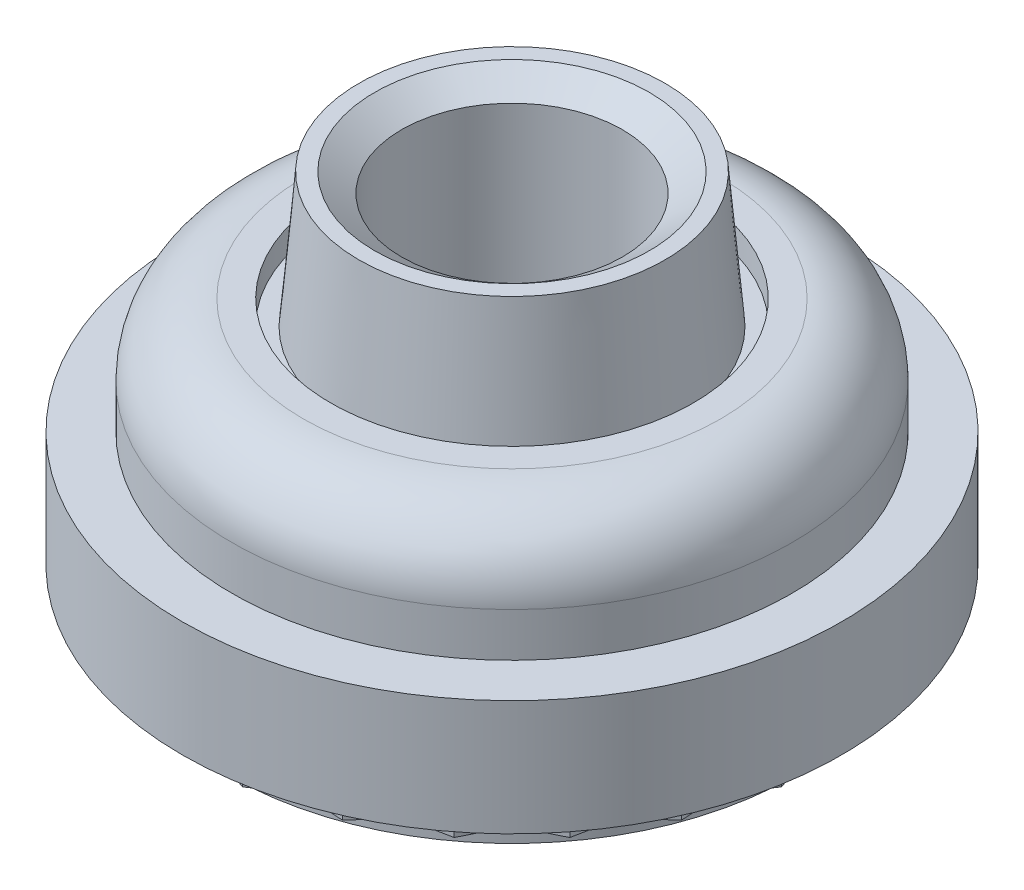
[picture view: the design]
ISO-10303-21;
HEADER;
FILE_DESCRIPTION(('STEP AP214'),'2;1');
FILE_NAME('part.step','',(''),(''),'','','');
FILE_SCHEMA(('AUTOMOTIVE_DESIGN { 1 0 10303 214 1 1 1 1 }'));
ENDSEC;
DATA;
#1=APPLICATION_CONTEXT('core data for automotive mechanical design processes');
#2=APPLICATION_PROTOCOL_DEFINITION('international standard','automotive_design',2000,#1);
#3=PRODUCT_CONTEXT('',#1,'mechanical');
#4=PRODUCT('Part','Part','',(#3));
#5=PRODUCT_RELATED_PRODUCT_CATEGORY('part','',(#4));
#6=PRODUCT_DEFINITION_FORMATION('','',#4);
#7=PRODUCT_DEFINITION_CONTEXT('part definition',#1,'design');
#8=PRODUCT_DEFINITION('design','',#6,#7);
#9=PRODUCT_DEFINITION_SHAPE('','',#8);
#10=(LENGTH_UNIT() NAMED_UNIT(*) SI_UNIT(.MILLI.,.METRE.));
#11=(NAMED_UNIT(*) PLANE_ANGLE_UNIT() SI_UNIT($,.RADIAN.));
#12=(NAMED_UNIT(*) SI_UNIT($,.STERADIAN.) SOLID_ANGLE_UNIT());
#13=UNCERTAINTY_MEASURE_WITH_UNIT(LENGTH_MEASURE(1.E-05),#10,'distance_accuracy_value','');
#14=(GEOMETRIC_REPRESENTATION_CONTEXT(3) GLOBAL_UNCERTAINTY_ASSIGNED_CONTEXT((#13)) GLOBAL_UNIT_ASSIGNED_CONTEXT((#10,
#11,#12)) REPRESENTATION_CONTEXT('',''));
#15=CARTESIAN_POINT('',(0.,0.,0.));
#16=DIRECTION('',(0.,0.,1.));
#17=DIRECTION('',(1.,0.,0.));
#18=AXIS2_PLACEMENT_3D('',#15,#16,#17);
#19=CARTESIAN_POINT('',(2.5527,-0.9652,0.));
#20=DIRECTION('',(0.,-1.,0.));
#21=DIRECTION('',(0.,0.,-1.));
#22=AXIS2_PLACEMENT_3D('',#19,#20,#21);
#23=PLANE('',#22);
#24=CARTESIAN_POINT('',(0.,-0.9652,0.));
#25=DIRECTION('',(0.,-1.,0.));
#26=DIRECTION('',(0.,0.,-1.));
#27=AXIS2_PLACEMENT_3D('',#24,#25,#26);
#28=CIRCLE('',#27,3.175);
#29=CARTESIAN_POINT('',(0.,-0.9652,-3.175));
#30=VERTEX_POINT('',#29);
#31=EDGE_CURVE('E39',#30,#30,#28,.T.);
#32=ORIENTED_EDGE('',*,*,#31,.F.);
#33=EDGE_LOOP('',(#32));
#34=FACE_BOUND('',#33,.T.);
#35=DIRECTION('',(-1.,0.,0.));
#36=VECTOR('',#35,1.);
#37=CARTESIAN_POINT('',(3.556,-0.9652,3.81));
#38=LINE('',#37,#36);
#39=CARTESIAN_POINT('',(3.556,-0.9652,3.81));
#40=VERTEX_POINT('',#39);
#41=CARTESIAN_POINT('',(-3.556,-0.9652,3.81));
#42=VERTEX_POINT('',#41);
#43=EDGE_CURVE('E752',#40,#42,#38,.T.);
#44=ORIENTED_EDGE('',*,*,#43,.T.);
#45=CARTESIAN_POINT('',(-3.556,-0.9652,3.556));
#46=DIRECTION('',(0.,-1.,0.));
#47=DIRECTION('',(0.,0.,1.));
#48=AXIS2_PLACEMENT_3D('',#45,#46,#47);
#49=CIRCLE('',#48,0.254);
#50=CARTESIAN_POINT('',(-3.81,-0.9652,3.556));
#51=VERTEX_POINT('',#50);
#52=EDGE_CURVE('E772',#42,#51,#49,.T.);
#53=ORIENTED_EDGE('',*,*,#52,.T.);
#54=DIRECTION('',(0.,0.,-1.));
#55=VECTOR('',#54,1.);
#56=CARTESIAN_POINT('',(-3.81,-0.9652,3.556));
#57=LINE('',#56,#55);
#58=CARTESIAN_POINT('',(-3.81,-0.9652,-3.556));
#59=VERTEX_POINT('',#58);
#60=EDGE_CURVE('E731',#51,#59,#57,.T.);
#61=ORIENTED_EDGE('',*,*,#60,.T.);
#62=CARTESIAN_POINT('',(-3.556,-0.9652,-3.556));
#63=DIRECTION('',(0.,-1.,0.));
#64=DIRECTION('',(0.,0.,-1.));
#65=AXIS2_PLACEMENT_3D('',#62,#63,#64);
#66=CIRCLE('',#65,0.254);
#67=CARTESIAN_POINT('',(-3.556,-0.9652,-3.81));
#68=VERTEX_POINT('',#67);
#69=EDGE_CURVE('E59',#59,#68,#66,.T.);
#70=ORIENTED_EDGE('',*,*,#69,.T.);
#71=DIRECTION('',(1.,0.,0.));
#72=VECTOR('',#71,1.);
#73=CARTESIAN_POINT('',(-3.556,-0.9652,-3.81));
#74=LINE('',#73,#72);
#75=CARTESIAN_POINT('',(3.556,-0.9652,-3.81));
#76=VERTEX_POINT('',#75);
#77=EDGE_CURVE('E776',#68,#76,#74,.T.);
#78=ORIENTED_EDGE('',*,*,#77,.T.);
#79=CARTESIAN_POINT('',(3.556,-0.9652,-3.556));
#80=DIRECTION('',(0.,-1.,0.));
#81=DIRECTION('',(0.,0.,-1.));
#82=AXIS2_PLACEMENT_3D('',#79,#80,#81);
#83=CIRCLE('',#82,0.254);
#84=CARTESIAN_POINT('',(3.81,-0.9652,-3.556));
#85=VERTEX_POINT('',#84);
#86=EDGE_CURVE('E779',#76,#85,#83,.T.);
#87=ORIENTED_EDGE('',*,*,#86,.T.);
#88=DIRECTION('',(0.,0.,1.));
#89=VECTOR('',#88,1.);
#90=CARTESIAN_POINT('',(3.81,-0.9652,-3.556));
#91=LINE('',#90,#89);
#92=CARTESIAN_POINT('',(3.81,-0.9652,3.556));
#93=VERTEX_POINT('',#92);
#94=EDGE_CURVE('E782',#85,#93,#91,.T.);
#95=ORIENTED_EDGE('',*,*,#94,.T.);
#96=CARTESIAN_POINT('',(3.556,-0.9652,3.556));
#97=DIRECTION('',(0.,-1.,0.));
#98=DIRECTION('',(0.,0.,-1.));
#99=AXIS2_PLACEMENT_3D('',#96,#97,#98);
#100=CIRCLE('',#99,0.254);
#101=EDGE_CURVE('E755',#93,#40,#100,.T.);
#102=ORIENTED_EDGE('',*,*,#101,.T.);
#103=EDGE_LOOP('',(#44,#53,#61,#70,#78,#87,#95,#102));
#104=FACE_BOUND('',#103,.T.);
#105=ADVANCED_FACE('F35',(#34,#104),#23,.T.);
#106=CARTESIAN_POINT('',(6.30489660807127,0.,0.));
#107=DIRECTION('',(0.,-1.,0.));
#108=DIRECTION('',(0.,0.,-1.));
#109=AXIS2_PLACEMENT_3D('',#106,#107,#108);
#110=PLANE('',#109);
#111=CARTESIAN_POINT('',(0.,0.,0.));
#112=DIRECTION('',(0.,-1.,0.));
#113=DIRECTION('',(0.,0.,-1.));
#114=AXIS2_PLACEMENT_3D('',#111,#112,#113);
#115=CIRCLE('',#114,7.62);
#116=CARTESIAN_POINT('',(0.,0.,-7.62));
#117=VERTEX_POINT('',#116);
#118=EDGE_CURVE('E1570',#117,#117,#115,.T.);
#119=ORIENTED_EDGE('',*,*,#118,.T.);
#120=EDGE_LOOP('',(#119));
#121=FACE_BOUND('',#120,.T.);
#122=DIRECTION('',(-0.947439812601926,0.,-0.31993405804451));
#123=VECTOR('',#122,1.);
#124=CARTESIAN_POINT('',(0.944879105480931,0.,7.17706935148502));
#125=LINE('',#124,#123);
#126=CARTESIAN_POINT('',(0.94487910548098,0.,7.17706935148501));
#127=VERTEX_POINT('',#126);
#128=CARTESIAN_POINT('',(0.,0.,6.858));
#129=VERTEX_POINT('',#128);
#130=EDGE_CURVE('E1522',#127,#129,#125,.T.);
#131=ORIENTED_EDGE('',*,*,#130,.F.);
#132=DIRECTION('',(-0.83235155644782,0.,0.5542480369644));
#133=VECTOR('',#132,1.);
#134=CARTESIAN_POINT('',(1.77498101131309,0.,6.62431931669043));
#135=LINE('',#134,#133);
#136=CARTESIAN_POINT('',(1.77498101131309,0.,6.62431931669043));
#137=VERTEX_POINT('',#136);
#138=EDGE_CURVE('E1507',#137,#127,#135,.T.);
#139=ORIENTED_EDGE('',*,*,#138,.F.);
#140=DIRECTION('',(-0.99796161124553,0.,-0.063817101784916));
#141=VECTOR('',#140,1.);
#142=CARTESIAN_POINT('',(2.77024536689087,0.,6.68796393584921));
#143=LINE('',#142,#141);
#144=CARTESIAN_POINT('',(2.77024536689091,0.,6.68796393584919));
#145=VERTEX_POINT('',#144);
#146=EDGE_CURVE('E1495',#145,#137,#143,.T.);
#147=ORIENTED_EDGE('',*,*,#146,.F.);
#148=DIRECTION('',(-0.660539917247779,0.,0.750790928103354));
#149=VECTOR('',#148,1.);
#150=CARTESIAN_POINT('',(3.42900000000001,0.,5.93920221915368));
#151=LINE('',#150,#149);
#152=CARTESIAN_POINT('',(3.42900000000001,0.,5.93920221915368));
#153=VERTEX_POINT('',#152);
#154=EDGE_CURVE('E1479',#153,#145,#151,.T.);
#155=ORIENTED_EDGE('',*,*,#154,.F.);
#156=DIRECTION('',(-0.98047397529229,0.,0.196648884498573));
#157=VECTOR('',#156,1.);
#158=CARTESIAN_POINT('',(4.40682398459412,0.,5.74308483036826));
#159=LINE('',#158,#157);
#160=CARTESIAN_POINT('',(4.40682398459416,0.,5.74308483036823));
#161=VERTEX_POINT('',#160);
#162=EDGE_CURVE('E1466',#161,#153,#159,.T.);
#163=ORIENTED_EDGE('',*,*,#162,.F.);
#164=DIRECTION('',(-0.443713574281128,0.,0.896168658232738));
#165=VECTOR('',#164,1.);
#166=CARTESIAN_POINT('',(4.84933830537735,0.,4.84933830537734));
#167=LINE('',#166,#165);
#168=CARTESIAN_POINT('',(4.84933830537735,0.,4.84933830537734));
#169=VERTEX_POINT('',#168);
#170=EDGE_CURVE('E1450',#169,#161,#167,.T.);
#171=ORIENTED_EDGE('',*,*,#170,.F.);
#172=DIRECTION('',(-0.896168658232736,0.,0.443713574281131));
#173=VECTOR('',#172,1.);
#174=CARTESIAN_POINT('',(5.74308483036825,0.,4.40682398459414));
#175=LINE('',#174,#173);
#176=CARTESIAN_POINT('',(5.74308483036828,0.,4.4068239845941));
#177=VERTEX_POINT('',#176);
#178=EDGE_CURVE('E1437',#177,#169,#175,.T.);
#179=ORIENTED_EDGE('',*,*,#178,.F.);
#180=DIRECTION('',(-0.19664888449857,0.,0.980473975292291));
#181=VECTOR('',#180,1.);
#182=CARTESIAN_POINT('',(5.93920221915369,0.,3.42899999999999));
#183=LINE('',#182,#181);
#184=CARTESIAN_POINT('',(5.93920221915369,0.,3.42899999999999));
#185=VERTEX_POINT('',#184);
#186=EDGE_CURVE('E1421',#185,#177,#183,.T.);
#187=ORIENTED_EDGE('',*,*,#186,.F.);
#188=DIRECTION('',(-0.750790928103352,0.,0.660539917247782));
#189=VECTOR('',#188,1.);
#190=CARTESIAN_POINT('',(6.6879639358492,0.,2.77024536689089));
#191=LINE('',#190,#189);
#192=CARTESIAN_POINT('',(6.68796393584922,0.,2.77024536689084));
#193=VERTEX_POINT('',#192);
#194=EDGE_CURVE('E1408',#193,#185,#191,.T.);
#195=ORIENTED_EDGE('',*,*,#194,.F.);
#196=DIRECTION('',(0.0638171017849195,0.,0.99796161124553));
#197=VECTOR('',#196,1.);
#198=CARTESIAN_POINT('',(6.62431931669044,0.,1.77498101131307));
#199=LINE('',#198,#197);
#200=CARTESIAN_POINT('',(6.62431931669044,0.,1.77498101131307));
#201=VERTEX_POINT('',#200);
#202=EDGE_CURVE('E1392',#201,#193,#199,.T.);
#203=ORIENTED_EDGE('',*,*,#202,.F.);
#204=DIRECTION('',(-0.554248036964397,0.,0.832351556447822));
#205=VECTOR('',#204,1.);
#206=CARTESIAN_POINT('',(7.17706935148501,0.,0.944879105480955));
#207=LINE('',#206,#205);
#208=CARTESIAN_POINT('',(7.17706935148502,0.,0.944879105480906));
#209=VERTEX_POINT('',#208);
#210=EDGE_CURVE('E1379',#209,#201,#207,.T.);
#211=ORIENTED_EDGE('',*,*,#210,.F.);
#212=DIRECTION('',(0.319934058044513,0.,0.947439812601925));
#213=VECTOR('',#212,1.);
#214=CARTESIAN_POINT('',(6.858,0.,0.));
#215=LINE('',#214,#213);
#216=CARTESIAN_POINT('',(6.858,0.,0.));
#217=VERTEX_POINT('',#216);
#218=EDGE_CURVE('E1363',#217,#209,#215,.T.);
#219=ORIENTED_EDGE('',*,*,#218,.F.);
#220=DIRECTION('',(-0.319934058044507,0.,0.947439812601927));
#221=VECTOR('',#220,1.);
#222=CARTESIAN_POINT('',(7.17706935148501,0.,-0.944879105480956));
#223=LINE('',#222,#221);
#224=CARTESIAN_POINT('',(7.17706935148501,0.,-0.944879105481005));
#225=VERTEX_POINT('',#224);
#226=EDGE_CURVE('E1350',#225,#217,#223,.T.);
#227=ORIENTED_EDGE('',*,*,#226,.F.);
#228=DIRECTION('',(0.554248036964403,0.,0.832351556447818));
#229=VECTOR('',#228,1.);
#230=CARTESIAN_POINT('',(6.62431931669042,0.,-1.77498101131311));
#231=LINE('',#230,#229);
#232=CARTESIAN_POINT('',(6.62431931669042,0.,-1.77498101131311));
#233=VERTEX_POINT('',#232);
#234=EDGE_CURVE('E1334',#233,#225,#231,.T.);
#235=ORIENTED_EDGE('',*,*,#234,.F.);
#236=DIRECTION('',(-0.0638171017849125,0.,0.99796161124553));
#237=VECTOR('',#236,1.);
#238=CARTESIAN_POINT('',(6.6879639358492,0.,-2.77024536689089));
#239=LINE('',#238,#237);
#240=CARTESIAN_POINT('',(6.68796393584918,0.,-2.77024536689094));
#241=VERTEX_POINT('',#240);
#242=EDGE_CURVE('E1321',#241,#233,#239,.T.);
#243=ORIENTED_EDGE('',*,*,#242,.F.);
#244=DIRECTION('',(0.750790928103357,0.,0.660539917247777));
#245=VECTOR('',#244,1.);
#246=CARTESIAN_POINT('',(5.93920221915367,0.,-3.42900000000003));
#247=LINE('',#246,#245);
#248=CARTESIAN_POINT('',(5.93920221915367,0.,-3.42900000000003));
#249=VERTEX_POINT('',#248);
#250=EDGE_CURVE('E1305',#249,#241,#247,.T.);
#251=ORIENTED_EDGE('',*,*,#250,.F.);
#252=DIRECTION('',(0.196648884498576,0.,0.98047397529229));
#253=VECTOR('',#252,1.);
#254=CARTESIAN_POINT('',(5.74308483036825,0.,-4.40682398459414));
#255=LINE('',#254,#253);
#256=CARTESIAN_POINT('',(5.74308483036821,0.,-4.40682398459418));
#257=VERTEX_POINT('',#256);
#258=EDGE_CURVE('E1292',#257,#249,#255,.T.);
#259=ORIENTED_EDGE('',*,*,#258,.F.);
#260=DIRECTION('',(0.896168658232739,0.,0.443713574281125));
#261=VECTOR('',#260,1.);
#262=CARTESIAN_POINT('',(4.84933830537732,0.,-4.84933830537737));
#263=LINE('',#262,#261);
#264=CARTESIAN_POINT('',(4.84933830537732,0.,-4.84933830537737));
#265=VERTEX_POINT('',#264);
#266=EDGE_CURVE('E1276',#265,#257,#263,.T.);
#267=ORIENTED_EDGE('',*,*,#266,.F.);
#268=DIRECTION('',(0.443713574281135,0.,0.896168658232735));
#269=VECTOR('',#268,1.);
#270=CARTESIAN_POINT('',(4.40682398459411,0.,-5.74308483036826));
#271=LINE('',#270,#269);
#272=CARTESIAN_POINT('',(4.40682398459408,0.,-5.74308483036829));
#273=VERTEX_POINT('',#272);
#274=EDGE_CURVE('E1263',#273,#265,#271,.T.);
#275=ORIENTED_EDGE('',*,*,#274,.F.);
#276=DIRECTION('',(0.980473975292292,0.,0.196648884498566));
#277=VECTOR('',#276,1.);
#278=CARTESIAN_POINT('',(3.42899999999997,0.,-5.9392022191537));
#279=LINE('',#278,#277);
#280=CARTESIAN_POINT('',(3.42899999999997,0.,-5.9392022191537));
#281=VERTEX_POINT('',#280);
#282=EDGE_CURVE('E1247',#281,#273,#279,.T.);
#283=ORIENTED_EDGE('',*,*,#282,.F.);
#284=DIRECTION('',(0.660539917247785,0.,0.75079092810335));
#285=VECTOR('',#284,1.);
#286=CARTESIAN_POINT('',(2.77024536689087,0.,-6.68796393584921));
#287=LINE('',#286,#285);
#288=CARTESIAN_POINT('',(2.77024536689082,0.,-6.68796393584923));
#289=VERTEX_POINT('',#288);
#290=EDGE_CURVE('E1234',#289,#281,#287,.T.);
#291=ORIENTED_EDGE('',*,*,#290,.F.);
#292=DIRECTION('',(0.997961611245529,0.,-0.063817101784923));
#293=VECTOR('',#292,1.);
#294=CARTESIAN_POINT('',(1.77498101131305,0.,-6.62431931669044));
#295=LINE('',#294,#293);
#296=CARTESIAN_POINT('',(1.77498101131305,0.,-6.62431931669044));
#297=VERTEX_POINT('',#296);
#298=EDGE_CURVE('E1218',#297,#289,#295,.T.);
#299=ORIENTED_EDGE('',*,*,#298,.F.);
#300=DIRECTION('',(0.832351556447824,0.,0.554248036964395));
#301=VECTOR('',#300,1.);
#302=CARTESIAN_POINT('',(0.94487910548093,0.,-7.17706935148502));
#303=LINE('',#302,#301);
#304=CARTESIAN_POINT('',(0.944879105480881,0.,-7.17706935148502));
#305=VERTEX_POINT('',#304);
#306=EDGE_CURVE('E1205',#305,#297,#303,.T.);
#307=ORIENTED_EDGE('',*,*,#306,.F.);
#308=DIRECTION('',(0.947439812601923,0.,-0.319934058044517));
#309=VECTOR('',#308,1.);
#310=CARTESIAN_POINT('',(0.,0.,-6.858));
#311=LINE('',#310,#309);
#312=CARTESIAN_POINT('',(0.,0.,-6.858));
#313=VERTEX_POINT('',#312);
#314=EDGE_CURVE('E1189',#313,#305,#311,.T.);
#315=ORIENTED_EDGE('',*,*,#314,.F.);
#316=DIRECTION('',(0.947439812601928,0.,0.319934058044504));
#317=VECTOR('',#316,1.);
#318=CARTESIAN_POINT('',(-0.944879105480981,0.,-7.17706935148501));
#319=LINE('',#318,#317);
#320=CARTESIAN_POINT('',(-0.944879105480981,0.,-7.17706935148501));
#321=VERTEX_POINT('',#320);
#322=EDGE_CURVE('E1176',#321,#313,#319,.T.);
#323=ORIENTED_EDGE('',*,*,#322,.F.);
#324=DIRECTION('',(0.832351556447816,0.,-0.554248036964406));
#325=VECTOR('',#324,1.);
#326=CARTESIAN_POINT('',(-1.77498101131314,0.,-6.62431931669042));
#327=LINE('',#326,#325);
#328=CARTESIAN_POINT('',(-1.77498101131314,0.,-6.62431931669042));
#329=VERTEX_POINT('',#328);
#330=EDGE_CURVE('E1160',#329,#321,#327,.T.);
#331=ORIENTED_EDGE('',*,*,#330,.F.);
#332=DIRECTION('',(0.99796161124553,0.,0.063817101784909));
#333=VECTOR('',#332,1.);
#334=CARTESIAN_POINT('',(-2.77024536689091,0.,-6.68796393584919));
#335=LINE('',#334,#333);
#336=CARTESIAN_POINT('',(-2.77024536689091,0.,-6.68796393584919));
#337=VERTEX_POINT('',#336);
#338=EDGE_CURVE('E1147',#337,#329,#335,.T.);
#339=ORIENTED_EDGE('',*,*,#338,.F.);
#340=DIRECTION('',(0.660539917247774,0.,-0.750790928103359));
#341=VECTOR('',#340,1.);
#342=CARTESIAN_POINT('',(-3.42900000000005,0.,-5.93920221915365));
#343=LINE('',#342,#341);
#344=CARTESIAN_POINT('',(-3.42900000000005,0.,-5.93920221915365));
#345=VERTEX_POINT('',#344);
#346=EDGE_CURVE('E1131',#345,#337,#343,.T.);
#347=ORIENTED_EDGE('',*,*,#346,.F.);
#348=DIRECTION('',(0.980473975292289,0.,-0.19664888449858));
#349=VECTOR('',#348,1.);
#350=CARTESIAN_POINT('',(-4.40682398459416,0.,-5.74308483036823));
#351=LINE('',#350,#349);
#352=CARTESIAN_POINT('',(-4.40682398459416,0.,-5.74308483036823));
#353=VERTEX_POINT('',#352);
#354=EDGE_CURVE('E1118',#353,#345,#351,.T.);
#355=ORIENTED_EDGE('',*,*,#354,.F.);
#356=DIRECTION('',(0.443713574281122,0.,-0.896168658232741));
#357=VECTOR('',#356,1.);
#358=CARTESIAN_POINT('',(-4.84933830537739,0.,-4.8493383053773));
#359=LINE('',#358,#357);
#360=CARTESIAN_POINT('',(-4.84933830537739,0.,-4.8493383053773));
#361=VERTEX_POINT('',#360);
#362=EDGE_CURVE('E1102',#361,#353,#359,.T.);
#363=ORIENTED_EDGE('',*,*,#362,.F.);
#364=DIRECTION('',(0.896168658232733,0.,-0.443713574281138));
#365=VECTOR('',#364,1.);
#366=CARTESIAN_POINT('',(-5.74308483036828,0.,-4.4068239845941));
#367=LINE('',#366,#365);
#368=CARTESIAN_POINT('',(-5.74308483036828,0.,-4.4068239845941));
#369=VERTEX_POINT('',#368);
#370=EDGE_CURVE('E1089',#369,#361,#367,.T.);
#371=ORIENTED_EDGE('',*,*,#370,.F.);
#372=DIRECTION('',(0.196648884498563,0.,-0.980473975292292));
#373=VECTOR('',#372,1.);
#374=CARTESIAN_POINT('',(-5.93920221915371,0.,-3.42899999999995));
#375=LINE('',#374,#373);
#376=CARTESIAN_POINT('',(-5.93920221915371,0.,-3.42899999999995));
#377=VERTEX_POINT('',#376);
#378=EDGE_CURVE('E1073',#377,#369,#375,.T.);
#379=ORIENTED_EDGE('',*,*,#378,.F.);
#380=DIRECTION('',(0.750790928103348,0.,-0.660539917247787));
#381=VECTOR('',#380,1.);
#382=CARTESIAN_POINT('',(-6.68796393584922,0.,-2.77024536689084));
#383=LINE('',#382,#381);
#384=CARTESIAN_POINT('',(-6.68796393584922,0.,-2.77024536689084));
#385=VERTEX_POINT('',#384);
#386=EDGE_CURVE('E1060',#385,#377,#383,.T.);
#387=ORIENTED_EDGE('',*,*,#386,.F.);
#388=DIRECTION('',(-0.0638171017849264,0.,-0.997961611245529));
#389=VECTOR('',#388,1.);
#390=CARTESIAN_POINT('',(-6.62431931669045,0.,-1.77498101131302));
#391=LINE('',#390,#389);
#392=CARTESIAN_POINT('',(-6.62431931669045,0.,-1.77498101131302));
#393=VERTEX_POINT('',#392);
#394=EDGE_CURVE('E1044',#393,#385,#391,.T.);
#395=ORIENTED_EDGE('',*,*,#394,.F.);
#396=DIRECTION('',(0.554248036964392,0.,-0.832351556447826));
#397=VECTOR('',#396,1.);
#398=CARTESIAN_POINT('',(-7.17706935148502,0.,-0.944879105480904));
#399=LINE('',#398,#397);
#400=CARTESIAN_POINT('',(-7.17706935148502,0.,-0.944879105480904));
#401=VERTEX_POINT('',#400);
#402=EDGE_CURVE('E1031',#401,#393,#399,.T.);
#403=ORIENTED_EDGE('',*,*,#402,.F.);
#404=DIRECTION('',(-0.31993405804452,0.,-0.947439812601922));
#405=VECTOR('',#404,1.);
#406=CARTESIAN_POINT('',(-6.858,0.,0.));
#407=LINE('',#406,#405);
#408=CARTESIAN_POINT('',(-6.858,0.,0.));
#409=VERTEX_POINT('',#408);
#410=EDGE_CURVE('E1015',#409,#401,#407,.T.);
#411=ORIENTED_EDGE('',*,*,#410,.F.);
#412=DIRECTION('',(0.3199340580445,0.,-0.947439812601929));
#413=VECTOR('',#412,1.);
#414=CARTESIAN_POINT('',(-7.17706935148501,0.,0.944879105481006));
#415=LINE('',#414,#413);
#416=CARTESIAN_POINT('',(-7.17706935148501,0.,0.944879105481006));
#417=VERTEX_POINT('',#416);
#418=EDGE_CURVE('E1002',#417,#409,#415,.T.);
#419=ORIENTED_EDGE('',*,*,#418,.F.);
#420=DIRECTION('',(-0.554248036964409,0.,-0.832351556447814));
#421=VECTOR('',#420,1.);
#422=CARTESIAN_POINT('',(-6.62431931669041,0.,1.77498101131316));
#423=LINE('',#422,#421);
#424=CARTESIAN_POINT('',(-6.62431931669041,0.,1.77498101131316));
#425=VERTEX_POINT('',#424);
#426=EDGE_CURVE('E986',#425,#417,#423,.T.);
#427=ORIENTED_EDGE('',*,*,#426,.F.);
#428=DIRECTION('',(0.0638171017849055,0.,-0.99796161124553));
#429=VECTOR('',#428,1.);
#430=CARTESIAN_POINT('',(-6.68796393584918,0.,2.77024536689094));
#431=LINE('',#430,#429);
#432=CARTESIAN_POINT('',(-6.68796393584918,0.,2.77024536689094));
#433=VERTEX_POINT('',#432);
#434=EDGE_CURVE('E973',#433,#425,#431,.T.);
#435=ORIENTED_EDGE('',*,*,#434,.F.);
#436=DIRECTION('',(-0.750790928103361,0.,-0.660539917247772));
#437=VECTOR('',#436,1.);
#438=CARTESIAN_POINT('',(-5.93920221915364,0.,3.42900000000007));
#439=LINE('',#438,#437);
#440=CARTESIAN_POINT('',(-5.93920221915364,0.,3.42900000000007));
#441=VERTEX_POINT('',#440);
#442=EDGE_CURVE('E957',#441,#433,#439,.T.);
#443=ORIENTED_EDGE('',*,*,#442,.F.);
#444=DIRECTION('',(-0.196648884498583,0.,-0.980473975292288));
#445=VECTOR('',#444,1.);
#446=CARTESIAN_POINT('',(-5.74308483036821,0.,4.40682398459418));
#447=LINE('',#446,#445);
#448=CARTESIAN_POINT('',(-5.74308483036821,0.,4.40682398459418));
#449=VERTEX_POINT('',#448);
#450=EDGE_CURVE('E944',#449,#441,#447,.T.);
#451=ORIENTED_EDGE('',*,*,#450,.F.);
#452=DIRECTION('',(-0.896168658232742,0.,-0.443713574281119));
#453=VECTOR('',#452,1.);
#454=CARTESIAN_POINT('',(-4.84933830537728,0.,4.8493383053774));
#455=LINE('',#454,#453);
#456=CARTESIAN_POINT('',(-4.84933830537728,0.,4.8493383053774));
#457=VERTEX_POINT('',#456);
#458=EDGE_CURVE('E928',#457,#449,#455,.T.);
#459=ORIENTED_EDGE('',*,*,#458,.F.);
#460=DIRECTION('',(-0.443713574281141,0.,-0.896168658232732));
#461=VECTOR('',#460,1.);
#462=CARTESIAN_POINT('',(-4.40682398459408,0.,5.74308483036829));
#463=LINE('',#462,#461);
#464=CARTESIAN_POINT('',(-4.40682398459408,0.,5.74308483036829));
#465=VERTEX_POINT('',#464);
#466=EDGE_CURVE('E915',#465,#457,#463,.T.);
#467=ORIENTED_EDGE('',*,*,#466,.F.);
#468=DIRECTION('',(-0.980473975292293,0.,-0.196648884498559));
#469=VECTOR('',#468,1.);
#470=CARTESIAN_POINT('',(-3.42899999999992,0.,5.93920221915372));
#471=LINE('',#470,#469);
#472=CARTESIAN_POINT('',(-3.42899999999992,0.,5.93920221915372));
#473=VERTEX_POINT('',#472);
#474=EDGE_CURVE('E899',#473,#465,#471,.T.);
#475=ORIENTED_EDGE('',*,*,#474,.F.);
#476=DIRECTION('',(-0.66053991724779,0.,-0.750790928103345));
#477=VECTOR('',#476,1.);
#478=CARTESIAN_POINT('',(-2.77024536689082,0.,6.68796393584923));
#479=LINE('',#478,#477);
#480=CARTESIAN_POINT('',(-2.77024536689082,0.,6.68796393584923));
#481=VERTEX_POINT('',#480);
#482=EDGE_CURVE('E886',#481,#473,#479,.T.);
#483=ORIENTED_EDGE('',*,*,#482,.F.);
#484=DIRECTION('',(-0.997961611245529,0.,0.0638171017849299));
#485=VECTOR('',#484,1.);
#486=CARTESIAN_POINT('',(-1.774981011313,0.,6.62431931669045));
#487=LINE('',#486,#485);
#488=CARTESIAN_POINT('',(-1.774981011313,0.,6.62431931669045));
#489=VERTEX_POINT('',#488);
#490=EDGE_CURVE('E875',#489,#481,#487,.T.);
#491=ORIENTED_EDGE('',*,*,#490,.F.);
#492=DIRECTION('',(-0.832351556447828,0.,-0.554248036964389));
#493=VECTOR('',#492,1.);
#494=CARTESIAN_POINT('',(-0.94487910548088,0.,7.17706935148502));
#495=LINE('',#494,#493);
#496=CARTESIAN_POINT('',(-0.94487910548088,0.,7.17706935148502));
#497=VERTEX_POINT('',#496);
#498=EDGE_CURVE('E848',#497,#489,#495,.T.);
#499=ORIENTED_EDGE('',*,*,#498,.F.);
#500=DIRECTION('',(-0.947439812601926,0.,0.31993405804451));
#501=VECTOR('',#500,1.);
#502=CARTESIAN_POINT('',(0.,0.,6.858));
#503=LINE('',#502,#501);
#504=EDGE_CURVE('E1536',#129,#497,#503,.T.);
#505=ORIENTED_EDGE('',*,*,#504,.F.);
#506=EDGE_LOOP('',(#131,#139,#147,#155,#163,#171,#179,#187,#195,#203,#211,#219,#227,#235,#243,
#251,#259,#267,#275,#283,#291,#299,#307,#315,#323,#331,#339,#347,#355,#363,#371,#379,#387,#395,
#403,#411,#419,#427,#435,#443,#451,#459,#467,#475,#483,#491,#499,#505));
#507=FACE_BOUND('',#506,.T.);
#508=ADVANCED_FACE('F1622',(#121,#507),#110,.T.);
#509=CARTESIAN_POINT('',(0.,0.,0.));
#510=DIRECTION('',(0.,-1.,0.));
#511=DIRECTION('',(0.,0.,-1.));
#512=AXIS2_PLACEMENT_3D('',#509,#510,#511);
#513=CIRCLE('',#512,6.30489660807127);
#514=CARTESIAN_POINT('',(0.,0.,-6.30489660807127));
#515=VERTEX_POINT('',#514);
#516=EDGE_CURVE('E1573',#515,#515,#513,.T.);
#517=ORIENTED_EDGE('',*,*,#516,.F.);
#518=EDGE_LOOP('',(#517));
#519=FACE_BOUND('',#518,.T.);
#520=DIRECTION('',(0.99796161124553,0.,0.0638171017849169));
#521=VECTOR('',#520,1.);
#522=CARTESIAN_POINT('',(1.7217315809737,0.,6.42558973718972));
#523=LINE('',#522,#521);
#524=CARTESIAN_POINT('',(1.7217315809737,0.,6.42558973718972));
#525=VERTEX_POINT('',#524);
#526=CARTESIAN_POINT('',(2.68713800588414,0.,6.48732501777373));
#527=VERTEX_POINT('',#526);
#528=EDGE_CURVE('E1499',#525,#527,#523,.T.);
#529=ORIENTED_EDGE('',*,*,#528,.F.);
#530=DIRECTION('',(0.83235155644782,0.,-0.554248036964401));
#531=VECTOR('',#530,1.);
#532=CARTESIAN_POINT('',(0.916532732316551,0.,6.96175727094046));
#533=LINE('',#532,#531);
#534=CARTESIAN_POINT('',(0.916532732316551,0.,6.96175727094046));
#535=VERTEX_POINT('',#534);
#536=EDGE_CURVE('E1509',#535,#525,#533,.T.);
#537=ORIENTED_EDGE('',*,*,#536,.F.);
#538=DIRECTION('',(0.947439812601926,0.,0.319934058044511));
#539=VECTOR('',#538,1.);
#540=CARTESIAN_POINT('',(0.,0.,6.65226));
#541=LINE('',#540,#539);
#542=CARTESIAN_POINT('',(0.,0.,6.65226));
#543=VERTEX_POINT('',#542);
#544=EDGE_CURVE('E1526',#543,#535,#541,.T.);
#545=ORIENTED_EDGE('',*,*,#544,.F.);
#546=DIRECTION('',(0.947439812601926,0.,-0.319934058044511));
#547=VECTOR('',#546,1.);
#548=CARTESIAN_POINT('',(-0.916532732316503,0.,6.96175727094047));
#549=LINE('',#548,#547);
#550=CARTESIAN_POINT('',(-0.916532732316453,0.,6.96175727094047));
#551=VERTEX_POINT('',#550);
#552=EDGE_CURVE('E1539',#551,#543,#549,.T.);
#553=ORIENTED_EDGE('',*,*,#552,.F.);
#554=DIRECTION('',(0.832351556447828,0.,0.55424803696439));
#555=VECTOR('',#554,1.);
#556=CARTESIAN_POINT('',(-1.72173158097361,0.,6.42558973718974));
#557=LINE('',#556,#555);
#558=CARTESIAN_POINT('',(-1.72173158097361,0.,6.42558973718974));
#559=VERTEX_POINT('',#558);
#560=EDGE_CURVE('E865',#559,#551,#557,.T.);
#561=ORIENTED_EDGE('',*,*,#560,.F.);
#562=DIRECTION('',(0.997961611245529,0.,-0.0638171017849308));
#563=VECTOR('',#562,1.);
#564=CARTESIAN_POINT('',(-2.68713800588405,0.,6.48732501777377));
#565=LINE('',#564,#563);
#566=CARTESIAN_POINT('',(-2.68713800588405,0.,6.48732501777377));
#567=VERTEX_POINT('',#566);
#568=EDGE_CURVE('E878',#567,#559,#565,.T.);
#569=ORIENTED_EDGE('',*,*,#568,.F.);
#570=DIRECTION('',(0.660539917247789,0.,0.750790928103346));
#571=VECTOR('',#570,1.);
#572=CARTESIAN_POINT('',(-3.32612999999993,0.,5.76102615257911));
#573=LINE('',#572,#571);
#574=CARTESIAN_POINT('',(-3.32612999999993,0.,5.76102615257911));
#575=VERTEX_POINT('',#574);
#576=EDGE_CURVE('E890',#575,#567,#573,.T.);
#577=ORIENTED_EDGE('',*,*,#576,.F.);
#578=DIRECTION('',(0.980473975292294,0.,0.196648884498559));
#579=VECTOR('',#578,1.);
#580=CARTESIAN_POINT('',(-4.27461926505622,0.,5.57079228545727));
#581=LINE('',#580,#579);
#582=CARTESIAN_POINT('',(-4.27461926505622,0.,5.57079228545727));
#583=VERTEX_POINT('',#582);
#584=EDGE_CURVE('E902',#583,#575,#581,.T.);
#585=ORIENTED_EDGE('',*,*,#584,.F.);
#586=DIRECTION('',(0.44371357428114,0.,0.896168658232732));
#587=VECTOR('',#586,1.);
#588=CARTESIAN_POINT('',(-4.70385815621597,0.,4.70385815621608));
#589=LINE('',#588,#587);
#590=CARTESIAN_POINT('',(-4.70385815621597,0.,4.70385815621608));
#591=VERTEX_POINT('',#590);
#592=EDGE_CURVE('E919',#591,#583,#589,.T.);
#593=ORIENTED_EDGE('',*,*,#592,.F.);
#594=DIRECTION('',(0.896168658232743,0.,0.443713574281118));
#595=VECTOR('',#594,1.);
#596=CARTESIAN_POINT('',(-5.57079228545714,0.,4.27461926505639));
#597=LINE('',#596,#595);
#598=CARTESIAN_POINT('',(-5.57079228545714,0.,4.27461926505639));
#599=VERTEX_POINT('',#598);
#600=EDGE_CURVE('E931',#599,#591,#597,.T.);
#601=ORIENTED_EDGE('',*,*,#600,.F.);
#602=DIRECTION('',(0.196648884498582,0.,0.980473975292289));
#603=VECTOR('',#602,1.);
#604=CARTESIAN_POINT('',(-5.76102615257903,0.,3.32613000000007));
#605=LINE('',#604,#603);
#606=CARTESIAN_POINT('',(-5.76102615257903,0.,3.32613000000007));
#607=VERTEX_POINT('',#606);
#608=EDGE_CURVE('E948',#607,#599,#605,.T.);
#609=ORIENTED_EDGE('',*,*,#608,.F.);
#610=DIRECTION('',(0.750790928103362,0.,0.660539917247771));
#611=VECTOR('',#610,1.);
#612=CARTESIAN_POINT('',(-6.48732501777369,0.,2.68713800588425));
#613=LINE('',#612,#611);
#614=CARTESIAN_POINT('',(-6.48732501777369,0.,2.68713800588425));
#615=VERTEX_POINT('',#614);
#616=EDGE_CURVE('E960',#615,#607,#613,.T.);
#617=ORIENTED_EDGE('',*,*,#616,.F.);
#618=DIRECTION('',(-0.0638171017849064,0.,0.99796161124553));
#619=VECTOR('',#618,1.);
#620=CARTESIAN_POINT('',(-6.4255897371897,0.,1.72173158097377));
#621=LINE('',#620,#619);
#622=CARTESIAN_POINT('',(-6.4255897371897,0.,1.72173158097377));
#623=VERTEX_POINT('',#622);
#624=EDGE_CURVE('E977',#623,#615,#621,.T.);
#625=ORIENTED_EDGE('',*,*,#624,.F.);
#626=DIRECTION('',(0.55424803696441,0.,0.832351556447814));
#627=VECTOR('',#626,1.);
#628=CARTESIAN_POINT('',(-6.96175727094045,0.,0.916532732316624));
#629=LINE('',#628,#627);
#630=CARTESIAN_POINT('',(-6.96175727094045,0.,0.916532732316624));
#631=VERTEX_POINT('',#630);
#632=EDGE_CURVE('E989',#631,#623,#629,.T.);
#633=ORIENTED_EDGE('',*,*,#632,.F.);
#634=DIRECTION('',(-0.319934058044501,0.,0.947439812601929));
#635=VECTOR('',#634,1.);
#636=CARTESIAN_POINT('',(-6.65226,0.,0.));
#637=LINE('',#636,#635);
#638=CARTESIAN_POINT('',(-6.65226,0.,0.));
#639=VERTEX_POINT('',#638);
#640=EDGE_CURVE('E1006',#639,#631,#637,.T.);
#641=ORIENTED_EDGE('',*,*,#640,.F.);
#642=DIRECTION('',(0.319934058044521,0.,0.947439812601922));
#643=VECTOR('',#642,1.);
#644=CARTESIAN_POINT('',(-6.96175727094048,0.,-0.91653273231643));
#645=LINE('',#644,#643);
#646=CARTESIAN_POINT('',(-6.96175727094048,0.,-0.91653273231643));
#647=VERTEX_POINT('',#646);
#648=EDGE_CURVE('E1018',#647,#639,#645,.T.);
#649=ORIENTED_EDGE('',*,*,#648,.F.);
#650=DIRECTION('',(-0.554248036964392,0.,0.832351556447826));
#651=VECTOR('',#650,1.);
#652=CARTESIAN_POINT('',(-6.42558973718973,0.,-1.72173158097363));
#653=LINE('',#652,#651);
#654=CARTESIAN_POINT('',(-6.42558973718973,0.,-1.72173158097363));
#655=VERTEX_POINT('',#654);
#656=EDGE_CURVE('E1035',#655,#647,#653,.T.);
#657=ORIENTED_EDGE('',*,*,#656,.F.);
#658=DIRECTION('',(0.0638171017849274,0.,0.997961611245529));
#659=VECTOR('',#658,1.);
#660=CARTESIAN_POINT('',(-6.48732501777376,0.,-2.68713800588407));
#661=LINE('',#660,#659);
#662=CARTESIAN_POINT('',(-6.48732501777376,0.,-2.68713800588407));
#663=VERTEX_POINT('',#662);
#664=EDGE_CURVE('E1047',#663,#655,#661,.T.);
#665=ORIENTED_EDGE('',*,*,#664,.F.);
#666=DIRECTION('',(-0.750790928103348,0.,0.660539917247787));
#667=VECTOR('',#666,1.);
#668=CARTESIAN_POINT('',(-5.7610261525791,0.,-3.32612999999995));
#669=LINE('',#668,#667);
#670=CARTESIAN_POINT('',(-5.7610261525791,0.,-3.32612999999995));
#671=VERTEX_POINT('',#670);
#672=EDGE_CURVE('E1064',#671,#663,#669,.T.);
#673=ORIENTED_EDGE('',*,*,#672,.F.);
#674=DIRECTION('',(-0.196648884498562,0.,0.980473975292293));
#675=VECTOR('',#674,1.);
#676=CARTESIAN_POINT('',(-5.57079228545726,0.,-4.27461926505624));
#677=LINE('',#676,#675);
#678=CARTESIAN_POINT('',(-5.57079228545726,0.,-4.27461926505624));
#679=VERTEX_POINT('',#678);
#680=EDGE_CURVE('E1076',#679,#671,#677,.T.);
#681=ORIENTED_EDGE('',*,*,#680,.F.);
#682=DIRECTION('',(-0.896168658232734,0.,0.443713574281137));
#683=VECTOR('',#682,1.);
#684=CARTESIAN_POINT('',(-4.70385815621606,0.,-4.70385815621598));
#685=LINE('',#684,#683);
#686=CARTESIAN_POINT('',(-4.70385815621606,0.,-4.70385815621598));
#687=VERTEX_POINT('',#686);
#688=EDGE_CURVE('E1093',#687,#679,#685,.T.);
#689=ORIENTED_EDGE('',*,*,#688,.F.);
#690=DIRECTION('',(-0.443713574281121,0.,0.896168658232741));
#691=VECTOR('',#690,1.);
#692=CARTESIAN_POINT('',(-4.27461926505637,0.,-5.57079228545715));
#693=LINE('',#692,#691);
#694=CARTESIAN_POINT('',(-4.27461926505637,0.,-5.57079228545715));
#695=VERTEX_POINT('',#694);
#696=EDGE_CURVE('E1105',#695,#687,#693,.T.);
#697=ORIENTED_EDGE('',*,*,#696,.F.);
#698=DIRECTION('',(-0.980473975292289,0.,0.196648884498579));
#699=VECTOR('',#698,1.);
#700=CARTESIAN_POINT('',(-3.32613000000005,0.,-5.76102615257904));
#701=LINE('',#700,#699);
#702=CARTESIAN_POINT('',(-3.32613000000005,0.,-5.76102615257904));
#703=VERTEX_POINT('',#702);
#704=EDGE_CURVE('E1122',#703,#695,#701,.T.);
#705=ORIENTED_EDGE('',*,*,#704,.F.);
#706=DIRECTION('',(-0.660539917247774,0.,0.75079092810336));
#707=VECTOR('',#706,1.);
#708=CARTESIAN_POINT('',(-2.68713800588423,0.,-6.4873250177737));
#709=LINE('',#708,#707);
#710=CARTESIAN_POINT('',(-2.68713800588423,0.,-6.4873250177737));
#711=VERTEX_POINT('',#710);
#712=EDGE_CURVE('E1134',#711,#703,#709,.T.);
#713=ORIENTED_EDGE('',*,*,#712,.F.);
#714=DIRECTION('',(-0.99796161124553,0.,-0.0638171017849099));
#715=VECTOR('',#714,1.);
#716=CARTESIAN_POINT('',(-1.72173158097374,0.,-6.4255897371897));
#717=LINE('',#716,#715);
#718=CARTESIAN_POINT('',(-1.72173158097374,0.,-6.4255897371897));
#719=VERTEX_POINT('',#718);
#720=EDGE_CURVE('E1151',#719,#711,#717,.T.);
#721=ORIENTED_EDGE('',*,*,#720,.F.);
#722=DIRECTION('',(-0.832351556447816,0.,0.554248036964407));
#723=VECTOR('',#722,1.);
#724=CARTESIAN_POINT('',(-0.916532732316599,0.,-6.96175727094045));
#725=LINE('',#724,#723);
#726=CARTESIAN_POINT('',(-0.916532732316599,0.,-6.96175727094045));
#727=VERTEX_POINT('',#726);
#728=EDGE_CURVE('E1163',#727,#719,#725,.T.);
#729=ORIENTED_EDGE('',*,*,#728,.F.);
#730=DIRECTION('',(-0.947439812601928,0.,-0.319934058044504));
#731=VECTOR('',#730,1.);
#732=CARTESIAN_POINT('',(0.,0.,-6.65226));
#733=LINE('',#732,#731);
#734=CARTESIAN_POINT('',(0.,0.,-6.65226));
#735=VERTEX_POINT('',#734);
#736=EDGE_CURVE('E1180',#735,#727,#733,.T.);
#737=ORIENTED_EDGE('',*,*,#736,.F.);
#738=DIRECTION('',(-0.947439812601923,0.,0.319934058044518));
#739=VECTOR('',#738,1.);
#740=CARTESIAN_POINT('',(0.916532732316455,0.,-6.96175727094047));
#741=LINE('',#740,#739);
#742=CARTESIAN_POINT('',(0.916532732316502,0.,-6.96175727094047));
#743=VERTEX_POINT('',#742);
#744=EDGE_CURVE('E1192',#743,#735,#741,.T.);
#745=ORIENTED_EDGE('',*,*,#744,.F.);
#746=DIRECTION('',(-0.832351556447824,0.,-0.554248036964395));
#747=VECTOR('',#746,1.);
#748=CARTESIAN_POINT('',(1.72173158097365,0.,-6.42558973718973));
#749=LINE('',#748,#747);
#750=CARTESIAN_POINT('',(1.72173158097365,0.,-6.42558973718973));
#751=VERTEX_POINT('',#750);
#752=EDGE_CURVE('E1209',#751,#743,#749,.T.);
#753=ORIENTED_EDGE('',*,*,#752,.F.);
#754=DIRECTION('',(-0.997961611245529,0.,0.0638171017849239));
#755=VECTOR('',#754,1.);
#756=CARTESIAN_POINT('',(2.6871380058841,0.,-6.48732501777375));
#757=LINE('',#756,#755);
#758=CARTESIAN_POINT('',(2.68713800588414,0.,-6.48732501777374));
#759=VERTEX_POINT('',#758);
#760=EDGE_CURVE('E1221',#759,#751,#757,.T.);
#761=ORIENTED_EDGE('',*,*,#760,.F.);
#762=DIRECTION('',(-0.660539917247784,0.,-0.750790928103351));
#763=VECTOR('',#762,1.);
#764=CARTESIAN_POINT('',(3.32612999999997,0.,-5.76102615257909));
#765=LINE('',#764,#763);
#766=CARTESIAN_POINT('',(3.32612999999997,0.,-5.76102615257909));
#767=VERTEX_POINT('',#766);
#768=EDGE_CURVE('E1238',#767,#759,#765,.T.);
#769=ORIENTED_EDGE('',*,*,#768,.F.);
#770=DIRECTION('',(-0.980473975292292,0.,-0.196648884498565));
#771=VECTOR('',#770,1.);
#772=CARTESIAN_POINT('',(4.27461926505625,0.,-5.57079228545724));
#773=LINE('',#772,#771);
#774=CARTESIAN_POINT('',(4.27461926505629,0.,-5.57079228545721));
#775=VERTEX_POINT('',#774);
#776=EDGE_CURVE('E1250',#775,#767,#773,.T.);
#777=ORIENTED_EDGE('',*,*,#776,.F.);
#778=DIRECTION('',(-0.443713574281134,0.,-0.896168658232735));
#779=VECTOR('',#778,1.);
#780=CARTESIAN_POINT('',(4.703858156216,0.,-4.70385815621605));
#781=LINE('',#780,#779);
#782=CARTESIAN_POINT('',(4.703858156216,0.,-4.70385815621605));
#783=VERTEX_POINT('',#782);
#784=EDGE_CURVE('E1267',#783,#775,#781,.T.);
#785=ORIENTED_EDGE('',*,*,#784,.F.);
#786=DIRECTION('',(-0.89616865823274,0.,-0.443713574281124));
#787=VECTOR('',#786,1.);
#788=CARTESIAN_POINT('',(5.57079228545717,0.,-4.27461926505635));
#789=LINE('',#788,#787);
#790=CARTESIAN_POINT('',(5.5707922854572,0.,-4.27461926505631));
#791=VERTEX_POINT('',#790);
#792=EDGE_CURVE('E1279',#791,#783,#789,.T.);
#793=ORIENTED_EDGE('',*,*,#792,.F.);
#794=DIRECTION('',(-0.196648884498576,0.,-0.98047397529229));
#795=VECTOR('',#794,1.);
#796=CARTESIAN_POINT('',(5.76102615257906,0.,-3.32613000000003));
#797=LINE('',#796,#795);
#798=CARTESIAN_POINT('',(5.76102615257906,0.,-3.32613000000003));
#799=VERTEX_POINT('',#798);
#800=EDGE_CURVE('E1296',#799,#791,#797,.T.);
#801=ORIENTED_EDGE('',*,*,#800,.F.);
#802=DIRECTION('',(-0.750790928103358,0.,-0.660539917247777));
#803=VECTOR('',#802,1.);
#804=CARTESIAN_POINT('',(6.48732501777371,0.,-2.68713800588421));
#805=LINE('',#804,#803);
#806=CARTESIAN_POINT('',(6.48732501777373,0.,-2.68713800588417));
#807=VERTEX_POINT('',#806);
#808=EDGE_CURVE('E1308',#807,#799,#805,.T.);
#809=ORIENTED_EDGE('',*,*,#808,.F.);
#810=DIRECTION('',(0.0638171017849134,0.,-0.99796161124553));
#811=VECTOR('',#810,1.);
#812=CARTESIAN_POINT('',(6.42558973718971,0.,-1.72173158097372));
#813=LINE('',#812,#811);
#814=CARTESIAN_POINT('',(6.42558973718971,0.,-1.72173158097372));
#815=VERTEX_POINT('',#814);
#816=EDGE_CURVE('E1325',#815,#807,#813,.T.);
#817=ORIENTED_EDGE('',*,*,#816,.F.);
#818=DIRECTION('',(-0.554248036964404,0.,-0.832351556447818));
#819=VECTOR('',#818,1.);
#820=CARTESIAN_POINT('',(6.96175727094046,0.,-0.916532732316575));
#821=LINE('',#820,#819);
#822=CARTESIAN_POINT('',(6.96175727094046,0.,-0.916532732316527));
#823=VERTEX_POINT('',#822);
#824=EDGE_CURVE('E1337',#823,#815,#821,.T.);
#825=ORIENTED_EDGE('',*,*,#824,.F.);
#826=DIRECTION('',(0.319934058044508,0.,-0.947439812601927));
#827=VECTOR('',#826,1.);
#828=CARTESIAN_POINT('',(6.65226,0.,0.));
#829=LINE('',#828,#827);
#830=CARTESIAN_POINT('',(6.65226,0.,0.));
#831=VERTEX_POINT('',#830);
#832=EDGE_CURVE('E1354',#831,#823,#829,.T.);
#833=ORIENTED_EDGE('',*,*,#832,.F.);
#834=DIRECTION('',(-0.319934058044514,0.,-0.947439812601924));
#835=VECTOR('',#834,1.);
#836=CARTESIAN_POINT('',(6.96175727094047,0.,0.916532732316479));
#837=LINE('',#836,#835);
#838=CARTESIAN_POINT('',(6.96175727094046,0.,0.916532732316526));
#839=VERTEX_POINT('',#838);
#840=EDGE_CURVE('E1366',#839,#831,#837,.T.);
#841=ORIENTED_EDGE('',*,*,#840,.F.);
#842=DIRECTION('',(0.554248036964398,0.,-0.832351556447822));
#843=VECTOR('',#842,1.);
#844=CARTESIAN_POINT('',(6.42558973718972,0.,1.72173158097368));
#845=LINE('',#844,#843);
#846=CARTESIAN_POINT('',(6.42558973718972,0.,1.72173158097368));
#847=VERTEX_POINT('',#846);
#848=EDGE_CURVE('E1383',#847,#839,#845,.T.);
#849=ORIENTED_EDGE('',*,*,#848,.F.);
#850=DIRECTION('',(-0.0638171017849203,0.,-0.99796161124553));
#851=VECTOR('',#850,1.);
#852=CARTESIAN_POINT('',(6.48732501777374,0.,2.68713800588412));
#853=LINE('',#852,#851);
#854=CARTESIAN_POINT('',(6.48732501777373,0.,2.68713800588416));
#855=VERTEX_POINT('',#854);
#856=EDGE_CURVE('E1395',#855,#847,#853,.T.);
#857=ORIENTED_EDGE('',*,*,#856,.F.);
#858=DIRECTION('',(0.750790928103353,0.,-0.660539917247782));
#859=VECTOR('',#858,1.);
#860=CARTESIAN_POINT('',(5.76102615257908,0.,3.32612999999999));
#861=LINE('',#860,#859);
#862=CARTESIAN_POINT('',(5.76102615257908,0.,3.32612999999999));
#863=VERTEX_POINT('',#862);
#864=EDGE_CURVE('E1412',#863,#855,#861,.T.);
#865=ORIENTED_EDGE('',*,*,#864,.F.);
#866=DIRECTION('',(0.196648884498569,0.,-0.980473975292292));
#867=VECTOR('',#866,1.);
#868=CARTESIAN_POINT('',(5.57079228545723,0.,4.27461926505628));
#869=LINE('',#868,#867);
#870=CARTESIAN_POINT('',(5.5707922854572,0.,4.27461926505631));
#871=VERTEX_POINT('',#870);
#872=EDGE_CURVE('E1424',#871,#863,#869,.T.);
#873=ORIENTED_EDGE('',*,*,#872,.F.);
#874=DIRECTION('',(0.896168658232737,0.,-0.443713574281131));
#875=VECTOR('',#874,1.);
#876=CARTESIAN_POINT('',(4.70385815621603,0.,4.70385815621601));
#877=LINE('',#876,#875);
#878=CARTESIAN_POINT('',(4.70385815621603,0.,4.70385815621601));
#879=VERTEX_POINT('',#878);
#880=EDGE_CURVE('E1441',#879,#871,#877,.T.);
#881=ORIENTED_EDGE('',*,*,#880,.F.);
#882=DIRECTION('',(0.443713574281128,0.,-0.896168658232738));
#883=VECTOR('',#882,1.);
#884=CARTESIAN_POINT('',(4.27461926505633,0.,5.57079228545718));
#885=LINE('',#884,#883);
#886=CARTESIAN_POINT('',(4.27461926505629,0.,5.57079228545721));
#887=VERTEX_POINT('',#886);
#888=EDGE_CURVE('E1453',#887,#879,#885,.T.);
#889=ORIENTED_EDGE('',*,*,#888,.F.);
#890=DIRECTION('',(0.980473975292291,0.,-0.196648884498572));
#891=VECTOR('',#890,1.);
#892=CARTESIAN_POINT('',(3.32613000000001,0.,5.76102615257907));
#893=LINE('',#892,#891);
#894=CARTESIAN_POINT('',(3.32613000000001,0.,5.76102615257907));
#895=VERTEX_POINT('',#894);
#896=EDGE_CURVE('E1470',#895,#887,#893,.T.);
#897=ORIENTED_EDGE('',*,*,#896,.F.);
#898=DIRECTION('',(0.660539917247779,0.,-0.750790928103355));
#899=VECTOR('',#898,1.);
#900=CARTESIAN_POINT('',(2.68713800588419,0.,6.48732501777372));
#901=LINE('',#900,#899);
#902=EDGE_CURVE('E1482',#527,#895,#901,.T.);
#903=ORIENTED_EDGE('',*,*,#902,.F.);
#904=EDGE_LOOP('',(#529,#537,#545,#553,#561,#569,#577,#585,#593,#601,#609,#617,#625,#633,#641,
#649,#657,#665,#673,#681,#689,#697,#705,#713,#721,#729,#737,#745,#753,#761,#769,#777,#785,#793,
#801,#809,#817,#825,#833,#841,#849,#857,#865,#873,#881,#889,#897,#903));
#905=FACE_BOUND('',#904,.T.);
#906=ADVANCED_FACE('F1629',(#519,#905),#110,.T.);
#907=CARTESIAN_POINT('',(0.,0.,0.));
#908=DIRECTION('',(0.,-1.,0.));
#909=DIRECTION('',(0.,0.,-1.));
#910=AXIS2_PLACEMENT_3D('',#907,#908,#909);
#911=CYLINDRICAL_SURFACE('',#910,7.62);
#912=CARTESIAN_POINT('',(0.,2.667,0.));
#913=DIRECTION('',(0.,-1.,0.));
#914=DIRECTION('',(0.,0.,-1.));
#915=AXIS2_PLACEMENT_3D('',#912,#913,#914);
#916=CIRCLE('',#915,7.62);
#917=CARTESIAN_POINT('',(0.,2.667,-7.62));
#918=VERTEX_POINT('',#917);
#919=EDGE_CURVE('E11',#918,#918,#916,.T.);
#920=ORIENTED_EDGE('',*,*,#919,.T.);
#921=EDGE_LOOP('',(#920));
#922=FACE_BOUND('',#921,.T.);
#923=ORIENTED_EDGE('',*,*,#118,.F.);
#924=EDGE_LOOP('',(#923));
#925=FACE_BOUND('',#924,.T.);
#926=ADVANCED_FACE('F37',(#922,#925),#911,.T.);
#927=CARTESIAN_POINT('',(7.62,2.667,0.));
#928=DIRECTION('',(0.,1.,0.));
#929=DIRECTION('',(0.,0.,1.));
#930=AXIS2_PLACEMENT_3D('',#927,#928,#929);
#931=PLANE('',#930);
#932=CARTESIAN_POINT('',(0.,2.667,0.));
#933=DIRECTION('',(0.,-1.,0.));
#934=DIRECTION('',(0.,0.,-1.));
#935=AXIS2_PLACEMENT_3D('',#932,#933,#934);
#936=CIRCLE('',#935,6.477);
#937=CARTESIAN_POINT('',(0.,2.667,-6.477));
#938=VERTEX_POINT('',#937);
#939=EDGE_CURVE('E44',#938,#938,#936,.T.);
#940=ORIENTED_EDGE('',*,*,#939,.T.);
#941=EDGE_LOOP('',(#940));
#942=FACE_BOUND('',#941,.T.);
#943=ORIENTED_EDGE('',*,*,#919,.F.);
#944=EDGE_LOOP('',(#943));
#945=FACE_BOUND('',#944,.T.);
#946=ADVANCED_FACE('F1606',(#942,#945),#931,.T.);
#947=CARTESIAN_POINT('',(0.,0.,0.));
#948=DIRECTION('',(0.,-1.,0.));
#949=DIRECTION('',(0.,0.,-1.));
#950=AXIS2_PLACEMENT_3D('',#947,#948,#949);
#951=CYLINDRICAL_SURFACE('',#950,6.477);
#952=CARTESIAN_POINT('',(0.,3.683,0.));
#953=DIRECTION('',(0.,-1.,0.));
#954=DIRECTION('',(0.,0.,-1.));
#955=AXIS2_PLACEMENT_3D('',#952,#953,#954);
#956=CIRCLE('',#955,6.477);
#957=CARTESIAN_POINT('',(0.,3.683,-6.477));
#958=VERTEX_POINT('',#957);
#959=EDGE_CURVE('E1600',#958,#958,#956,.T.);
#960=ORIENTED_EDGE('',*,*,#959,.T.);
#961=EDGE_LOOP('',(#960));
#962=FACE_BOUND('',#961,.T.);
#963=ORIENTED_EDGE('',*,*,#939,.F.);
#964=EDGE_LOOP('',(#963));
#965=FACE_BOUND('',#964,.T.);
#966=ADVANCED_FACE('F1609',(#962,#965),#951,.T.);
#967=CARTESIAN_POINT('',(0.,3.683,0.));
#968=DIRECTION('',(0.,-1.,0.));
#969=DIRECTION('',(0.,0.,-1.));
#970=AXIS2_PLACEMENT_3D('',#967,#968,#969);
#971=TOROIDAL_SURFACE('',#970,4.826,1.651);
#972=CARTESIAN_POINT('',(0.,5.334,0.));
#973=DIRECTION('',(0.,-1.,0.));
#974=DIRECTION('',(0.,0.,-1.));
#975=AXIS2_PLACEMENT_3D('',#972,#973,#974);
#976=CIRCLE('',#975,4.826);
#977=CARTESIAN_POINT('',(0.,5.334,-4.826));
#978=VERTEX_POINT('',#977);
#979=EDGE_CURVE('E1597',#978,#978,#976,.T.);
#980=ORIENTED_EDGE('',*,*,#979,.T.);
#981=EDGE_LOOP('',(#980));
#982=FACE_BOUND('',#981,.T.);
#983=ORIENTED_EDGE('',*,*,#959,.F.);
#984=EDGE_LOOP('',(#983));
#985=FACE_BOUND('',#984,.T.);
#986=ADVANCED_FACE('F1611',(#982,#985),#971,.T.);
#987=CARTESIAN_POINT('',(4.191,5.334,0.));
#988=DIRECTION('',(0.,1.,0.));
#989=DIRECTION('',(0.,0.,1.));
#990=AXIS2_PLACEMENT_3D('',#987,#988,#989);
#991=PLANE('',#990);
#992=CARTESIAN_POINT('',(0.,5.334,0.));
#993=DIRECTION('',(0.,-1.,0.));
#994=DIRECTION('',(0.,0.,-1.));
#995=AXIS2_PLACEMENT_3D('',#992,#993,#994);
#996=CIRCLE('',#995,4.191);
#997=CARTESIAN_POINT('',(0.,5.334,-4.191));
#998=VERTEX_POINT('',#997);
#999=EDGE_CURVE('E1594',#998,#998,#996,.T.);
#1000=ORIENTED_EDGE('',*,*,#999,.T.);
#1001=EDGE_LOOP('',(#1000));
#1002=FACE_BOUND('',#1001,.T.);
#1003=ORIENTED_EDGE('',*,*,#979,.F.);
#1004=EDGE_LOOP('',(#1003));
#1005=FACE_BOUND('',#1004,.T.);
#1006=ADVANCED_FACE('F1618',(#1002,#1005),#991,.T.);
#1007=CARTESIAN_POINT('',(0.,0.,0.));
#1008=DIRECTION('',(0.,-1.,0.));
#1009=DIRECTION('',(0.,0.,-1.));
#1010=AXIS2_PLACEMENT_3D('',#1007,#1008,#1009);
#1011=CYLINDRICAL_SURFACE('',#1010,4.191);
#1012=CARTESIAN_POINT('',(0.,4.7752,0.));
#1013=DIRECTION('',(0.,-1.,0.));
#1014=DIRECTION('',(0.,0.,-1.));
#1015=AXIS2_PLACEMENT_3D('',#1012,#1013,#1014);
#1016=CIRCLE('',#1015,4.191);
#1017=CARTESIAN_POINT('',(0.,4.7752,-4.191));
#1018=VERTEX_POINT('',#1017);
#1019=EDGE_CURVE('E1591',#1018,#1018,#1016,.T.);
#1020=ORIENTED_EDGE('',*,*,#1019,.T.);
#1021=EDGE_LOOP('',(#1020));
#1022=FACE_BOUND('',#1021,.T.);
#1023=ORIENTED_EDGE('',*,*,#999,.F.);
#1024=EDGE_LOOP('',(#1023));
#1025=FACE_BOUND('',#1024,.T.);
#1026=ADVANCED_FACE('F2960',(#1022,#1025),#1011,.F.);
#1027=CARTESIAN_POINT('',(3.81,4.7752,0.));
#1028=DIRECTION('',(0.,1.,0.));
#1029=DIRECTION('',(0.,0.,1.));
#1030=AXIS2_PLACEMENT_3D('',#1027,#1028,#1029);
#1031=PLANE('',#1030);
#1032=CARTESIAN_POINT('',(0.,4.7752,0.));
#1033=DIRECTION('',(0.,-1.,0.));
#1034=DIRECTION('',(0.,0.,-1.));
#1035=AXIS2_PLACEMENT_3D('',#1032,#1033,#1034);
#1036=CIRCLE('',#1035,3.81);
#1037=CARTESIAN_POINT('',(0.,4.7752,-3.81));
#1038=VERTEX_POINT('',#1037);
#1039=EDGE_CURVE('E1588',#1038,#1038,#1036,.T.);
#1040=ORIENTED_EDGE('',*,*,#1039,.T.);
#1041=EDGE_LOOP('',(#1040));
#1042=FACE_BOUND('',#1041,.T.);
#1043=ORIENTED_EDGE('',*,*,#1019,.F.);
#1044=EDGE_LOOP('',(#1043));
#1045=FACE_BOUND('',#1044,.T.);
#1046=ADVANCED_FACE('F2970',(#1042,#1045),#1031,.T.);
#1047=CARTESIAN_POINT('',(0.,4.7752,0.));
#1048=DIRECTION('',(0.,-1.,0.));
#1049=DIRECTION('',(0.,0.,-1.));
#1050=AXIS2_PLACEMENT_3D('',#1047,#1048,#1049);
#1051=CONICAL_SURFACE('',#1050,3.81,0.0872664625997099);
#1052=CARTESIAN_POINT('',(0.,7.874,0.));
#1053=DIRECTION('',(0.,-1.,0.));
#1054=DIRECTION('',(0.,0.,-1.));
#1055=AXIS2_PLACEMENT_3D('',#1052,#1053,#1054);
#1056=CIRCLE('',#1055,3.53889012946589);
#1057=CARTESIAN_POINT('',(0.,7.874,-3.53889012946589));
#1058=VERTEX_POINT('',#1057);
#1059=EDGE_CURVE('E1585',#1058,#1058,#1056,.T.);
#1060=ORIENTED_EDGE('',*,*,#1059,.T.);
#1061=EDGE_LOOP('',(#1060));
#1062=FACE_BOUND('',#1061,.T.);
#1063=ORIENTED_EDGE('',*,*,#1039,.F.);
#1064=EDGE_LOOP('',(#1063));
#1065=FACE_BOUND('',#1064,.T.);
#1066=ADVANCED_FACE('F2981',(#1062,#1065),#1051,.T.);
#1067=CARTESIAN_POINT('',(3.53889012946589,7.874,0.));
#1068=DIRECTION('',(0.,1.,0.));
#1069=DIRECTION('',(0.,0.,1.));
#1070=AXIS2_PLACEMENT_3D('',#1067,#1068,#1069);
#1071=PLANE('',#1070);
#1072=CARTESIAN_POINT('',(0.,7.874,0.));
#1073=DIRECTION('',(0.,-1.,0.));
#1074=DIRECTION('',(0.,0.,-1.));
#1075=AXIS2_PLACEMENT_3D('',#1072,#1073,#1074);
#1076=CIRCLE('',#1075,3.175);
#1077=CARTESIAN_POINT('',(0.,7.874,-3.175));
#1078=VERTEX_POINT('',#1077);
#1079=EDGE_CURVE('E1561',#1078,#1078,#1076,.T.);
#1080=ORIENTED_EDGE('',*,*,#1079,.T.);
#1081=EDGE_LOOP('',(#1080));
#1082=FACE_BOUND('',#1081,.T.);
#1083=ORIENTED_EDGE('',*,*,#1059,.F.);
#1084=EDGE_LOOP('',(#1083));
#1085=FACE_BOUND('',#1084,.T.);
#1086=ADVANCED_FACE('F1646',(#1082,#1085),#1071,.T.);
#1087=CARTESIAN_POINT('',(0.,0.,0.));
#1088=DIRECTION('',(0.,-1.,0.));
#1089=DIRECTION('',(0.,0.,-1.));
#1090=AXIS2_PLACEMENT_3D('',#1087,#1088,#1089);
#1091=CYLINDRICAL_SURFACE('',#1090,2.5527);
#1092=CARTESIAN_POINT('',(0.,7.43842269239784,0.));
#1093=DIRECTION('',(0.,-1.,0.));
#1094=DIRECTION('',(0.,0.,-1.));
#1095=AXIS2_PLACEMENT_3D('',#1092,#1093,#1094);
#1096=CIRCLE('',#1095,2.5527);
#1097=CARTESIAN_POINT('',(0.,7.43842269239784,-2.5527));
#1098=VERTEX_POINT('',#1097);
#1099=EDGE_CURVE('E1558',#1098,#1098,#1096,.T.);
#1100=ORIENTED_EDGE('',*,*,#1099,.F.);
#1101=EDGE_LOOP('',(#1100));
#1102=FACE_BOUND('',#1101,.T.);
#1103=CARTESIAN_POINT('',(0.,-0.52708269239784,0.));
#1104=DIRECTION('',(0.,-1.,0.));
#1105=DIRECTION('',(0.,0.,-1.));
#1106=AXIS2_PLACEMENT_3D('',#1103,#1104,#1105);
#1107=CIRCLE('',#1106,2.5527);
#1108=CARTESIAN_POINT('',(0.,-0.52708269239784,-2.5527));
#1109=VERTEX_POINT('',#1108);
#1110=EDGE_CURVE('E1567',#1109,#1109,#1107,.T.);
#1111=ORIENTED_EDGE('',*,*,#1110,.T.);
#1112=EDGE_LOOP('',(#1111));
#1113=FACE_BOUND('',#1112,.T.);
#1114=ADVANCED_FACE('F1638',(#1102,#1113),#1091,.F.);
#1115=CARTESIAN_POINT('',(-3.556,-0.9652,-3.556));
#1116=DIRECTION('',(0.,-1.,0.));
#1117=DIRECTION('',(0.,0.,-1.));
#1118=AXIS2_PLACEMENT_3D('',#1115,#1116,#1117);
#1119=CIRCLE('',#1118,0.635);
#1120=CARTESIAN_POINT('',(-4.191,-0.9652,-3.556));
#1121=VERTEX_POINT('',#1120);
#1122=CARTESIAN_POINT('',(-3.556,-0.9652,-4.191));
#1123=VERTEX_POINT('',#1122);
#1124=EDGE_CURVE('E51',#1121,#1123,#1119,.T.);
#1125=ORIENTED_EDGE('',*,*,#1124,.F.);
#1126=DIRECTION('',(0.,0.,-1.));
#1127=VECTOR('',#1126,1.);
#1128=CARTESIAN_POINT('',(-4.191,-0.9652,3.556));
#1129=LINE('',#1128,#1127);
#1130=CARTESIAN_POINT('',(-4.191,-0.9652,3.556));
#1131=VERTEX_POINT('',#1130);
#1132=EDGE_CURVE('E803',#1131,#1121,#1129,.T.);
#1133=ORIENTED_EDGE('',*,*,#1132,.F.);
#1134=CARTESIAN_POINT('',(-3.556,-0.9652,3.556));
#1135=DIRECTION('',(0.,-1.,0.));
#1136=DIRECTION('',(0.,0.,1.));
#1137=AXIS2_PLACEMENT_3D('',#1134,#1135,#1136);
#1138=CIRCLE('',#1137,0.635);
#1139=CARTESIAN_POINT('',(-3.556,-0.9652,4.191));
#1140=VERTEX_POINT('',#1139);
#1141=EDGE_CURVE('E841',#1140,#1131,#1138,.T.);
#1142=ORIENTED_EDGE('',*,*,#1141,.F.);
#1143=DIRECTION('',(-1.,0.,0.));
#1144=VECTOR('',#1143,1.);
#1145=CARTESIAN_POINT('',(3.556,-0.9652,4.191));
#1146=LINE('',#1145,#1144);
#1147=CARTESIAN_POINT('',(3.556,-0.9652,4.191));
#1148=VERTEX_POINT('',#1147);
#1149=EDGE_CURVE('E838',#1148,#1140,#1146,.T.);
#1150=ORIENTED_EDGE('',*,*,#1149,.F.);
#1151=CARTESIAN_POINT('',(3.556,-0.9652,3.556));
#1152=DIRECTION('',(0.,-1.,0.));
#1153=DIRECTION('',(0.,0.,-1.));
#1154=AXIS2_PLACEMENT_3D('',#1151,#1152,#1153);
#1155=CIRCLE('',#1154,0.635000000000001);
#1156=CARTESIAN_POINT('',(4.191,-0.9652,3.556));
#1157=VERTEX_POINT('',#1156);
#1158=EDGE_CURVE('E835',#1157,#1148,#1155,.T.);
#1159=ORIENTED_EDGE('',*,*,#1158,.F.);
#1160=DIRECTION('',(0.,0.,1.));
#1161=VECTOR('',#1160,1.);
#1162=CARTESIAN_POINT('',(4.191,-0.9652,-3.556));
#1163=LINE('',#1162,#1161);
#1164=CARTESIAN_POINT('',(4.191,-0.9652,-3.556));
#1165=VERTEX_POINT('',#1164);
#1166=EDGE_CURVE('E832',#1165,#1157,#1163,.T.);
#1167=ORIENTED_EDGE('',*,*,#1166,.F.);
#1168=CARTESIAN_POINT('',(3.556,-0.9652,-3.556));
#1169=DIRECTION('',(0.,-1.,0.));
#1170=DIRECTION('',(0.,0.,-1.));
#1171=AXIS2_PLACEMENT_3D('',#1168,#1169,#1170);
#1172=CIRCLE('',#1171,0.635);
#1173=CARTESIAN_POINT('',(3.556,-0.9652,-4.191));
#1174=VERTEX_POINT('',#1173);
#1175=EDGE_CURVE('E829',#1174,#1165,#1172,.T.);
#1176=ORIENTED_EDGE('',*,*,#1175,.F.);
#1177=DIRECTION('',(1.,0.,0.));
#1178=VECTOR('',#1177,1.);
#1179=CARTESIAN_POINT('',(-3.556,-0.9652,-4.191));
#1180=LINE('',#1179,#1178);
#1181=EDGE_CURVE('E826',#1123,#1174,#1180,.T.);
#1182=ORIENTED_EDGE('',*,*,#1181,.F.);
#1183=EDGE_LOOP('',(#1125,#1133,#1142,#1150,#1159,#1167,#1176,#1182));
#1184=FACE_BOUND('',#1183,.T.);
#1185=CARTESIAN_POINT('',(0.,-0.9652,0.));
#1186=DIRECTION('',(0.,-1.,0.));
#1187=DIRECTION('',(0.,0.,-1.));
#1188=AXIS2_PLACEMENT_3D('',#1185,#1186,#1187);
#1189=CIRCLE('',#1188,6.5278);
#1190=CARTESIAN_POINT('',(0.,-0.9652,-6.5278));
#1191=VERTEX_POINT('',#1190);
#1192=EDGE_CURVE('E1582',#1191,#1191,#1189,.T.);
#1193=ORIENTED_EDGE('',*,*,#1192,.T.);
#1194=EDGE_LOOP('',(#1193));
#1195=FACE_BOUND('',#1194,.T.);
#1196=ADVANCED_FACE('F1625',(#1184,#1195),#23,.T.);
#1197=CARTESIAN_POINT('',(0.,0.,0.));
#1198=DIRECTION('',(0.,-1.,0.));
#1199=DIRECTION('',(0.,0.,-1.));
#1200=AXIS2_PLACEMENT_3D('',#1197,#1198,#1199);
#1201=CYLINDRICAL_SURFACE('',#1200,6.5278);
#1202=CARTESIAN_POINT('',(0.,-0.77216,0.));
#1203=DIRECTION('',(0.,-1.,0.));
#1204=DIRECTION('',(0.,0.,-1.));
#1205=AXIS2_PLACEMENT_3D('',#1202,#1203,#1204);
#1206=CIRCLE('',#1205,6.5278);
#1207=CARTESIAN_POINT('',(0.,-0.77216,-6.5278));
#1208=VERTEX_POINT('',#1207);
#1209=EDGE_CURVE('E1579',#1208,#1208,#1206,.T.);
#1210=ORIENTED_EDGE('',*,*,#1209,.T.);
#1211=EDGE_LOOP('',(#1210));
#1212=FACE_BOUND('',#1211,.T.);
#1213=ORIENTED_EDGE('',*,*,#1192,.F.);
#1214=EDGE_LOOP('',(#1213));
#1215=FACE_BOUND('',#1214,.T.);
#1216=ADVANCED_FACE('F1637',(#1212,#1215),#1201,.T.);
#1217=CARTESIAN_POINT('',(0.,-0.77216,0.));
#1218=DIRECTION('',(0.,-1.,0.));
#1219=DIRECTION('',(0.,0.,-1.));
#1220=AXIS2_PLACEMENT_3D('',#1217,#1218,#1219);
#1221=CONICAL_SURFACE('',#1220,6.5278,0.523598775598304);
#1222=CARTESIAN_POINT('',(0.,-0.38608,0.));
#1223=DIRECTION('',(0.,-1.,0.));
#1224=DIRECTION('',(0.,0.,-1.));
#1225=AXIS2_PLACEMENT_3D('',#1222,#1223,#1224);
#1226=CIRCLE('',#1225,6.30489660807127);
#1227=CARTESIAN_POINT('',(0.,-0.38608,-6.30489660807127));
#1228=VERTEX_POINT('',#1227);
#1229=EDGE_CURVE('E1576',#1228,#1228,#1226,.T.);
#1230=ORIENTED_EDGE('',*,*,#1229,.T.);
#1231=EDGE_LOOP('',(#1230));
#1232=FACE_BOUND('',#1231,.T.);
#1233=ORIENTED_EDGE('',*,*,#1209,.F.);
#1234=EDGE_LOOP('',(#1233));
#1235=FACE_BOUND('',#1234,.T.);
#1236=ADVANCED_FACE('F1644',(#1232,#1235),#1221,.T.);
#1237=CARTESIAN_POINT('',(0.,0.,0.));
#1238=DIRECTION('',(0.,-1.,0.));
#1239=DIRECTION('',(0.,0.,-1.));
#1240=AXIS2_PLACEMENT_3D('',#1237,#1238,#1239);
#1241=CYLINDRICAL_SURFACE('',#1240,6.30489660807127);
#1242=ORIENTED_EDGE('',*,*,#516,.T.);
#1243=EDGE_LOOP('',(#1242));
#1244=FACE_BOUND('',#1243,.T.);
#1245=ORIENTED_EDGE('',*,*,#1229,.F.);
#1246=EDGE_LOOP('',(#1245));
#1247=FACE_BOUND('',#1246,.T.);
#1248=ADVANCED_FACE('F2091',(#1244,#1247),#1241,.T.);
#1249=CARTESIAN_POINT('',(0.,-0.96266,0.));
#1250=DIRECTION('',(0.,-1.,0.));
#1251=DIRECTION('',(0.,0.,-1.));
#1252=AXIS2_PLACEMENT_3D('',#1249,#1250,#1251);
#1253=CONICAL_SURFACE('',#1252,3.175,0.960105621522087);
#1254=ORIENTED_EDGE('',*,*,#1110,.F.);
#1255=EDGE_LOOP('',(#1254));
#1256=FACE_BOUND('',#1255,.T.);
#1257=CARTESIAN_POINT('',(0.,-0.96266,0.));
#1258=DIRECTION('',(0.,-1.,0.));
#1259=DIRECTION('',(0.,0.,-1.));
#1260=AXIS2_PLACEMENT_3D('',#1257,#1258,#1259);
#1261=CIRCLE('',#1260,3.175);
#1262=CARTESIAN_POINT('',(0.,-0.96266,-3.175));
#1263=VERTEX_POINT('',#1262);
#1264=EDGE_CURVE('E1564',#1263,#1263,#1261,.T.);
#1265=ORIENTED_EDGE('',*,*,#1264,.T.);
#1266=EDGE_LOOP('',(#1265));
#1267=FACE_BOUND('',#1266,.T.);
#1268=ADVANCED_FACE('F2088',(#1256,#1267),#1253,.F.);
#1269=CARTESIAN_POINT('',(0.,-2.54,0.));
#1270=DIRECTION('',(0.,-1.,0.));
#1271=DIRECTION('',(0.,0.,-1.));
#1272=AXIS2_PLACEMENT_3D('',#1269,#1270,#1271);
#1273=CYLINDRICAL_SURFACE('',#1272,3.175);
#1274=ORIENTED_EDGE('',*,*,#31,.T.);
#1275=EDGE_LOOP('',(#1274));
#1276=FACE_BOUND('',#1275,.T.);
#1277=ORIENTED_EDGE('',*,*,#1264,.F.);
#1278=EDGE_LOOP('',(#1277));
#1279=FACE_BOUND('',#1278,.T.);
#1280=ADVANCED_FACE('F2084',(#1276,#1279),#1273,.F.);
#1281=CARTESIAN_POINT('',(0.,7.43842269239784,0.));
#1282=DIRECTION('',(0.,1.,0.));
#1283=DIRECTION('',(0.,0.,1.));
#1284=AXIS2_PLACEMENT_3D('',#1281,#1282,#1283);
#1285=CONICAL_SURFACE('',#1284,2.5527,0.960105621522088);
#1286=ORIENTED_EDGE('',*,*,#1079,.F.);
#1287=EDGE_LOOP('',(#1286));
#1288=FACE_BOUND('',#1287,.T.);
#1289=ORIENTED_EDGE('',*,*,#1099,.T.);
#1290=EDGE_LOOP('',(#1289));
#1291=FACE_BOUND('',#1290,.T.);
#1292=ADVANCED_FACE('F2080',(#1288,#1291),#1285,.F.);
#1293=CARTESIAN_POINT('',(0.944879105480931,-0.38608,7.17706935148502));
#1294=DIRECTION('',(0.31993405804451,0.,-0.947439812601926));
#1295=DIRECTION('',(-0.947439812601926,0.,-0.31993405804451));
#1296=AXIS2_PLACEMENT_3D('',#1293,#1294,#1295);
#1297=PLANE('',#1296);
#1298=ORIENTED_EDGE('',*,*,#130,.T.);
#1299=DIRECTION('',(0.,1.,0.));
#1300=VECTOR('',#1299,1.);
#1301=CARTESIAN_POINT('',(0.,-0.38608,6.858));
#1302=LINE('',#1301,#1300);
#1303=CARTESIAN_POINT('',(0.,-0.38608,6.858));
#1304=VERTEX_POINT('',#1303);
#1305=EDGE_CURVE('E1552',#1304,#129,#1302,.T.);
#1306=ORIENTED_EDGE('',*,*,#1305,.F.);
#1307=DIRECTION('',(-0.947439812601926,0.,-0.31993405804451));
#1308=VECTOR('',#1307,1.);
#1309=CARTESIAN_POINT('',(0.944879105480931,-0.38608,7.17706935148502));
#1310=LINE('',#1309,#1308);
#1311=CARTESIAN_POINT('',(0.94487910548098,-0.38608,7.17706935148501));
#1312=VERTEX_POINT('',#1311);
#1313=EDGE_CURVE('E1523',#1312,#1304,#1310,.T.);
#1314=ORIENTED_EDGE('',*,*,#1313,.F.);
#1315=DIRECTION('',(0.,1.,0.));
#1316=VECTOR('',#1315,1.);
#1317=CARTESIAN_POINT('',(0.944879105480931,-0.38608,7.17706935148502));
#1318=LINE('',#1317,#1316);
#1319=EDGE_CURVE('E1555',#1312,#127,#1318,.T.);
#1320=ORIENTED_EDGE('',*,*,#1319,.T.);
#1321=EDGE_LOOP('',(#1298,#1306,#1314,#1320));
#1322=FACE_BOUND('',#1321,.T.);
#1323=ADVANCED_FACE('F2076',(#1322),#1297,.F.);
#1324=CARTESIAN_POINT('',(0.,-0.38608,6.858));
#1325=DIRECTION('',(-0.31993405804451,0.,-0.947439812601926));
#1326=DIRECTION('',(-0.947439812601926,0.,0.31993405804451));
#1327=AXIS2_PLACEMENT_3D('',#1324,#1325,#1326);
#1328=PLANE('',#1327);
#1329=ORIENTED_EDGE('',*,*,#504,.T.);
#1330=DIRECTION('',(0.,1.,0.));
#1331=VECTOR('',#1330,1.);
#1332=CARTESIAN_POINT('',(-0.944879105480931,-0.38608,7.17706935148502));
#1333=LINE('',#1332,#1331);
#1334=CARTESIAN_POINT('',(-0.94487910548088,-0.38608,7.17706935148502));
#1335=VERTEX_POINT('',#1334);
#1336=EDGE_CURVE('E1550',#1335,#497,#1333,.T.);
#1337=ORIENTED_EDGE('',*,*,#1336,.F.);
#1338=DIRECTION('',(-0.947439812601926,0.,0.31993405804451));
#1339=VECTOR('',#1338,1.);
#1340=CARTESIAN_POINT('',(0.,-0.38608,6.858));
#1341=LINE('',#1340,#1339);
#1342=EDGE_CURVE('E1525',#1304,#1335,#1341,.T.);
#1343=ORIENTED_EDGE('',*,*,#1342,.F.);
#1344=ORIENTED_EDGE('',*,*,#1305,.T.);
#1345=EDGE_LOOP('',(#1329,#1337,#1343,#1344));
#1346=FACE_BOUND('',#1345,.T.);
#1347=ADVANCED_FACE('F2072',(#1346),#1328,.F.);
#1348=CARTESIAN_POINT('',(-0.916532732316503,-0.38608,6.96175727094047));
#1349=DIRECTION('',(0.319934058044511,0.,0.947439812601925));
#1350=DIRECTION('',(0.947439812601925,0.,-0.319934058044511));
#1351=AXIS2_PLACEMENT_3D('',#1348,#1349,#1350);
#1352=PLANE('',#1351);
#1353=ORIENTED_EDGE('',*,*,#552,.T.);
#1354=DIRECTION('',(0.,1.,0.));
#1355=VECTOR('',#1354,1.);
#1356=CARTESIAN_POINT('',(0.,-0.38608,6.65226));
#1357=LINE('',#1356,#1355);
#1358=CARTESIAN_POINT('',(0.,-0.38608,6.65226));
#1359=VERTEX_POINT('',#1358);
#1360=EDGE_CURVE('E1545',#1359,#543,#1357,.T.);
#1361=ORIENTED_EDGE('',*,*,#1360,.F.);
#1362=DIRECTION('',(0.947439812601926,0.,-0.319934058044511));
#1363=VECTOR('',#1362,1.);
#1364=CARTESIAN_POINT('',(-0.916532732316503,-0.38608,6.96175727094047));
#1365=LINE('',#1364,#1363);
#1366=CARTESIAN_POINT('',(-0.916532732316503,-0.38608,6.96175727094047));
#1367=VERTEX_POINT('',#1366);
#1368=EDGE_CURVE('E1529',#1367,#1359,#1365,.T.);
#1369=ORIENTED_EDGE('',*,*,#1368,.F.);
#1370=DIRECTION('',(0.,1.,0.));
#1371=VECTOR('',#1370,1.);
#1372=CARTESIAN_POINT('',(-0.916532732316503,-0.38608,6.96175727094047));
#1373=LINE('',#1372,#1371);
#1374=EDGE_CURVE('E1547',#1367,#551,#1373,.T.);
#1375=ORIENTED_EDGE('',*,*,#1374,.T.);
#1376=EDGE_LOOP('',(#1353,#1361,#1369,#1375));
#1377=FACE_BOUND('',#1376,.T.);
#1378=ADVANCED_FACE('F2068',(#1377),#1352,.F.);
#1379=CARTESIAN_POINT('',(0.,-0.38608,6.65226));
#1380=DIRECTION('',(-0.319934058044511,0.,0.947439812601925));
#1381=DIRECTION('',(0.947439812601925,0.,0.319934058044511));
#1382=AXIS2_PLACEMENT_3D('',#1379,#1380,#1381);
#1383=PLANE('',#1382);
#1384=ORIENTED_EDGE('',*,*,#544,.T.);
#1385=DIRECTION('',(0.,1.,0.));
#1386=VECTOR('',#1385,1.);
#1387=CARTESIAN_POINT('',(0.916532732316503,-0.38608,6.96175727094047));
#1388=LINE('',#1387,#1386);
#1389=CARTESIAN_POINT('',(0.916532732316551,-0.38608,6.96175727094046));
#1390=VERTEX_POINT('',#1389);
#1391=EDGE_CURVE('E1534',#1390,#535,#1388,.T.);
#1392=ORIENTED_EDGE('',*,*,#1391,.F.);
#1393=DIRECTION('',(0.947439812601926,0.,0.319934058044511));
#1394=VECTOR('',#1393,1.);
#1395=CARTESIAN_POINT('',(0.,-0.38608,6.65226));
#1396=LINE('',#1395,#1394);
#1397=EDGE_CURVE('E1531',#1359,#1390,#1396,.T.);
#1398=ORIENTED_EDGE('',*,*,#1397,.F.);
#1399=ORIENTED_EDGE('',*,*,#1360,.T.);
#1400=EDGE_LOOP('',(#1384,#1392,#1398,#1399));
#1401=FACE_BOUND('',#1400,.T.);
#1402=ADVANCED_FACE('F2064',(#1401),#1383,.F.);
#1403=CARTESIAN_POINT('',(0.864442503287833,-0.38608,6.56609269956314));
#1404=DIRECTION('',(0.,-1.,0.));
#1405=DIRECTION('',(0.,0.,-1.));
#1406=AXIS2_PLACEMENT_3D('',#1403,#1404,#1405);
#1407=PLANE('',#1406);
#1408=DIRECTION('',(-0.83235155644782,0.,0.5542480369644));
#1409=VECTOR('',#1408,1.);
#1410=CARTESIAN_POINT('',(1.77498101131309,-0.38608,6.62431931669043));
#1411=LINE('',#1410,#1409);
#1412=CARTESIAN_POINT('',(1.77498101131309,-0.38608,6.62431931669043));
#1413=VERTEX_POINT('',#1412);
#1414=EDGE_CURVE('E1498',#1413,#1312,#1411,.T.);
#1415=ORIENTED_EDGE('',*,*,#1414,.T.);
#1416=ORIENTED_EDGE('',*,*,#1313,.T.);
#1417=ORIENTED_EDGE('',*,*,#1342,.T.);
#1418=DIRECTION('',(-0.832351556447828,0.,-0.554248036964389));
#1419=VECTOR('',#1418,1.);
#1420=CARTESIAN_POINT('',(-0.94487910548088,-0.38608,7.17706935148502));
#1421=LINE('',#1420,#1419);
#1422=CARTESIAN_POINT('',(-1.774981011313,-0.38608,6.62431931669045));
#1423=VERTEX_POINT('',#1422);
#1424=EDGE_CURVE('E862',#1335,#1423,#1421,.T.);
#1425=ORIENTED_EDGE('',*,*,#1424,.T.);
#1426=DIRECTION('',(-0.997961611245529,0.,0.0638171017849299));
#1427=VECTOR('',#1426,1.);
#1428=CARTESIAN_POINT('',(-1.774981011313,-0.38608,6.62431931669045));
#1429=LINE('',#1428,#1427);
#1430=CARTESIAN_POINT('',(-2.77024536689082,-0.38608,6.68796393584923));
#1431=VERTEX_POINT('',#1430);
#1432=EDGE_CURVE('E864',#1423,#1431,#1429,.T.);
#1433=ORIENTED_EDGE('',*,*,#1432,.T.);
#1434=DIRECTION('',(-0.66053991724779,0.,-0.750790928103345));
#1435=VECTOR('',#1434,1.);
#1436=CARTESIAN_POINT('',(-2.77024536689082,-0.38608,6.68796393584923));
#1437=LINE('',#1436,#1435);
#1438=CARTESIAN_POINT('',(-3.42899999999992,-0.38608,5.93920221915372));
#1439=VERTEX_POINT('',#1438);
#1440=EDGE_CURVE('E887',#1431,#1439,#1437,.T.);
#1441=ORIENTED_EDGE('',*,*,#1440,.T.);
#1442=DIRECTION('',(-0.980473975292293,0.,-0.196648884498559));
#1443=VECTOR('',#1442,1.);
#1444=CARTESIAN_POINT('',(-3.42899999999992,-0.38608,5.93920221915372));
#1445=LINE('',#1444,#1443);
#1446=CARTESIAN_POINT('',(-4.40682398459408,-0.38608,5.74308483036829));
#1447=VERTEX_POINT('',#1446);
#1448=EDGE_CURVE('E889',#1439,#1447,#1445,.T.);
#1449=ORIENTED_EDGE('',*,*,#1448,.T.);
#1450=DIRECTION('',(-0.443713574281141,0.,-0.896168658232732));
#1451=VECTOR('',#1450,1.);
#1452=CARTESIAN_POINT('',(-4.40682398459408,-0.38608,5.74308483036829));
#1453=LINE('',#1452,#1451);
#1454=CARTESIAN_POINT('',(-4.84933830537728,-0.38608,4.8493383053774));
#1455=VERTEX_POINT('',#1454);
#1456=EDGE_CURVE('E916',#1447,#1455,#1453,.T.);
#1457=ORIENTED_EDGE('',*,*,#1456,.T.);
#1458=DIRECTION('',(-0.896168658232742,0.,-0.443713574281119));
#1459=VECTOR('',#1458,1.);
#1460=CARTESIAN_POINT('',(-4.84933830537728,-0.38608,4.8493383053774));
#1461=LINE('',#1460,#1459);
#1462=CARTESIAN_POINT('',(-5.74308483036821,-0.38608,4.40682398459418));
#1463=VERTEX_POINT('',#1462);
#1464=EDGE_CURVE('E918',#1455,#1463,#1461,.T.);
#1465=ORIENTED_EDGE('',*,*,#1464,.T.);
#1466=DIRECTION('',(-0.196648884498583,0.,-0.980473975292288));
#1467=VECTOR('',#1466,1.);
#1468=CARTESIAN_POINT('',(-5.74308483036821,-0.38608,4.40682398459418));
#1469=LINE('',#1468,#1467);
#1470=CARTESIAN_POINT('',(-5.93920221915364,-0.38608,3.42900000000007));
#1471=VERTEX_POINT('',#1470);
#1472=EDGE_CURVE('E945',#1463,#1471,#1469,.T.);
#1473=ORIENTED_EDGE('',*,*,#1472,.T.);
#1474=DIRECTION('',(-0.750790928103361,0.,-0.660539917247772));
#1475=VECTOR('',#1474,1.);
#1476=CARTESIAN_POINT('',(-5.93920221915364,-0.38608,3.42900000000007));
#1477=LINE('',#1476,#1475);
#1478=CARTESIAN_POINT('',(-6.68796393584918,-0.38608,2.77024536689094));
#1479=VERTEX_POINT('',#1478);
#1480=EDGE_CURVE('E947',#1471,#1479,#1477,.T.);
#1481=ORIENTED_EDGE('',*,*,#1480,.T.);
#1482=DIRECTION('',(0.0638171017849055,0.,-0.99796161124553));
#1483=VECTOR('',#1482,1.);
#1484=CARTESIAN_POINT('',(-6.68796393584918,-0.38608,2.77024536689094));
#1485=LINE('',#1484,#1483);
#1486=CARTESIAN_POINT('',(-6.62431931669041,-0.38608,1.77498101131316));
#1487=VERTEX_POINT('',#1486);
#1488=EDGE_CURVE('E974',#1479,#1487,#1485,.T.);
#1489=ORIENTED_EDGE('',*,*,#1488,.T.);
#1490=DIRECTION('',(-0.554248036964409,0.,-0.832351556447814));
#1491=VECTOR('',#1490,1.);
#1492=CARTESIAN_POINT('',(-6.62431931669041,-0.38608,1.77498101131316));
#1493=LINE('',#1492,#1491);
#1494=CARTESIAN_POINT('',(-7.17706935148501,-0.38608,0.944879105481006));
#1495=VERTEX_POINT('',#1494);
#1496=EDGE_CURVE('E976',#1487,#1495,#1493,.T.);
#1497=ORIENTED_EDGE('',*,*,#1496,.T.);
#1498=DIRECTION('',(0.3199340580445,0.,-0.947439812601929));
#1499=VECTOR('',#1498,1.);
#1500=CARTESIAN_POINT('',(-7.17706935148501,-0.38608,0.944879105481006));
#1501=LINE('',#1500,#1499);
#1502=CARTESIAN_POINT('',(-6.858,-0.38608,0.));
#1503=VERTEX_POINT('',#1502);
#1504=EDGE_CURVE('E1003',#1495,#1503,#1501,.T.);
#1505=ORIENTED_EDGE('',*,*,#1504,.T.);
#1506=DIRECTION('',(-0.31993405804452,0.,-0.947439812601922));
#1507=VECTOR('',#1506,1.);
#1508=CARTESIAN_POINT('',(-6.858,-0.38608,0.));
#1509=LINE('',#1508,#1507);
#1510=CARTESIAN_POINT('',(-7.17706935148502,-0.38608,-0.944879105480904));
#1511=VERTEX_POINT('',#1510);
#1512=EDGE_CURVE('E1005',#1503,#1511,#1509,.T.);
#1513=ORIENTED_EDGE('',*,*,#1512,.T.);
#1514=DIRECTION('',(0.554248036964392,0.,-0.832351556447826));
#1515=VECTOR('',#1514,1.);
#1516=CARTESIAN_POINT('',(-7.17706935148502,-0.38608,-0.944879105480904));
#1517=LINE('',#1516,#1515);
#1518=CARTESIAN_POINT('',(-6.62431931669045,-0.38608,-1.77498101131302));
#1519=VERTEX_POINT('',#1518);
#1520=EDGE_CURVE('E1032',#1511,#1519,#1517,.T.);
#1521=ORIENTED_EDGE('',*,*,#1520,.T.);
#1522=DIRECTION('',(-0.0638171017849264,0.,-0.997961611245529));
#1523=VECTOR('',#1522,1.);
#1524=CARTESIAN_POINT('',(-6.62431931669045,-0.38608,-1.77498101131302));
#1525=LINE('',#1524,#1523);
#1526=CARTESIAN_POINT('',(-6.68796393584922,-0.38608,-2.77024536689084));
#1527=VERTEX_POINT('',#1526);
#1528=EDGE_CURVE('E1034',#1519,#1527,#1525,.T.);
#1529=ORIENTED_EDGE('',*,*,#1528,.T.);
#1530=DIRECTION('',(0.750790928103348,0.,-0.660539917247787));
#1531=VECTOR('',#1530,1.);
#1532=CARTESIAN_POINT('',(-6.68796393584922,-0.38608,-2.77024536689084));
#1533=LINE('',#1532,#1531);
#1534=CARTESIAN_POINT('',(-5.93920221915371,-0.38608,-3.42899999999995));
#1535=VERTEX_POINT('',#1534);
#1536=EDGE_CURVE('E1061',#1527,#1535,#1533,.T.);
#1537=ORIENTED_EDGE('',*,*,#1536,.T.);
#1538=DIRECTION('',(0.196648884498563,0.,-0.980473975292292));
#1539=VECTOR('',#1538,1.);
#1540=CARTESIAN_POINT('',(-5.93920221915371,-0.38608,-3.42899999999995));
#1541=LINE('',#1540,#1539);
#1542=CARTESIAN_POINT('',(-5.74308483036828,-0.38608,-4.4068239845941));
#1543=VERTEX_POINT('',#1542);
#1544=EDGE_CURVE('E1063',#1535,#1543,#1541,.T.);
#1545=ORIENTED_EDGE('',*,*,#1544,.T.);
#1546=DIRECTION('',(0.896168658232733,0.,-0.443713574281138));
#1547=VECTOR('',#1546,1.);
#1548=CARTESIAN_POINT('',(-5.74308483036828,-0.38608,-4.4068239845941));
#1549=LINE('',#1548,#1547);
#1550=CARTESIAN_POINT('',(-4.84933830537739,-0.38608,-4.8493383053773));
#1551=VERTEX_POINT('',#1550);
#1552=EDGE_CURVE('E1090',#1543,#1551,#1549,.T.);
#1553=ORIENTED_EDGE('',*,*,#1552,.T.);
#1554=DIRECTION('',(0.443713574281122,0.,-0.896168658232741));
#1555=VECTOR('',#1554,1.);
#1556=CARTESIAN_POINT('',(-4.84933830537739,-0.38608,-4.8493383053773));
#1557=LINE('',#1556,#1555);
#1558=CARTESIAN_POINT('',(-4.40682398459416,-0.38608,-5.74308483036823));
#1559=VERTEX_POINT('',#1558);
#1560=EDGE_CURVE('E1092',#1551,#1559,#1557,.T.);
#1561=ORIENTED_EDGE('',*,*,#1560,.T.);
#1562=DIRECTION('',(0.980473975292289,0.,-0.19664888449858));
#1563=VECTOR('',#1562,1.);
#1564=CARTESIAN_POINT('',(-4.40682398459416,-0.38608,-5.74308483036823));
#1565=LINE('',#1564,#1563);
#1566=CARTESIAN_POINT('',(-3.42900000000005,-0.38608,-5.93920221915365));
#1567=VERTEX_POINT('',#1566);
#1568=EDGE_CURVE('E1119',#1559,#1567,#1565,.T.);
#1569=ORIENTED_EDGE('',*,*,#1568,.T.);
#1570=DIRECTION('',(0.660539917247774,0.,-0.750790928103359));
#1571=VECTOR('',#1570,1.);
#1572=CARTESIAN_POINT('',(-3.42900000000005,-0.38608,-5.93920221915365));
#1573=LINE('',#1572,#1571);
#1574=CARTESIAN_POINT('',(-2.77024536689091,-0.38608,-6.68796393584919));
#1575=VERTEX_POINT('',#1574);
#1576=EDGE_CURVE('E1121',#1567,#1575,#1573,.T.);
#1577=ORIENTED_EDGE('',*,*,#1576,.T.);
#1578=DIRECTION('',(0.99796161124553,0.,0.063817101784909));
#1579=VECTOR('',#1578,1.);
#1580=CARTESIAN_POINT('',(-2.77024536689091,-0.38608,-6.68796393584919));
#1581=LINE('',#1580,#1579);
#1582=CARTESIAN_POINT('',(-1.77498101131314,-0.38608,-6.62431931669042));
#1583=VERTEX_POINT('',#1582);
#1584=EDGE_CURVE('E1148',#1575,#1583,#1581,.T.);
#1585=ORIENTED_EDGE('',*,*,#1584,.T.);
#1586=DIRECTION('',(0.832351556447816,0.,-0.554248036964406));
#1587=VECTOR('',#1586,1.);
#1588=CARTESIAN_POINT('',(-1.77498101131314,-0.38608,-6.62431931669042));
#1589=LINE('',#1588,#1587);
#1590=CARTESIAN_POINT('',(-0.944879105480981,-0.38608,-7.17706935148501));
#1591=VERTEX_POINT('',#1590);
#1592=EDGE_CURVE('E1150',#1583,#1591,#1589,.T.);
#1593=ORIENTED_EDGE('',*,*,#1592,.T.);
#1594=DIRECTION('',(0.947439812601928,0.,0.319934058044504));
#1595=VECTOR('',#1594,1.);
#1596=CARTESIAN_POINT('',(-0.944879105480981,-0.38608,-7.17706935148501));
#1597=LINE('',#1596,#1595);
#1598=CARTESIAN_POINT('',(0.,-0.38608,-6.858));
#1599=VERTEX_POINT('',#1598);
#1600=EDGE_CURVE('E1177',#1591,#1599,#1597,.T.);
#1601=ORIENTED_EDGE('',*,*,#1600,.T.);
#1602=DIRECTION('',(0.947439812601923,0.,-0.319934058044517));
#1603=VECTOR('',#1602,1.);
#1604=CARTESIAN_POINT('',(0.,-0.38608,-6.858));
#1605=LINE('',#1604,#1603);
#1606=CARTESIAN_POINT('',(0.94487910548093,-0.38608,-7.17706935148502));
#1607=VERTEX_POINT('',#1606);
#1608=EDGE_CURVE('E1179',#1599,#1607,#1605,.T.);
#1609=ORIENTED_EDGE('',*,*,#1608,.T.);
#1610=DIRECTION('',(0.832351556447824,0.,0.554248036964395));
#1611=VECTOR('',#1610,1.);
#1612=CARTESIAN_POINT('',(0.94487910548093,-0.38608,-7.17706935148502));
#1613=LINE('',#1612,#1611);
#1614=CARTESIAN_POINT('',(1.77498101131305,-0.38608,-6.62431931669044));
#1615=VERTEX_POINT('',#1614);
#1616=EDGE_CURVE('E1206',#1607,#1615,#1613,.T.);
#1617=ORIENTED_EDGE('',*,*,#1616,.T.);
#1618=DIRECTION('',(0.997961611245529,0.,-0.063817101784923));
#1619=VECTOR('',#1618,1.);
#1620=CARTESIAN_POINT('',(1.77498101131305,-0.38608,-6.62431931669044));
#1621=LINE('',#1620,#1619);
#1622=CARTESIAN_POINT('',(2.77024536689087,-0.38608,-6.68796393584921));
#1623=VERTEX_POINT('',#1622);
#1624=EDGE_CURVE('E1208',#1615,#1623,#1621,.T.);
#1625=ORIENTED_EDGE('',*,*,#1624,.T.);
#1626=DIRECTION('',(0.660539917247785,0.,0.75079092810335));
#1627=VECTOR('',#1626,1.);
#1628=CARTESIAN_POINT('',(2.77024536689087,-0.38608,-6.68796393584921));
#1629=LINE('',#1628,#1627);
#1630=CARTESIAN_POINT('',(3.42899999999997,-0.38608,-5.9392022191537));
#1631=VERTEX_POINT('',#1630);
#1632=EDGE_CURVE('E1235',#1623,#1631,#1629,.T.);
#1633=ORIENTED_EDGE('',*,*,#1632,.T.);
#1634=DIRECTION('',(0.980473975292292,0.,0.196648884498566));
#1635=VECTOR('',#1634,1.);
#1636=CARTESIAN_POINT('',(3.42899999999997,-0.38608,-5.9392022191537));
#1637=LINE('',#1636,#1635);
#1638=CARTESIAN_POINT('',(4.40682398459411,-0.38608,-5.74308483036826));
#1639=VERTEX_POINT('',#1638);
#1640=EDGE_CURVE('E1237',#1631,#1639,#1637,.T.);
#1641=ORIENTED_EDGE('',*,*,#1640,.T.);
#1642=DIRECTION('',(0.443713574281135,0.,0.896168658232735));
#1643=VECTOR('',#1642,1.);
#1644=CARTESIAN_POINT('',(4.40682398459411,-0.38608,-5.74308483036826));
#1645=LINE('',#1644,#1643);
#1646=CARTESIAN_POINT('',(4.84933830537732,-0.38608,-4.84933830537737));
#1647=VERTEX_POINT('',#1646);
#1648=EDGE_CURVE('E1264',#1639,#1647,#1645,.T.);
#1649=ORIENTED_EDGE('',*,*,#1648,.T.);
#1650=DIRECTION('',(0.896168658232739,0.,0.443713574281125));
#1651=VECTOR('',#1650,1.);
#1652=CARTESIAN_POINT('',(4.84933830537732,-0.38608,-4.84933830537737));
#1653=LINE('',#1652,#1651);
#1654=CARTESIAN_POINT('',(5.74308483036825,-0.38608,-4.40682398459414));
#1655=VERTEX_POINT('',#1654);
#1656=EDGE_CURVE('E1266',#1647,#1655,#1653,.T.);
#1657=ORIENTED_EDGE('',*,*,#1656,.T.);
#1658=DIRECTION('',(0.196648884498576,0.,0.98047397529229));
#1659=VECTOR('',#1658,1.);
#1660=CARTESIAN_POINT('',(5.74308483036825,-0.38608,-4.40682398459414));
#1661=LINE('',#1660,#1659);
#1662=CARTESIAN_POINT('',(5.93920221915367,-0.38608,-3.42900000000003));
#1663=VERTEX_POINT('',#1662);
#1664=EDGE_CURVE('E1293',#1655,#1663,#1661,.T.);
#1665=ORIENTED_EDGE('',*,*,#1664,.T.);
#1666=DIRECTION('',(0.750790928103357,0.,0.660539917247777));
#1667=VECTOR('',#1666,1.);
#1668=CARTESIAN_POINT('',(5.93920221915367,-0.38608,-3.42900000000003));
#1669=LINE('',#1668,#1667);
#1670=CARTESIAN_POINT('',(6.6879639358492,-0.38608,-2.77024536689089));
#1671=VERTEX_POINT('',#1670);
#1672=EDGE_CURVE('E1295',#1663,#1671,#1669,.T.);
#1673=ORIENTED_EDGE('',*,*,#1672,.T.);
#1674=DIRECTION('',(-0.0638171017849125,0.,0.99796161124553));
#1675=VECTOR('',#1674,1.);
#1676=CARTESIAN_POINT('',(6.6879639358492,-0.38608,-2.77024536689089));
#1677=LINE('',#1676,#1675);
#1678=CARTESIAN_POINT('',(6.62431931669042,-0.38608,-1.77498101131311));
#1679=VERTEX_POINT('',#1678);
#1680=EDGE_CURVE('E1322',#1671,#1679,#1677,.T.);
#1681=ORIENTED_EDGE('',*,*,#1680,.T.);
#1682=DIRECTION('',(0.554248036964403,0.,0.832351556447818));
#1683=VECTOR('',#1682,1.);
#1684=CARTESIAN_POINT('',(6.62431931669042,-0.38608,-1.77498101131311));
#1685=LINE('',#1684,#1683);
#1686=CARTESIAN_POINT('',(7.17706935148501,-0.38608,-0.944879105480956));
#1687=VERTEX_POINT('',#1686);
#1688=EDGE_CURVE('E1324',#1679,#1687,#1685,.T.);
#1689=ORIENTED_EDGE('',*,*,#1688,.T.);
#1690=DIRECTION('',(-0.319934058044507,0.,0.947439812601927));
#1691=VECTOR('',#1690,1.);
#1692=CARTESIAN_POINT('',(7.17706935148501,-0.38608,-0.944879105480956));
#1693=LINE('',#1692,#1691);
#1694=CARTESIAN_POINT('',(6.858,-0.38608,0.));
#1695=VERTEX_POINT('',#1694);
#1696=EDGE_CURVE('E1351',#1687,#1695,#1693,.T.);
#1697=ORIENTED_EDGE('',*,*,#1696,.T.);
#1698=DIRECTION('',(0.319934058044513,0.,0.947439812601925));
#1699=VECTOR('',#1698,1.);
#1700=CARTESIAN_POINT('',(6.858,-0.38608,0.));
#1701=LINE('',#1700,#1699);
#1702=CARTESIAN_POINT('',(7.17706935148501,-0.38608,0.944879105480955));
#1703=VERTEX_POINT('',#1702);
#1704=EDGE_CURVE('E1353',#1695,#1703,#1701,.T.);
#1705=ORIENTED_EDGE('',*,*,#1704,.T.);
#1706=DIRECTION('',(-0.554248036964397,0.,0.832351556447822));
#1707=VECTOR('',#1706,1.);
#1708=CARTESIAN_POINT('',(7.17706935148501,-0.38608,0.944879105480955));
#1709=LINE('',#1708,#1707);
#1710=CARTESIAN_POINT('',(6.62431931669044,-0.38608,1.77498101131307));
#1711=VERTEX_POINT('',#1710);
#1712=EDGE_CURVE('E1380',#1703,#1711,#1709,.T.);
#1713=ORIENTED_EDGE('',*,*,#1712,.T.);
#1714=DIRECTION('',(0.0638171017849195,0.,0.99796161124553));
#1715=VECTOR('',#1714,1.);
#1716=CARTESIAN_POINT('',(6.62431931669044,-0.38608,1.77498101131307));
#1717=LINE('',#1716,#1715);
#1718=CARTESIAN_POINT('',(6.6879639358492,-0.38608,2.77024536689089));
#1719=VERTEX_POINT('',#1718);
#1720=EDGE_CURVE('E1382',#1711,#1719,#1717,.T.);
#1721=ORIENTED_EDGE('',*,*,#1720,.T.);
#1722=DIRECTION('',(-0.750790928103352,0.,0.660539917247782));
#1723=VECTOR('',#1722,1.);
#1724=CARTESIAN_POINT('',(6.6879639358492,-0.38608,2.77024536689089));
#1725=LINE('',#1724,#1723);
#1726=CARTESIAN_POINT('',(5.93920221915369,-0.38608,3.42899999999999));
#1727=VERTEX_POINT('',#1726);
#1728=EDGE_CURVE('E1409',#1719,#1727,#1725,.T.);
#1729=ORIENTED_EDGE('',*,*,#1728,.T.);
#1730=DIRECTION('',(-0.19664888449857,0.,0.980473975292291));
#1731=VECTOR('',#1730,1.);
#1732=CARTESIAN_POINT('',(5.93920221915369,-0.38608,3.42899999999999));
#1733=LINE('',#1732,#1731);
#1734=CARTESIAN_POINT('',(5.74308483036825,-0.38608,4.40682398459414));
#1735=VERTEX_POINT('',#1734);
#1736=EDGE_CURVE('E1411',#1727,#1735,#1733,.T.);
#1737=ORIENTED_EDGE('',*,*,#1736,.T.);
#1738=DIRECTION('',(-0.896168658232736,0.,0.443713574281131));
#1739=VECTOR('',#1738,1.);
#1740=CARTESIAN_POINT('',(5.74308483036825,-0.38608,4.40682398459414));
#1741=LINE('',#1740,#1739);
#1742=CARTESIAN_POINT('',(4.84933830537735,-0.38608,4.84933830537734));
#1743=VERTEX_POINT('',#1742);
#1744=EDGE_CURVE('E1438',#1735,#1743,#1741,.T.);
#1745=ORIENTED_EDGE('',*,*,#1744,.T.);
#1746=DIRECTION('',(-0.443713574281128,0.,0.896168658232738));
#1747=VECTOR('',#1746,1.);
#1748=CARTESIAN_POINT('',(4.84933830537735,-0.38608,4.84933830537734));
#1749=LINE('',#1748,#1747);
#1750=CARTESIAN_POINT('',(4.40682398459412,-0.38608,5.74308483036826));
#1751=VERTEX_POINT('',#1750);
#1752=EDGE_CURVE('E1440',#1743,#1751,#1749,.T.);
#1753=ORIENTED_EDGE('',*,*,#1752,.T.);
#1754=DIRECTION('',(-0.98047397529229,0.,0.196648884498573));
#1755=VECTOR('',#1754,1.);
#1756=CARTESIAN_POINT('',(4.40682398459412,-0.38608,5.74308483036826));
#1757=LINE('',#1756,#1755);
#1758=CARTESIAN_POINT('',(3.42900000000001,-0.38608,5.93920221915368));
#1759=VERTEX_POINT('',#1758);
#1760=EDGE_CURVE('E1467',#1751,#1759,#1757,.T.);
#1761=ORIENTED_EDGE('',*,*,#1760,.T.);
#1762=DIRECTION('',(-0.660539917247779,0.,0.750790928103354));
#1763=VECTOR('',#1762,1.);
#1764=CARTESIAN_POINT('',(3.42900000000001,-0.38608,5.93920221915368));
#1765=LINE('',#1764,#1763);
#1766=CARTESIAN_POINT('',(2.77024536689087,-0.38608,6.68796393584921));
#1767=VERTEX_POINT('',#1766);
#1768=EDGE_CURVE('E1469',#1759,#1767,#1765,.T.);
#1769=ORIENTED_EDGE('',*,*,#1768,.T.);
#1770=DIRECTION('',(-0.99796161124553,0.,-0.063817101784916));
#1771=VECTOR('',#1770,1.);
#1772=CARTESIAN_POINT('',(2.77024536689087,-0.38608,6.68796393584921));
#1773=LINE('',#1772,#1771);
#1774=EDGE_CURVE('E1496',#1767,#1413,#1773,.T.);
#1775=ORIENTED_EDGE('',*,*,#1774,.T.);
#1776=EDGE_LOOP('',(#1415,#1416,#1417,#1425,#1433,#1441,#1449,#1457,#1465,#1473,#1481,#1489,
#1497,#1505,#1513,#1521,#1529,#1537,#1545,#1553,#1561,#1569,#1577,#1585,#1593,#1601,#1609,#1617,
#1625,#1633,#1641,#1649,#1657,#1665,#1673,#1681,#1689,#1697,#1705,#1713,#1721,#1729,#1737,#1745,
#1753,#1761,#1769,#1775));
#1777=FACE_BOUND('',#1776,.T.);
#1778=ORIENTED_EDGE('',*,*,#1397,.T.);
#1779=DIRECTION('',(0.83235155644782,0.,-0.554248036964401));
#1780=VECTOR('',#1779,1.);
#1781=CARTESIAN_POINT('',(0.916532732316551,-0.38608,6.96175727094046));
#1782=LINE('',#1781,#1780);
#1783=CARTESIAN_POINT('',(1.7217315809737,-0.38608,6.42558973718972));
#1784=VERTEX_POINT('',#1783);
#1785=EDGE_CURVE('E1501',#1390,#1784,#1782,.T.);
#1786=ORIENTED_EDGE('',*,*,#1785,.T.);
#1787=DIRECTION('',(0.99796161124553,0.,0.0638171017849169));
#1788=VECTOR('',#1787,1.);
#1789=CARTESIAN_POINT('',(1.7217315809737,-0.38608,6.42558973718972));
#1790=LINE('',#1789,#1788);
#1791=CARTESIAN_POINT('',(2.68713800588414,-0.38608,6.48732501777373));
#1792=VERTEX_POINT('',#1791);
#1793=EDGE_CURVE('E1503',#1784,#1792,#1790,.T.);
#1794=ORIENTED_EDGE('',*,*,#1793,.T.);
#1795=DIRECTION('',(0.660539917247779,0.,-0.750790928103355));
#1796=VECTOR('',#1795,1.);
#1797=CARTESIAN_POINT('',(2.68713800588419,-0.38608,6.48732501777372));
#1798=LINE('',#1797,#1796);
#1799=CARTESIAN_POINT('',(3.32613000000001,-0.38608,5.76102615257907));
#1800=VERTEX_POINT('',#1799);
#1801=EDGE_CURVE('E1473',#1792,#1800,#1798,.T.);
#1802=ORIENTED_EDGE('',*,*,#1801,.T.);
#1803=DIRECTION('',(0.980473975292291,0.,-0.196648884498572));
#1804=VECTOR('',#1803,1.);
#1805=CARTESIAN_POINT('',(3.32613000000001,-0.38608,5.76102615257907));
#1806=LINE('',#1805,#1804);
#1807=CARTESIAN_POINT('',(4.27461926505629,-0.38608,5.57079228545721));
#1808=VERTEX_POINT('',#1807);
#1809=EDGE_CURVE('E1475',#1800,#1808,#1806,.T.);
#1810=ORIENTED_EDGE('',*,*,#1809,.T.);
#1811=DIRECTION('',(0.443713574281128,0.,-0.896168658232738));
#1812=VECTOR('',#1811,1.);
#1813=CARTESIAN_POINT('',(4.27461926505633,-0.38608,5.57079228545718));
#1814=LINE('',#1813,#1812);
#1815=CARTESIAN_POINT('',(4.70385815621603,-0.38608,4.70385815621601));
#1816=VERTEX_POINT('',#1815);
#1817=EDGE_CURVE('E1444',#1808,#1816,#1814,.T.);
#1818=ORIENTED_EDGE('',*,*,#1817,.T.);
#1819=DIRECTION('',(0.896168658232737,0.,-0.443713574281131));
#1820=VECTOR('',#1819,1.);
#1821=CARTESIAN_POINT('',(4.70385815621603,-0.38608,4.70385815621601));
#1822=LINE('',#1821,#1820);
#1823=CARTESIAN_POINT('',(5.5707922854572,-0.38608,4.27461926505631));
#1824=VERTEX_POINT('',#1823);
#1825=EDGE_CURVE('E1446',#1816,#1824,#1822,.T.);
#1826=ORIENTED_EDGE('',*,*,#1825,.T.);
#1827=DIRECTION('',(0.196648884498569,0.,-0.980473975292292));
#1828=VECTOR('',#1827,1.);
#1829=CARTESIAN_POINT('',(5.57079228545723,-0.38608,4.27461926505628));
#1830=LINE('',#1829,#1828);
#1831=CARTESIAN_POINT('',(5.76102615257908,-0.38608,3.32612999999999));
#1832=VERTEX_POINT('',#1831);
#1833=EDGE_CURVE('E1415',#1824,#1832,#1830,.T.);
#1834=ORIENTED_EDGE('',*,*,#1833,.T.);
#1835=DIRECTION('',(0.750790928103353,0.,-0.660539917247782));
#1836=VECTOR('',#1835,1.);
#1837=CARTESIAN_POINT('',(5.76102615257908,-0.38608,3.32612999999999));
#1838=LINE('',#1837,#1836);
#1839=CARTESIAN_POINT('',(6.48732501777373,-0.38608,2.68713800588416));
#1840=VERTEX_POINT('',#1839);
#1841=EDGE_CURVE('E1417',#1832,#1840,#1838,.T.);
#1842=ORIENTED_EDGE('',*,*,#1841,.T.);
#1843=DIRECTION('',(-0.0638171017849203,0.,-0.99796161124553));
#1844=VECTOR('',#1843,1.);
#1845=CARTESIAN_POINT('',(6.48732501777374,-0.38608,2.68713800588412));
#1846=LINE('',#1845,#1844);
#1847=CARTESIAN_POINT('',(6.42558973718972,-0.38608,1.72173158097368));
#1848=VERTEX_POINT('',#1847);
#1849=EDGE_CURVE('E1386',#1840,#1848,#1846,.T.);
#1850=ORIENTED_EDGE('',*,*,#1849,.T.);
#1851=DIRECTION('',(0.554248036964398,0.,-0.832351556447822));
#1852=VECTOR('',#1851,1.);
#1853=CARTESIAN_POINT('',(6.42558973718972,-0.38608,1.72173158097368));
#1854=LINE('',#1853,#1852);
#1855=CARTESIAN_POINT('',(6.96175727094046,-0.38608,0.916532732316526));
#1856=VERTEX_POINT('',#1855);
#1857=EDGE_CURVE('E1388',#1848,#1856,#1854,.T.);
#1858=ORIENTED_EDGE('',*,*,#1857,.T.);
#1859=DIRECTION('',(-0.319934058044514,0.,-0.947439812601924));
#1860=VECTOR('',#1859,1.);
#1861=CARTESIAN_POINT('',(6.96175727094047,-0.38608,0.916532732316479));
#1862=LINE('',#1861,#1860);
#1863=CARTESIAN_POINT('',(6.65226,-0.38608,0.));
#1864=VERTEX_POINT('',#1863);
#1865=EDGE_CURVE('E1357',#1856,#1864,#1862,.T.);
#1866=ORIENTED_EDGE('',*,*,#1865,.T.);
#1867=DIRECTION('',(0.319934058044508,0.,-0.947439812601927));
#1868=VECTOR('',#1867,1.);
#1869=CARTESIAN_POINT('',(6.65226,-0.38608,0.));
#1870=LINE('',#1869,#1868);
#1871=CARTESIAN_POINT('',(6.96175727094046,-0.38608,-0.916532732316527));
#1872=VERTEX_POINT('',#1871);
#1873=EDGE_CURVE('E1359',#1864,#1872,#1870,.T.);
#1874=ORIENTED_EDGE('',*,*,#1873,.T.);
#1875=DIRECTION('',(-0.554248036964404,0.,-0.832351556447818));
#1876=VECTOR('',#1875,1.);
#1877=CARTESIAN_POINT('',(6.96175727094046,-0.38608,-0.916532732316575));
#1878=LINE('',#1877,#1876);
#1879=CARTESIAN_POINT('',(6.42558973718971,-0.38608,-1.72173158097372));
#1880=VERTEX_POINT('',#1879);
#1881=EDGE_CURVE('E1328',#1872,#1880,#1878,.T.);
#1882=ORIENTED_EDGE('',*,*,#1881,.T.);
#1883=DIRECTION('',(0.0638171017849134,0.,-0.99796161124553));
#1884=VECTOR('',#1883,1.);
#1885=CARTESIAN_POINT('',(6.42558973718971,-0.38608,-1.72173158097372));
#1886=LINE('',#1885,#1884);
#1887=CARTESIAN_POINT('',(6.48732501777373,-0.38608,-2.68713800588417));
#1888=VERTEX_POINT('',#1887);
#1889=EDGE_CURVE('E1330',#1880,#1888,#1886,.T.);
#1890=ORIENTED_EDGE('',*,*,#1889,.T.);
#1891=DIRECTION('',(-0.750790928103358,0.,-0.660539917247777));
#1892=VECTOR('',#1891,1.);
#1893=CARTESIAN_POINT('',(6.48732501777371,-0.38608,-2.68713800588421));
#1894=LINE('',#1893,#1892);
#1895=CARTESIAN_POINT('',(5.76102615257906,-0.38608,-3.32613000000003));
#1896=VERTEX_POINT('',#1895);
#1897=EDGE_CURVE('E1299',#1888,#1896,#1894,.T.);
#1898=ORIENTED_EDGE('',*,*,#1897,.T.);
#1899=DIRECTION('',(-0.196648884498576,0.,-0.98047397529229));
#1900=VECTOR('',#1899,1.);
#1901=CARTESIAN_POINT('',(5.76102615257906,-0.38608,-3.32613000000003));
#1902=LINE('',#1901,#1900);
#1903=CARTESIAN_POINT('',(5.5707922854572,-0.38608,-4.27461926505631));
#1904=VERTEX_POINT('',#1903);
#1905=EDGE_CURVE('E1301',#1896,#1904,#1902,.T.);
#1906=ORIENTED_EDGE('',*,*,#1905,.T.);
#1907=DIRECTION('',(-0.89616865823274,0.,-0.443713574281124));
#1908=VECTOR('',#1907,1.);
#1909=CARTESIAN_POINT('',(5.57079228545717,-0.38608,-4.27461926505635));
#1910=LINE('',#1909,#1908);
#1911=CARTESIAN_POINT('',(4.703858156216,-0.38608,-4.70385815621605));
#1912=VERTEX_POINT('',#1911);
#1913=EDGE_CURVE('E1270',#1904,#1912,#1910,.T.);
#1914=ORIENTED_EDGE('',*,*,#1913,.T.);
#1915=DIRECTION('',(-0.443713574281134,0.,-0.896168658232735));
#1916=VECTOR('',#1915,1.);
#1917=CARTESIAN_POINT('',(4.703858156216,-0.38608,-4.70385815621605));
#1918=LINE('',#1917,#1916);
#1919=CARTESIAN_POINT('',(4.27461926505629,-0.38608,-5.57079228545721));
#1920=VERTEX_POINT('',#1919);
#1921=EDGE_CURVE('E1272',#1912,#1920,#1918,.T.);
#1922=ORIENTED_EDGE('',*,*,#1921,.T.);
#1923=DIRECTION('',(-0.980473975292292,0.,-0.196648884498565));
#1924=VECTOR('',#1923,1.);
#1925=CARTESIAN_POINT('',(4.27461926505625,-0.38608,-5.57079228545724));
#1926=LINE('',#1925,#1924);
#1927=CARTESIAN_POINT('',(3.32612999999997,-0.38608,-5.76102615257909));
#1928=VERTEX_POINT('',#1927);
#1929=EDGE_CURVE('E1241',#1920,#1928,#1926,.T.);
#1930=ORIENTED_EDGE('',*,*,#1929,.T.);
#1931=DIRECTION('',(-0.660539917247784,0.,-0.750790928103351));
#1932=VECTOR('',#1931,1.);
#1933=CARTESIAN_POINT('',(3.32612999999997,-0.38608,-5.76102615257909));
#1934=LINE('',#1933,#1932);
#1935=CARTESIAN_POINT('',(2.68713800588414,-0.38608,-6.48732501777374));
#1936=VERTEX_POINT('',#1935);
#1937=EDGE_CURVE('E1243',#1928,#1936,#1934,.T.);
#1938=ORIENTED_EDGE('',*,*,#1937,.T.);
#1939=DIRECTION('',(-0.997961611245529,0.,0.0638171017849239));
#1940=VECTOR('',#1939,1.);
#1941=CARTESIAN_POINT('',(2.6871380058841,-0.38608,-6.48732501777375));
#1942=LINE('',#1941,#1940);
#1943=CARTESIAN_POINT('',(1.72173158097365,-0.38608,-6.42558973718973));
#1944=VERTEX_POINT('',#1943);
#1945=EDGE_CURVE('E1212',#1936,#1944,#1942,.T.);
#1946=ORIENTED_EDGE('',*,*,#1945,.T.);
#1947=DIRECTION('',(-0.832351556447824,0.,-0.554248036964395));
#1948=VECTOR('',#1947,1.);
#1949=CARTESIAN_POINT('',(1.72173158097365,-0.38608,-6.42558973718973));
#1950=LINE('',#1949,#1948);
#1951=CARTESIAN_POINT('',(0.916532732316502,-0.38608,-6.96175727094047));
#1952=VERTEX_POINT('',#1951);
#1953=EDGE_CURVE('E1214',#1944,#1952,#1950,.T.);
#1954=ORIENTED_EDGE('',*,*,#1953,.T.);
#1955=DIRECTION('',(-0.947439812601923,0.,0.319934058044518));
#1956=VECTOR('',#1955,1.);
#1957=CARTESIAN_POINT('',(0.916532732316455,-0.38608,-6.96175727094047));
#1958=LINE('',#1957,#1956);
#1959=CARTESIAN_POINT('',(0.,-0.38608,-6.65226));
#1960=VERTEX_POINT('',#1959);
#1961=EDGE_CURVE('E1183',#1952,#1960,#1958,.T.);
#1962=ORIENTED_EDGE('',*,*,#1961,.T.);
#1963=DIRECTION('',(-0.947439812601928,0.,-0.319934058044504));
#1964=VECTOR('',#1963,1.);
#1965=CARTESIAN_POINT('',(0.,-0.38608,-6.65226));
#1966=LINE('',#1965,#1964);
#1967=CARTESIAN_POINT('',(-0.916532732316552,-0.38608,-6.96175727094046));
#1968=VERTEX_POINT('',#1967);
#1969=EDGE_CURVE('E1185',#1960,#1968,#1966,.T.);
#1970=ORIENTED_EDGE('',*,*,#1969,.T.);
#1971=DIRECTION('',(-0.832351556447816,0.,0.554248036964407));
#1972=VECTOR('',#1971,1.);
#1973=CARTESIAN_POINT('',(-0.916532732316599,-0.38608,-6.96175727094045));
#1974=LINE('',#1973,#1972);
#1975=CARTESIAN_POINT('',(-1.72173158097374,-0.38608,-6.4255897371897));
#1976=VERTEX_POINT('',#1975);
#1977=EDGE_CURVE('E1154',#1968,#1976,#1974,.T.);
#1978=ORIENTED_EDGE('',*,*,#1977,.T.);
#1979=DIRECTION('',(-0.99796161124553,0.,-0.0638171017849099));
#1980=VECTOR('',#1979,1.);
#1981=CARTESIAN_POINT('',(-1.72173158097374,-0.38608,-6.4255897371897));
#1982=LINE('',#1981,#1980);
#1983=CARTESIAN_POINT('',(-2.68713800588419,-0.38608,-6.48732501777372));
#1984=VERTEX_POINT('',#1983);
#1985=EDGE_CURVE('E1156',#1976,#1984,#1982,.T.);
#1986=ORIENTED_EDGE('',*,*,#1985,.T.);
#1987=DIRECTION('',(-0.660539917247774,0.,0.75079092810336));
#1988=VECTOR('',#1987,1.);
#1989=CARTESIAN_POINT('',(-2.68713800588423,-0.38608,-6.4873250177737));
#1990=LINE('',#1989,#1988);
#1991=CARTESIAN_POINT('',(-3.32613000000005,-0.38608,-5.76102615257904));
#1992=VERTEX_POINT('',#1991);
#1993=EDGE_CURVE('E1125',#1984,#1992,#1990,.T.);
#1994=ORIENTED_EDGE('',*,*,#1993,.T.);
#1995=DIRECTION('',(-0.980473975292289,0.,0.196648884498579));
#1996=VECTOR('',#1995,1.);
#1997=CARTESIAN_POINT('',(-3.32613000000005,-0.38608,-5.76102615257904));
#1998=LINE('',#1997,#1996);
#1999=CARTESIAN_POINT('',(-4.27461926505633,-0.38608,-5.57079228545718));
#2000=VERTEX_POINT('',#1999);
#2001=EDGE_CURVE('E1127',#1992,#2000,#1998,.T.);
#2002=ORIENTED_EDGE('',*,*,#2001,.T.);
#2003=DIRECTION('',(-0.443713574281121,0.,0.896168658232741));
#2004=VECTOR('',#2003,1.);
#2005=CARTESIAN_POINT('',(-4.27461926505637,-0.38608,-5.57079228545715));
#2006=LINE('',#2005,#2004);
#2007=CARTESIAN_POINT('',(-4.70385815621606,-0.38608,-4.70385815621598));
#2008=VERTEX_POINT('',#2007);
#2009=EDGE_CURVE('E1096',#2000,#2008,#2006,.T.);
#2010=ORIENTED_EDGE('',*,*,#2009,.T.);
#2011=DIRECTION('',(-0.896168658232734,0.,0.443713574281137));
#2012=VECTOR('',#2011,1.);
#2013=CARTESIAN_POINT('',(-4.70385815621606,-0.38608,-4.70385815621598));
#2014=LINE('',#2013,#2012);
#2015=CARTESIAN_POINT('',(-5.57079228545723,-0.38608,-4.27461926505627));
#2016=VERTEX_POINT('',#2015);
#2017=EDGE_CURVE('E1098',#2008,#2016,#2014,.T.);
#2018=ORIENTED_EDGE('',*,*,#2017,.T.);
#2019=DIRECTION('',(-0.196648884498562,0.,0.980473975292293));
#2020=VECTOR('',#2019,1.);
#2021=CARTESIAN_POINT('',(-5.57079228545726,-0.38608,-4.27461926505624));
#2022=LINE('',#2021,#2020);
#2023=CARTESIAN_POINT('',(-5.7610261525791,-0.38608,-3.32612999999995));
#2024=VERTEX_POINT('',#2023);
#2025=EDGE_CURVE('E1067',#2016,#2024,#2022,.T.);
#2026=ORIENTED_EDGE('',*,*,#2025,.T.);
#2027=DIRECTION('',(-0.750790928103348,0.,0.660539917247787));
#2028=VECTOR('',#2027,1.);
#2029=CARTESIAN_POINT('',(-5.7610261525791,-0.38608,-3.32612999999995));
#2030=LINE('',#2029,#2028);
#2031=CARTESIAN_POINT('',(-6.48732501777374,-0.38608,-2.68713800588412));
#2032=VERTEX_POINT('',#2031);
#2033=EDGE_CURVE('E1069',#2024,#2032,#2030,.T.);
#2034=ORIENTED_EDGE('',*,*,#2033,.T.);
#2035=DIRECTION('',(0.0638171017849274,0.,0.997961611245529));
#2036=VECTOR('',#2035,1.);
#2037=CARTESIAN_POINT('',(-6.48732501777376,-0.38608,-2.68713800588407));
#2038=LINE('',#2037,#2036);
#2039=CARTESIAN_POINT('',(-6.42558973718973,-0.38608,-1.72173158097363));
#2040=VERTEX_POINT('',#2039);
#2041=EDGE_CURVE('E1038',#2032,#2040,#2038,.T.);
#2042=ORIENTED_EDGE('',*,*,#2041,.T.);
#2043=DIRECTION('',(-0.554248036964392,0.,0.832351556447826));
#2044=VECTOR('',#2043,1.);
#2045=CARTESIAN_POINT('',(-6.42558973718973,-0.38608,-1.72173158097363));
#2046=LINE('',#2045,#2044);
#2047=CARTESIAN_POINT('',(-6.96175727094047,-0.38608,-0.916532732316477));
#2048=VERTEX_POINT('',#2047);
#2049=EDGE_CURVE('E1040',#2040,#2048,#2046,.T.);
#2050=ORIENTED_EDGE('',*,*,#2049,.T.);
#2051=DIRECTION('',(0.319934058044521,0.,0.947439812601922));
#2052=VECTOR('',#2051,1.);
#2053=CARTESIAN_POINT('',(-6.96175727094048,-0.38608,-0.91653273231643));
#2054=LINE('',#2053,#2052);
#2055=CARTESIAN_POINT('',(-6.65226,-0.38608,0.));
#2056=VERTEX_POINT('',#2055);
#2057=EDGE_CURVE('E1009',#2048,#2056,#2054,.T.);
#2058=ORIENTED_EDGE('',*,*,#2057,.T.);
#2059=DIRECTION('',(-0.319934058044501,0.,0.947439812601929));
#2060=VECTOR('',#2059,1.);
#2061=CARTESIAN_POINT('',(-6.65226,-0.38608,0.));
#2062=LINE('',#2061,#2060);
#2063=CARTESIAN_POINT('',(-6.96175727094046,-0.38608,0.916532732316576));
#2064=VERTEX_POINT('',#2063);
#2065=EDGE_CURVE('E1011',#2056,#2064,#2062,.T.);
#2066=ORIENTED_EDGE('',*,*,#2065,.T.);
#2067=DIRECTION('',(0.55424803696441,0.,0.832351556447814));
#2068=VECTOR('',#2067,1.);
#2069=CARTESIAN_POINT('',(-6.96175727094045,-0.38608,0.916532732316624));
#2070=LINE('',#2069,#2068);
#2071=CARTESIAN_POINT('',(-6.4255897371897,-0.38608,1.72173158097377));
#2072=VERTEX_POINT('',#2071);
#2073=EDGE_CURVE('E980',#2064,#2072,#2070,.T.);
#2074=ORIENTED_EDGE('',*,*,#2073,.T.);
#2075=DIRECTION('',(-0.0638171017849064,0.,0.99796161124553));
#2076=VECTOR('',#2075,1.);
#2077=CARTESIAN_POINT('',(-6.4255897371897,-0.38608,1.72173158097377));
#2078=LINE('',#2077,#2076);
#2079=CARTESIAN_POINT('',(-6.48732501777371,-0.38608,2.68713800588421));
#2080=VERTEX_POINT('',#2079);
#2081=EDGE_CURVE('E982',#2072,#2080,#2078,.T.);
#2082=ORIENTED_EDGE('',*,*,#2081,.T.);
#2083=DIRECTION('',(0.750790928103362,0.,0.660539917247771));
#2084=VECTOR('',#2083,1.);
#2085=CARTESIAN_POINT('',(-6.48732501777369,-0.38608,2.68713800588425));
#2086=LINE('',#2085,#2084);
#2087=CARTESIAN_POINT('',(-5.76102615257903,-0.38608,3.32613000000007));
#2088=VERTEX_POINT('',#2087);
#2089=EDGE_CURVE('E951',#2080,#2088,#2086,.T.);
#2090=ORIENTED_EDGE('',*,*,#2089,.T.);
#2091=DIRECTION('',(0.196648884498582,0.,0.980473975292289));
#2092=VECTOR('',#2091,1.);
#2093=CARTESIAN_POINT('',(-5.76102615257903,-0.38608,3.32613000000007));
#2094=LINE('',#2093,#2092);
#2095=CARTESIAN_POINT('',(-5.57079228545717,-0.38608,4.27461926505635));
#2096=VERTEX_POINT('',#2095);
#2097=EDGE_CURVE('E953',#2088,#2096,#2094,.T.);
#2098=ORIENTED_EDGE('',*,*,#2097,.T.);
#2099=DIRECTION('',(0.896168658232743,0.,0.443713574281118));
#2100=VECTOR('',#2099,1.);
#2101=CARTESIAN_POINT('',(-5.57079228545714,-0.38608,4.27461926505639));
#2102=LINE('',#2101,#2100);
#2103=CARTESIAN_POINT('',(-4.70385815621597,-0.38608,4.70385815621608));
#2104=VERTEX_POINT('',#2103);
#2105=EDGE_CURVE('E922',#2096,#2104,#2102,.T.);
#2106=ORIENTED_EDGE('',*,*,#2105,.T.);
#2107=DIRECTION('',(0.44371357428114,0.,0.896168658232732));
#2108=VECTOR('',#2107,1.);
#2109=CARTESIAN_POINT('',(-4.70385815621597,-0.38608,4.70385815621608));
#2110=LINE('',#2109,#2108);
#2111=CARTESIAN_POINT('',(-4.27461926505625,-0.38608,5.57079228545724));
#2112=VERTEX_POINT('',#2111);
#2113=EDGE_CURVE('E924',#2104,#2112,#2110,.T.);
#2114=ORIENTED_EDGE('',*,*,#2113,.T.);
#2115=DIRECTION('',(0.980473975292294,0.,0.196648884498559));
#2116=VECTOR('',#2115,1.);
#2117=CARTESIAN_POINT('',(-4.27461926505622,-0.38608,5.57079228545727));
#2118=LINE('',#2117,#2116);
#2119=CARTESIAN_POINT('',(-3.32612999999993,-0.38608,5.76102615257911));
#2120=VERTEX_POINT('',#2119);
#2121=EDGE_CURVE('E893',#2112,#2120,#2118,.T.);
#2122=ORIENTED_EDGE('',*,*,#2121,.T.);
#2123=DIRECTION('',(0.660539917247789,0.,0.750790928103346));
#2124=VECTOR('',#2123,1.);
#2125=CARTESIAN_POINT('',(-3.32612999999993,-0.38608,5.76102615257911));
#2126=LINE('',#2125,#2124);
#2127=CARTESIAN_POINT('',(-2.6871380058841,-0.38608,6.48732501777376));
#2128=VERTEX_POINT('',#2127);
#2129=EDGE_CURVE('E895',#2120,#2128,#2126,.T.);
#2130=ORIENTED_EDGE('',*,*,#2129,.T.);
#2131=DIRECTION('',(0.997961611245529,0.,-0.0638171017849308));
#2132=VECTOR('',#2131,1.);
#2133=CARTESIAN_POINT('',(-2.68713800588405,-0.38608,6.48732501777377));
#2134=LINE('',#2133,#2132);
#2135=CARTESIAN_POINT('',(-1.72173158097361,-0.38608,6.42558973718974));
#2136=VERTEX_POINT('',#2135);
#2137=EDGE_CURVE('E868',#2128,#2136,#2134,.T.);
#2138=ORIENTED_EDGE('',*,*,#2137,.T.);
#2139=DIRECTION('',(0.832351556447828,0.,0.55424803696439));
#2140=VECTOR('',#2139,1.);
#2141=CARTESIAN_POINT('',(-1.72173158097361,-0.38608,6.42558973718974));
#2142=LINE('',#2141,#2140);
#2143=EDGE_CURVE('E870',#2136,#1367,#2142,.T.);
#2144=ORIENTED_EDGE('',*,*,#2143,.T.);
#2145=ORIENTED_EDGE('',*,*,#1368,.T.);
#2146=EDGE_LOOP('',(#1778,#1786,#1794,#1802,#1810,#1818,#1826,#1834,#1842,#1850,#1858,#1866,
#1874,#1882,#1890,#1898,#1906,#1914,#1922,#1930,#1938,#1946,#1954,#1962,#1970,#1978,#1986,#1994,
#2002,#2010,#2018,#2026,#2034,#2042,#2050,#2058,#2066,#2074,#2082,#2090,#2098,#2106,#2114,#2122,
#2130,#2138,#2144,#2145));
#2147=FACE_BOUND('',#2146,.T.);
#2148=ADVANCED_FACE('F2060',(#1777,#2147),#1407,.T.);
#2149=CARTESIAN_POINT('',(2.77024536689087,-0.38608,6.68796393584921));
#2150=DIRECTION('',(0.063817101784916,0.,-0.99796161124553));
#2151=DIRECTION('',(-0.99796161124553,0.,-0.063817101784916));
#2152=AXIS2_PLACEMENT_3D('',#2149,#2150,#2151);
#2153=PLANE('',#2152);
#2154=ORIENTED_EDGE('',*,*,#146,.T.);
#2155=DIRECTION('',(0.,1.,0.));
#2156=VECTOR('',#2155,1.);
#2157=CARTESIAN_POINT('',(1.77498101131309,-0.38608,6.62431931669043));
#2158=LINE('',#2157,#2156);
#2159=EDGE_CURVE('E1517',#1413,#137,#2158,.T.);
#2160=ORIENTED_EDGE('',*,*,#2159,.F.);
#2161=ORIENTED_EDGE('',*,*,#1774,.F.);
#2162=DIRECTION('',(0.,1.,0.));
#2163=VECTOR('',#2162,1.);
#2164=CARTESIAN_POINT('',(2.77024536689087,-0.38608,6.68796393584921));
#2165=LINE('',#2164,#2163);
#2166=EDGE_CURVE('E1520',#1767,#145,#2165,.T.);
#2167=ORIENTED_EDGE('',*,*,#2166,.T.);
#2168=EDGE_LOOP('',(#2154,#2160,#2161,#2167));
#2169=FACE_BOUND('',#2168,.T.);
#2170=ADVANCED_FACE('F2056',(#2169),#2153,.F.);
#2171=CARTESIAN_POINT('',(1.77498101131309,-0.38608,6.62431931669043));
#2172=DIRECTION('',(-0.5542480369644,0.,-0.83235155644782));
#2173=DIRECTION('',(-0.83235155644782,0.,0.5542480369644));
#2174=AXIS2_PLACEMENT_3D('',#2171,#2172,#2173);
#2175=PLANE('',#2174);
#2176=ORIENTED_EDGE('',*,*,#138,.T.);
#2177=ORIENTED_EDGE('',*,*,#1319,.F.);
#2178=ORIENTED_EDGE('',*,*,#1414,.F.);
#2179=ORIENTED_EDGE('',*,*,#2159,.T.);
#2180=EDGE_LOOP('',(#2176,#2177,#2178,#2179));
#2181=FACE_BOUND('',#2180,.T.);
#2182=ADVANCED_FACE('F2052',(#2181),#2175,.F.);
#2183=CARTESIAN_POINT('',(0.916532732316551,-0.38608,6.96175727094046));
#2184=DIRECTION('',(0.554248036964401,0.,0.83235155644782));
#2185=DIRECTION('',(0.83235155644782,0.,-0.554248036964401));
#2186=AXIS2_PLACEMENT_3D('',#2183,#2184,#2185);
#2187=PLANE('',#2186);
#2188=ORIENTED_EDGE('',*,*,#536,.T.);
#2189=DIRECTION('',(0.,1.,0.));
#2190=VECTOR('',#2189,1.);
#2191=CARTESIAN_POINT('',(1.7217315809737,-0.38608,6.42558973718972));
#2192=LINE('',#2191,#2190);
#2193=EDGE_CURVE('E1514',#1784,#525,#2192,.T.);
#2194=ORIENTED_EDGE('',*,*,#2193,.F.);
#2195=ORIENTED_EDGE('',*,*,#1785,.F.);
#2196=ORIENTED_EDGE('',*,*,#1391,.T.);
#2197=EDGE_LOOP('',(#2188,#2194,#2195,#2196));
#2198=FACE_BOUND('',#2197,.T.);
#2199=ADVANCED_FACE('F2048',(#2198),#2187,.F.);
#2200=CARTESIAN_POINT('',(1.7217315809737,-0.38608,6.42558973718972));
#2201=DIRECTION('',(-0.0638171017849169,0.,0.99796161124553));
#2202=DIRECTION('',(0.99796161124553,0.,0.0638171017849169));
#2203=AXIS2_PLACEMENT_3D('',#2200,#2201,#2202);
#2204=PLANE('',#2203);
#2205=ORIENTED_EDGE('',*,*,#528,.T.);
#2206=DIRECTION('',(0.,1.,0.));
#2207=VECTOR('',#2206,1.);
#2208=CARTESIAN_POINT('',(2.68713800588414,-0.38608,6.48732501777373));
#2209=LINE('',#2208,#2207);
#2210=EDGE_CURVE('E1505',#1792,#527,#2209,.T.);
#2211=ORIENTED_EDGE('',*,*,#2210,.F.);
#2212=ORIENTED_EDGE('',*,*,#1793,.F.);
#2213=ORIENTED_EDGE('',*,*,#2193,.T.);
#2214=EDGE_LOOP('',(#2205,#2211,#2212,#2213));
#2215=FACE_BOUND('',#2214,.T.);
#2216=ADVANCED_FACE('F2044',(#2215),#2204,.F.);
#2217=CARTESIAN_POINT('',(4.40682398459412,-0.38608,5.74308483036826));
#2218=DIRECTION('',(-0.196648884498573,0.,-0.980473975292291));
#2219=DIRECTION('',(-0.980473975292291,0.,0.196648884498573));
#2220=AXIS2_PLACEMENT_3D('',#2217,#2218,#2219);
#2221=PLANE('',#2220);
#2222=ORIENTED_EDGE('',*,*,#162,.T.);
#2223=DIRECTION('',(0.,1.,0.));
#2224=VECTOR('',#2223,1.);
#2225=CARTESIAN_POINT('',(3.42900000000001,-0.38608,5.93920221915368));
#2226=LINE('',#2225,#2224);
#2227=EDGE_CURVE('E1490',#1759,#153,#2226,.T.);
#2228=ORIENTED_EDGE('',*,*,#2227,.F.);
#2229=ORIENTED_EDGE('',*,*,#1760,.F.);
#2230=DIRECTION('',(0.,1.,0.));
#2231=VECTOR('',#2230,1.);
#2232=CARTESIAN_POINT('',(4.40682398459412,-0.38608,5.74308483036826));
#2233=LINE('',#2232,#2231);
#2234=EDGE_CURVE('E1493',#1751,#161,#2233,.T.);
#2235=ORIENTED_EDGE('',*,*,#2234,.T.);
#2236=EDGE_LOOP('',(#2222,#2228,#2229,#2235));
#2237=FACE_BOUND('',#2236,.T.);
#2238=ADVANCED_FACE('F2040',(#2237),#2221,.F.);
#2239=CARTESIAN_POINT('',(3.42900000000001,-0.38608,5.93920221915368));
#2240=DIRECTION('',(-0.750790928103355,0.,-0.66053991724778));
#2241=DIRECTION('',(-0.66053991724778,0.,0.750790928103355));
#2242=AXIS2_PLACEMENT_3D('',#2239,#2240,#2241);
#2243=PLANE('',#2242);
#2244=ORIENTED_EDGE('',*,*,#154,.T.);
#2245=ORIENTED_EDGE('',*,*,#2166,.F.);
#2246=ORIENTED_EDGE('',*,*,#1768,.F.);
#2247=ORIENTED_EDGE('',*,*,#2227,.T.);
#2248=EDGE_LOOP('',(#2244,#2245,#2246,#2247));
#2249=FACE_BOUND('',#2248,.T.);
#2250=ADVANCED_FACE('F2036',(#2249),#2243,.F.);
#2251=CARTESIAN_POINT('',(2.68713800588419,-0.38608,6.48732501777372));
#2252=DIRECTION('',(0.750790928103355,0.,0.660539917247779));
#2253=DIRECTION('',(0.660539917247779,0.,-0.750790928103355));
#2254=AXIS2_PLACEMENT_3D('',#2251,#2252,#2253);
#2255=PLANE('',#2254);
#2256=ORIENTED_EDGE('',*,*,#902,.T.);
#2257=DIRECTION('',(0.,1.,0.));
#2258=VECTOR('',#2257,1.);
#2259=CARTESIAN_POINT('',(3.32613000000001,-0.38608,5.76102615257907));
#2260=LINE('',#2259,#2258);
#2261=EDGE_CURVE('E1487',#1800,#895,#2260,.T.);
#2262=ORIENTED_EDGE('',*,*,#2261,.F.);
#2263=ORIENTED_EDGE('',*,*,#1801,.F.);
#2264=ORIENTED_EDGE('',*,*,#2210,.T.);
#2265=EDGE_LOOP('',(#2256,#2262,#2263,#2264));
#2266=FACE_BOUND('',#2265,.T.);
#2267=ADVANCED_FACE('F2032',(#2266),#2255,.F.);
#2268=CARTESIAN_POINT('',(3.32613000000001,-0.38608,5.76102615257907));
#2269=DIRECTION('',(0.196648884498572,0.,0.980473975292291));
#2270=DIRECTION('',(0.980473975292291,0.,-0.196648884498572));
#2271=AXIS2_PLACEMENT_3D('',#2268,#2269,#2270);
#2272=PLANE('',#2271);
#2273=ORIENTED_EDGE('',*,*,#896,.T.);
#2274=DIRECTION('',(0.,1.,0.));
#2275=VECTOR('',#2274,1.);
#2276=CARTESIAN_POINT('',(4.27461926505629,-0.38608,5.57079228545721));
#2277=LINE('',#2276,#2275);
#2278=EDGE_CURVE('E1477',#1808,#887,#2277,.T.);
#2279=ORIENTED_EDGE('',*,*,#2278,.F.);
#2280=ORIENTED_EDGE('',*,*,#1809,.F.);
#2281=ORIENTED_EDGE('',*,*,#2261,.T.);
#2282=EDGE_LOOP('',(#2273,#2279,#2280,#2281));
#2283=FACE_BOUND('',#2282,.T.);
#2284=ADVANCED_FACE('F2028',(#2283),#2272,.F.);
#2285=CARTESIAN_POINT('',(5.74308483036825,-0.38608,4.40682398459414));
#2286=DIRECTION('',(-0.443713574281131,0.,-0.896168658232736));
#2287=DIRECTION('',(-0.896168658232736,0.,0.443713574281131));
#2288=AXIS2_PLACEMENT_3D('',#2285,#2286,#2287);
#2289=PLANE('',#2288);
#2290=ORIENTED_EDGE('',*,*,#178,.T.);
#2291=DIRECTION('',(0.,1.,0.));
#2292=VECTOR('',#2291,1.);
#2293=CARTESIAN_POINT('',(4.84933830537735,-0.38608,4.84933830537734));
#2294=LINE('',#2293,#2292);
#2295=EDGE_CURVE('E1461',#1743,#169,#2294,.T.);
#2296=ORIENTED_EDGE('',*,*,#2295,.F.);
#2297=ORIENTED_EDGE('',*,*,#1744,.F.);
#2298=DIRECTION('',(0.,1.,0.));
#2299=VECTOR('',#2298,1.);
#2300=CARTESIAN_POINT('',(5.74308483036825,-0.38608,4.40682398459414));
#2301=LINE('',#2300,#2299);
#2302=EDGE_CURVE('E1464',#1735,#177,#2301,.T.);
#2303=ORIENTED_EDGE('',*,*,#2302,.T.);
#2304=EDGE_LOOP('',(#2290,#2296,#2297,#2303));
#2305=FACE_BOUND('',#2304,.T.);
#2306=ADVANCED_FACE('F2024',(#2305),#2289,.F.);
#2307=CARTESIAN_POINT('',(4.84933830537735,-0.38608,4.84933830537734));
#2308=DIRECTION('',(-0.896168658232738,0.,-0.443713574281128));
#2309=DIRECTION('',(-0.443713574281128,0.,0.896168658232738));
#2310=AXIS2_PLACEMENT_3D('',#2307,#2308,#2309);
#2311=PLANE('',#2310);
#2312=ORIENTED_EDGE('',*,*,#170,.T.);
#2313=ORIENTED_EDGE('',*,*,#2234,.F.);
#2314=ORIENTED_EDGE('',*,*,#1752,.F.);
#2315=ORIENTED_EDGE('',*,*,#2295,.T.);
#2316=EDGE_LOOP('',(#2312,#2313,#2314,#2315));
#2317=FACE_BOUND('',#2316,.T.);
#2318=ADVANCED_FACE('F2020',(#2317),#2311,.F.);
#2319=CARTESIAN_POINT('',(4.27461926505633,-0.38608,5.57079228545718));
#2320=DIRECTION('',(0.896168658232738,0.,0.443713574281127));
#2321=DIRECTION('',(0.443713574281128,0.,-0.896168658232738));
#2322=AXIS2_PLACEMENT_3D('',#2319,#2320,#2321);
#2323=PLANE('',#2322);
#2324=ORIENTED_EDGE('',*,*,#888,.T.);
#2325=DIRECTION('',(0.,1.,0.));
#2326=VECTOR('',#2325,1.);
#2327=CARTESIAN_POINT('',(4.70385815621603,-0.38608,4.70385815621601));
#2328=LINE('',#2327,#2326);
#2329=EDGE_CURVE('E1458',#1816,#879,#2328,.T.);
#2330=ORIENTED_EDGE('',*,*,#2329,.F.);
#2331=ORIENTED_EDGE('',*,*,#1817,.F.);
#2332=ORIENTED_EDGE('',*,*,#2278,.T.);
#2333=EDGE_LOOP('',(#2324,#2330,#2331,#2332));
#2334=FACE_BOUND('',#2333,.T.);
#2335=ADVANCED_FACE('F2016',(#2334),#2323,.F.);
#2336=CARTESIAN_POINT('',(4.70385815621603,-0.38608,4.70385815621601));
#2337=DIRECTION('',(0.443713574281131,0.,0.896168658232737));
#2338=DIRECTION('',(0.896168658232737,0.,-0.443713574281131));
#2339=AXIS2_PLACEMENT_3D('',#2336,#2337,#2338);
#2340=PLANE('',#2339);
#2341=ORIENTED_EDGE('',*,*,#880,.T.);
#2342=DIRECTION('',(0.,1.,0.));
#2343=VECTOR('',#2342,1.);
#2344=CARTESIAN_POINT('',(5.5707922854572,-0.38608,4.27461926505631));
#2345=LINE('',#2344,#2343);
#2346=EDGE_CURVE('E1448',#1824,#871,#2345,.T.);
#2347=ORIENTED_EDGE('',*,*,#2346,.F.);
#2348=ORIENTED_EDGE('',*,*,#1825,.F.);
#2349=ORIENTED_EDGE('',*,*,#2329,.T.);
#2350=EDGE_LOOP('',(#2341,#2347,#2348,#2349));
#2351=FACE_BOUND('',#2350,.T.);
#2352=ADVANCED_FACE('F2012',(#2351),#2340,.F.);
#2353=CARTESIAN_POINT('',(6.6879639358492,-0.38608,2.77024536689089));
#2354=DIRECTION('',(-0.660539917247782,0.,-0.750790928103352));
#2355=DIRECTION('',(-0.750790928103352,0.,0.660539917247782));
#2356=AXIS2_PLACEMENT_3D('',#2353,#2354,#2355);
#2357=PLANE('',#2356);
#2358=ORIENTED_EDGE('',*,*,#194,.T.);
#2359=DIRECTION('',(0.,1.,0.));
#2360=VECTOR('',#2359,1.);
#2361=CARTESIAN_POINT('',(5.93920221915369,-0.38608,3.42899999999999));
#2362=LINE('',#2361,#2360);
#2363=EDGE_CURVE('E1432',#1727,#185,#2362,.T.);
#2364=ORIENTED_EDGE('',*,*,#2363,.F.);
#2365=ORIENTED_EDGE('',*,*,#1728,.F.);
#2366=DIRECTION('',(0.,1.,0.));
#2367=VECTOR('',#2366,1.);
#2368=CARTESIAN_POINT('',(6.6879639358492,-0.38608,2.77024536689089));
#2369=LINE('',#2368,#2367);
#2370=EDGE_CURVE('E1435',#1719,#193,#2369,.T.);
#2371=ORIENTED_EDGE('',*,*,#2370,.T.);
#2372=EDGE_LOOP('',(#2358,#2364,#2365,#2371));
#2373=FACE_BOUND('',#2372,.T.);
#2374=ADVANCED_FACE('F2008',(#2373),#2357,.F.);
#2375=CARTESIAN_POINT('',(5.93920221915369,-0.38608,3.42899999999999));
#2376=DIRECTION('',(-0.980473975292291,0.,-0.19664888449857));
#2377=DIRECTION('',(-0.19664888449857,0.,0.980473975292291));
#2378=AXIS2_PLACEMENT_3D('',#2375,#2376,#2377);
#2379=PLANE('',#2378);
#2380=ORIENTED_EDGE('',*,*,#186,.T.);
#2381=ORIENTED_EDGE('',*,*,#2302,.F.);
#2382=ORIENTED_EDGE('',*,*,#1736,.F.);
#2383=ORIENTED_EDGE('',*,*,#2363,.T.);
#2384=EDGE_LOOP('',(#2380,#2381,#2382,#2383));
#2385=FACE_BOUND('',#2384,.T.);
#2386=ADVANCED_FACE('F2004',(#2385),#2379,.F.);
#2387=CARTESIAN_POINT('',(5.57079228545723,-0.38608,4.27461926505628));
#2388=DIRECTION('',(0.980473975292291,0.,0.196648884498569));
#2389=DIRECTION('',(0.196648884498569,0.,-0.980473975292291));
#2390=AXIS2_PLACEMENT_3D('',#2387,#2388,#2389);
#2391=PLANE('',#2390);
#2392=ORIENTED_EDGE('',*,*,#872,.T.);
#2393=DIRECTION('',(0.,1.,0.));
#2394=VECTOR('',#2393,1.);
#2395=CARTESIAN_POINT('',(5.76102615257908,-0.38608,3.32612999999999));
#2396=LINE('',#2395,#2394);
#2397=EDGE_CURVE('E1429',#1832,#863,#2396,.T.);
#2398=ORIENTED_EDGE('',*,*,#2397,.F.);
#2399=ORIENTED_EDGE('',*,*,#1833,.F.);
#2400=ORIENTED_EDGE('',*,*,#2346,.T.);
#2401=EDGE_LOOP('',(#2392,#2398,#2399,#2400));
#2402=FACE_BOUND('',#2401,.T.);
#2403=ADVANCED_FACE('F2000',(#2402),#2391,.F.);
#2404=CARTESIAN_POINT('',(5.76102615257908,-0.38608,3.32612999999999));
#2405=DIRECTION('',(0.660539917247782,0.,0.750790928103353));
#2406=DIRECTION('',(0.750790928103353,0.,-0.660539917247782));
#2407=AXIS2_PLACEMENT_3D('',#2404,#2405,#2406);
#2408=PLANE('',#2407);
#2409=ORIENTED_EDGE('',*,*,#864,.T.);
#2410=DIRECTION('',(0.,1.,0.));
#2411=VECTOR('',#2410,1.);
#2412=CARTESIAN_POINT('',(6.48732501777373,-0.38608,2.68713800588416));
#2413=LINE('',#2412,#2411);
#2414=EDGE_CURVE('E1419',#1840,#855,#2413,.T.);
#2415=ORIENTED_EDGE('',*,*,#2414,.F.);
#2416=ORIENTED_EDGE('',*,*,#1841,.F.);
#2417=ORIENTED_EDGE('',*,*,#2397,.T.);
#2418=EDGE_LOOP('',(#2409,#2415,#2416,#2417));
#2419=FACE_BOUND('',#2418,.T.);
#2420=ADVANCED_FACE('F1996',(#2419),#2408,.F.);
#2421=CARTESIAN_POINT('',(7.17706935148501,-0.38608,0.944879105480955));
#2422=DIRECTION('',(-0.832351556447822,0.,-0.554248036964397));
#2423=DIRECTION('',(-0.554248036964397,0.,0.832351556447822));
#2424=AXIS2_PLACEMENT_3D('',#2421,#2422,#2423);
#2425=PLANE('',#2424);
#2426=ORIENTED_EDGE('',*,*,#210,.T.);
#2427=DIRECTION('',(0.,1.,0.));
#2428=VECTOR('',#2427,1.);
#2429=CARTESIAN_POINT('',(6.62431931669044,-0.38608,1.77498101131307));
#2430=LINE('',#2429,#2428);
#2431=EDGE_CURVE('E1403',#1711,#201,#2430,.T.);
#2432=ORIENTED_EDGE('',*,*,#2431,.F.);
#2433=ORIENTED_EDGE('',*,*,#1712,.F.);
#2434=DIRECTION('',(0.,1.,0.));
#2435=VECTOR('',#2434,1.);
#2436=CARTESIAN_POINT('',(7.17706935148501,-0.38608,0.944879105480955));
#2437=LINE('',#2436,#2435);
#2438=EDGE_CURVE('E1406',#1703,#209,#2437,.T.);
#2439=ORIENTED_EDGE('',*,*,#2438,.T.);
#2440=EDGE_LOOP('',(#2426,#2432,#2433,#2439));
#2441=FACE_BOUND('',#2440,.T.);
#2442=ADVANCED_FACE('F1992',(#2441),#2425,.F.);
#2443=CARTESIAN_POINT('',(6.62431931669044,-0.38608,1.77498101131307));
#2444=DIRECTION('',(-0.99796161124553,0.,0.0638171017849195));
#2445=DIRECTION('',(0.0638171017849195,0.,0.99796161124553));
#2446=AXIS2_PLACEMENT_3D('',#2443,#2444,#2445);
#2447=PLANE('',#2446);
#2448=ORIENTED_EDGE('',*,*,#202,.T.);
#2449=ORIENTED_EDGE('',*,*,#2370,.F.);
#2450=ORIENTED_EDGE('',*,*,#1720,.F.);
#2451=ORIENTED_EDGE('',*,*,#2431,.T.);
#2452=EDGE_LOOP('',(#2448,#2449,#2450,#2451));
#2453=FACE_BOUND('',#2452,.T.);
#2454=ADVANCED_FACE('F1988',(#2453),#2447,.F.);
#2455=CARTESIAN_POINT('',(6.48732501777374,-0.38608,2.68713800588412));
#2456=DIRECTION('',(0.997961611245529,0.,-0.0638171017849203));
#2457=DIRECTION('',(-0.0638171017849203,0.,-0.99796161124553));
#2458=AXIS2_PLACEMENT_3D('',#2455,#2456,#2457);
#2459=PLANE('',#2458);
#2460=ORIENTED_EDGE('',*,*,#856,.T.);
#2461=DIRECTION('',(0.,1.,0.));
#2462=VECTOR('',#2461,1.);
#2463=CARTESIAN_POINT('',(6.42558973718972,-0.38608,1.72173158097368));
#2464=LINE('',#2463,#2462);
#2465=EDGE_CURVE('E1400',#1848,#847,#2464,.T.);
#2466=ORIENTED_EDGE('',*,*,#2465,.F.);
#2467=ORIENTED_EDGE('',*,*,#1849,.F.);
#2468=ORIENTED_EDGE('',*,*,#2414,.T.);
#2469=EDGE_LOOP('',(#2460,#2466,#2467,#2468));
#2470=FACE_BOUND('',#2469,.T.);
#2471=ADVANCED_FACE('F1984',(#2470),#2459,.F.);
#2472=CARTESIAN_POINT('',(6.42558973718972,-0.38608,1.72173158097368));
#2473=DIRECTION('',(0.832351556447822,0.,0.554248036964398));
#2474=DIRECTION('',(0.554248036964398,0.,-0.832351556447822));
#2475=AXIS2_PLACEMENT_3D('',#2472,#2473,#2474);
#2476=PLANE('',#2475);
#2477=ORIENTED_EDGE('',*,*,#848,.T.);
#2478=DIRECTION('',(0.,1.,0.));
#2479=VECTOR('',#2478,1.);
#2480=CARTESIAN_POINT('',(6.96175727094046,-0.38608,0.916532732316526));
#2481=LINE('',#2480,#2479);
#2482=EDGE_CURVE('E1390',#1856,#839,#2481,.T.);
#2483=ORIENTED_EDGE('',*,*,#2482,.F.);
#2484=ORIENTED_EDGE('',*,*,#1857,.F.);
#2485=ORIENTED_EDGE('',*,*,#2465,.T.);
#2486=EDGE_LOOP('',(#2477,#2483,#2484,#2485));
#2487=FACE_BOUND('',#2486,.T.);
#2488=ADVANCED_FACE('F1980',(#2487),#2476,.F.);
#2489=CARTESIAN_POINT('',(7.17706935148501,-0.38608,-0.944879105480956));
#2490=DIRECTION('',(-0.947439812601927,0.,-0.319934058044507));
#2491=DIRECTION('',(-0.319934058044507,0.,0.947439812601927));
#2492=AXIS2_PLACEMENT_3D('',#2489,#2490,#2491);
#2493=PLANE('',#2492);
#2494=ORIENTED_EDGE('',*,*,#226,.T.);
#2495=DIRECTION('',(0.,1.,0.));
#2496=VECTOR('',#2495,1.);
#2497=CARTESIAN_POINT('',(6.858,-0.38608,0.));
#2498=LINE('',#2497,#2496);
#2499=EDGE_CURVE('E1374',#1695,#217,#2498,.T.);
#2500=ORIENTED_EDGE('',*,*,#2499,.F.);
#2501=ORIENTED_EDGE('',*,*,#1696,.F.);
#2502=DIRECTION('',(0.,1.,0.));
#2503=VECTOR('',#2502,1.);
#2504=CARTESIAN_POINT('',(7.17706935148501,-0.38608,-0.944879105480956));
#2505=LINE('',#2504,#2503);
#2506=EDGE_CURVE('E1377',#1687,#225,#2505,.T.);
#2507=ORIENTED_EDGE('',*,*,#2506,.T.);
#2508=EDGE_LOOP('',(#2494,#2500,#2501,#2507));
#2509=FACE_BOUND('',#2508,.T.);
#2510=ADVANCED_FACE('F1976',(#2509),#2493,.F.);
#2511=CARTESIAN_POINT('',(6.858,-0.38608,0.));
#2512=DIRECTION('',(-0.947439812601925,0.,0.319934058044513));
#2513=DIRECTION('',(0.319934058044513,0.,0.947439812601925));
#2514=AXIS2_PLACEMENT_3D('',#2511,#2512,#2513);
#2515=PLANE('',#2514);
#2516=ORIENTED_EDGE('',*,*,#218,.T.);
#2517=ORIENTED_EDGE('',*,*,#2438,.F.);
#2518=ORIENTED_EDGE('',*,*,#1704,.F.);
#2519=ORIENTED_EDGE('',*,*,#2499,.T.);
#2520=EDGE_LOOP('',(#2516,#2517,#2518,#2519));
#2521=FACE_BOUND('',#2520,.T.);
#2522=ADVANCED_FACE('F1972',(#2521),#2515,.F.);
#2523=CARTESIAN_POINT('',(6.96175727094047,-0.38608,0.916532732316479));
#2524=DIRECTION('',(0.947439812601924,0.,-0.319934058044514));
#2525=DIRECTION('',(-0.319934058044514,0.,-0.947439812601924));
#2526=AXIS2_PLACEMENT_3D('',#2523,#2524,#2525);
#2527=PLANE('',#2526);
#2528=ORIENTED_EDGE('',*,*,#840,.T.);
#2529=DIRECTION('',(0.,1.,0.));
#2530=VECTOR('',#2529,1.);
#2531=CARTESIAN_POINT('',(6.65226,-0.38608,0.));
#2532=LINE('',#2531,#2530);
#2533=EDGE_CURVE('E1371',#1864,#831,#2532,.T.);
#2534=ORIENTED_EDGE('',*,*,#2533,.F.);
#2535=ORIENTED_EDGE('',*,*,#1865,.F.);
#2536=ORIENTED_EDGE('',*,*,#2482,.T.);
#2537=EDGE_LOOP('',(#2528,#2534,#2535,#2536));
#2538=FACE_BOUND('',#2537,.T.);
#2539=ADVANCED_FACE('F1968',(#2538),#2527,.F.);
#2540=CARTESIAN_POINT('',(6.65226,-0.38608,0.));
#2541=DIRECTION('',(0.947439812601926,0.,0.319934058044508));
#2542=DIRECTION('',(0.319934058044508,0.,-0.947439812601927));
#2543=AXIS2_PLACEMENT_3D('',#2540,#2541,#2542);
#2544=PLANE('',#2543);
#2545=ORIENTED_EDGE('',*,*,#832,.T.);
#2546=DIRECTION('',(0.,1.,0.));
#2547=VECTOR('',#2546,1.);
#2548=CARTESIAN_POINT('',(6.96175727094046,-0.38608,-0.916532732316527));
#2549=LINE('',#2548,#2547);
#2550=EDGE_CURVE('E1361',#1872,#823,#2549,.T.);
#2551=ORIENTED_EDGE('',*,*,#2550,.F.);
#2552=ORIENTED_EDGE('',*,*,#1873,.F.);
#2553=ORIENTED_EDGE('',*,*,#2533,.T.);
#2554=EDGE_LOOP('',(#2545,#2551,#2552,#2553));
#2555=FACE_BOUND('',#2554,.T.);
#2556=ADVANCED_FACE('F1964',(#2555),#2544,.F.);
#2557=CARTESIAN_POINT('',(6.6879639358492,-0.38608,-2.77024536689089));
#2558=DIRECTION('',(-0.99796161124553,0.,-0.0638171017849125));
#2559=DIRECTION('',(-0.0638171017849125,0.,0.99796161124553));
#2560=AXIS2_PLACEMENT_3D('',#2557,#2558,#2559);
#2561=PLANE('',#2560);
#2562=ORIENTED_EDGE('',*,*,#242,.T.);
#2563=DIRECTION('',(0.,1.,0.));
#2564=VECTOR('',#2563,1.);
#2565=CARTESIAN_POINT('',(6.62431931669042,-0.38608,-1.77498101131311));
#2566=LINE('',#2565,#2564);
#2567=EDGE_CURVE('E1345',#1679,#233,#2566,.T.);
#2568=ORIENTED_EDGE('',*,*,#2567,.F.);
#2569=ORIENTED_EDGE('',*,*,#1680,.F.);
#2570=DIRECTION('',(0.,1.,0.));
#2571=VECTOR('',#2570,1.);
#2572=CARTESIAN_POINT('',(6.6879639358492,-0.38608,-2.77024536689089));
#2573=LINE('',#2572,#2571);
#2574=EDGE_CURVE('E1348',#1671,#241,#2573,.T.);
#2575=ORIENTED_EDGE('',*,*,#2574,.T.);
#2576=EDGE_LOOP('',(#2562,#2568,#2569,#2575));
#2577=FACE_BOUND('',#2576,.T.);
#2578=ADVANCED_FACE('F1960',(#2577),#2561,.F.);
#2579=CARTESIAN_POINT('',(6.62431931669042,-0.38608,-1.77498101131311));
#2580=DIRECTION('',(-0.832351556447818,0.,0.554248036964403));
#2581=DIRECTION('',(0.554248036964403,0.,0.832351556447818));
#2582=AXIS2_PLACEMENT_3D('',#2579,#2580,#2581);
#2583=PLANE('',#2582);
#2584=ORIENTED_EDGE('',*,*,#234,.T.);
#2585=ORIENTED_EDGE('',*,*,#2506,.F.);
#2586=ORIENTED_EDGE('',*,*,#1688,.F.);
#2587=ORIENTED_EDGE('',*,*,#2567,.T.);
#2588=EDGE_LOOP('',(#2584,#2585,#2586,#2587));
#2589=FACE_BOUND('',#2588,.T.);
#2590=ADVANCED_FACE('F1956',(#2589),#2583,.F.);
#2591=CARTESIAN_POINT('',(6.96175727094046,-0.38608,-0.916532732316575));
#2592=DIRECTION('',(0.832351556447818,0.,-0.554248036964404));
#2593=DIRECTION('',(-0.554248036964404,0.,-0.832351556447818));
#2594=AXIS2_PLACEMENT_3D('',#2591,#2592,#2593);
#2595=PLANE('',#2594);
#2596=ORIENTED_EDGE('',*,*,#824,.T.);
#2597=DIRECTION('',(0.,1.,0.));
#2598=VECTOR('',#2597,1.);
#2599=CARTESIAN_POINT('',(6.42558973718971,-0.38608,-1.72173158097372));
#2600=LINE('',#2599,#2598);
#2601=EDGE_CURVE('E1342',#1880,#815,#2600,.T.);
#2602=ORIENTED_EDGE('',*,*,#2601,.F.);
#2603=ORIENTED_EDGE('',*,*,#1881,.F.);
#2604=ORIENTED_EDGE('',*,*,#2550,.T.);
#2605=EDGE_LOOP('',(#2596,#2602,#2603,#2604));
#2606=FACE_BOUND('',#2605,.T.);
#2607=ADVANCED_FACE('F1952',(#2606),#2595,.F.);
#2608=CARTESIAN_POINT('',(6.42558973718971,-0.38608,-1.72173158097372));
#2609=DIRECTION('',(0.99796161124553,0.,0.0638171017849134));
#2610=DIRECTION('',(0.0638171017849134,0.,-0.99796161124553));
#2611=AXIS2_PLACEMENT_3D('',#2608,#2609,#2610);
#2612=PLANE('',#2611);
#2613=ORIENTED_EDGE('',*,*,#816,.T.);
#2614=DIRECTION('',(0.,1.,0.));
#2615=VECTOR('',#2614,1.);
#2616=CARTESIAN_POINT('',(6.48732501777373,-0.38608,-2.68713800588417));
#2617=LINE('',#2616,#2615);
#2618=EDGE_CURVE('E1332',#1888,#807,#2617,.T.);
#2619=ORIENTED_EDGE('',*,*,#2618,.F.);
#2620=ORIENTED_EDGE('',*,*,#1889,.F.);
#2621=ORIENTED_EDGE('',*,*,#2601,.T.);
#2622=EDGE_LOOP('',(#2613,#2619,#2620,#2621));
#2623=FACE_BOUND('',#2622,.T.);
#2624=ADVANCED_FACE('F1948',(#2623),#2612,.F.);
#2625=CARTESIAN_POINT('',(5.74308483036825,-0.38608,-4.40682398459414));
#2626=DIRECTION('',(-0.98047397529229,0.,0.196648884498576));
#2627=DIRECTION('',(0.196648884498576,0.,0.98047397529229));
#2628=AXIS2_PLACEMENT_3D('',#2625,#2626,#2627);
#2629=PLANE('',#2628);
#2630=ORIENTED_EDGE('',*,*,#258,.T.);
#2631=DIRECTION('',(0.,1.,0.));
#2632=VECTOR('',#2631,1.);
#2633=CARTESIAN_POINT('',(5.93920221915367,-0.38608,-3.42900000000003));
#2634=LINE('',#2633,#2632);
#2635=EDGE_CURVE('E1316',#1663,#249,#2634,.T.);
#2636=ORIENTED_EDGE('',*,*,#2635,.F.);
#2637=ORIENTED_EDGE('',*,*,#1664,.F.);
#2638=DIRECTION('',(0.,1.,0.));
#2639=VECTOR('',#2638,1.);
#2640=CARTESIAN_POINT('',(5.74308483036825,-0.38608,-4.40682398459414));
#2641=LINE('',#2640,#2639);
#2642=EDGE_CURVE('E1319',#1655,#257,#2641,.T.);
#2643=ORIENTED_EDGE('',*,*,#2642,.T.);
#2644=EDGE_LOOP('',(#2630,#2636,#2637,#2643));
#2645=FACE_BOUND('',#2644,.T.);
#2646=ADVANCED_FACE('F1944',(#2645),#2629,.F.);
#2647=CARTESIAN_POINT('',(5.93920221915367,-0.38608,-3.42900000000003));
#2648=DIRECTION('',(-0.660539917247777,0.,0.750790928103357));
#2649=DIRECTION('',(0.750790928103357,0.,0.660539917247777));
#2650=AXIS2_PLACEMENT_3D('',#2647,#2648,#2649);
#2651=PLANE('',#2650);
#2652=ORIENTED_EDGE('',*,*,#250,.T.);
#2653=ORIENTED_EDGE('',*,*,#2574,.F.);
#2654=ORIENTED_EDGE('',*,*,#1672,.F.);
#2655=ORIENTED_EDGE('',*,*,#2635,.T.);
#2656=EDGE_LOOP('',(#2652,#2653,#2654,#2655));
#2657=FACE_BOUND('',#2656,.T.);
#2658=ADVANCED_FACE('F1940',(#2657),#2651,.F.);
#2659=CARTESIAN_POINT('',(6.48732501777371,-0.38608,-2.68713800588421));
#2660=DIRECTION('',(0.660539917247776,0.,-0.750790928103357));
#2661=DIRECTION('',(-0.750790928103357,0.,-0.660539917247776));
#2662=AXIS2_PLACEMENT_3D('',#2659,#2660,#2661);
#2663=PLANE('',#2662);
#2664=ORIENTED_EDGE('',*,*,#808,.T.);
#2665=DIRECTION('',(0.,1.,0.));
#2666=VECTOR('',#2665,1.);
#2667=CARTESIAN_POINT('',(5.76102615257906,-0.38608,-3.32613000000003));
#2668=LINE('',#2667,#2666);
#2669=EDGE_CURVE('E1313',#1896,#799,#2668,.T.);
#2670=ORIENTED_EDGE('',*,*,#2669,.F.);
#2671=ORIENTED_EDGE('',*,*,#1897,.F.);
#2672=ORIENTED_EDGE('',*,*,#2618,.T.);
#2673=EDGE_LOOP('',(#2664,#2670,#2671,#2672));
#2674=FACE_BOUND('',#2673,.T.);
#2675=ADVANCED_FACE('F1936',(#2674),#2663,.F.);
#2676=CARTESIAN_POINT('',(5.76102615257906,-0.38608,-3.32613000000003));
#2677=DIRECTION('',(0.98047397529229,0.,-0.196648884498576));
#2678=DIRECTION('',(-0.196648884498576,0.,-0.98047397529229));
#2679=AXIS2_PLACEMENT_3D('',#2676,#2677,#2678);
#2680=PLANE('',#2679);
#2681=ORIENTED_EDGE('',*,*,#800,.T.);
#2682=DIRECTION('',(0.,1.,0.));
#2683=VECTOR('',#2682,1.);
#2684=CARTESIAN_POINT('',(5.5707922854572,-0.38608,-4.27461926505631));
#2685=LINE('',#2684,#2683);
#2686=EDGE_CURVE('E1303',#1904,#791,#2685,.T.);
#2687=ORIENTED_EDGE('',*,*,#2686,.F.);
#2688=ORIENTED_EDGE('',*,*,#1905,.F.);
#2689=ORIENTED_EDGE('',*,*,#2669,.T.);
#2690=EDGE_LOOP('',(#2681,#2687,#2688,#2689));
#2691=FACE_BOUND('',#2690,.T.);
#2692=ADVANCED_FACE('F1932',(#2691),#2680,.F.);
#2693=CARTESIAN_POINT('',(4.40682398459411,-0.38608,-5.74308483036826));
#2694=DIRECTION('',(-0.896168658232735,0.,0.443713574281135));
#2695=DIRECTION('',(0.443713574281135,0.,0.896168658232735));
#2696=AXIS2_PLACEMENT_3D('',#2693,#2694,#2695);
#2697=PLANE('',#2696);
#2698=ORIENTED_EDGE('',*,*,#274,.T.);
#2699=DIRECTION('',(0.,1.,0.));
#2700=VECTOR('',#2699,1.);
#2701=CARTESIAN_POINT('',(4.84933830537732,-0.38608,-4.84933830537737));
#2702=LINE('',#2701,#2700);
#2703=EDGE_CURVE('E1287',#1647,#265,#2702,.T.);
#2704=ORIENTED_EDGE('',*,*,#2703,.F.);
#2705=ORIENTED_EDGE('',*,*,#1648,.F.);
#2706=DIRECTION('',(0.,1.,0.));
#2707=VECTOR('',#2706,1.);
#2708=CARTESIAN_POINT('',(4.40682398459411,-0.38608,-5.74308483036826));
#2709=LINE('',#2708,#2707);
#2710=EDGE_CURVE('E1290',#1639,#273,#2709,.T.);
#2711=ORIENTED_EDGE('',*,*,#2710,.T.);
#2712=EDGE_LOOP('',(#2698,#2704,#2705,#2711));
#2713=FACE_BOUND('',#2712,.T.);
#2714=ADVANCED_FACE('F1928',(#2713),#2697,.F.);
#2715=CARTESIAN_POINT('',(4.84933830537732,-0.38608,-4.84933830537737));
#2716=DIRECTION('',(-0.443713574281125,0.,0.896168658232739));
#2717=DIRECTION('',(0.896168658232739,0.,0.443713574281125));
#2718=AXIS2_PLACEMENT_3D('',#2715,#2716,#2717);
#2719=PLANE('',#2718);
#2720=ORIENTED_EDGE('',*,*,#266,.T.);
#2721=ORIENTED_EDGE('',*,*,#2642,.F.);
#2722=ORIENTED_EDGE('',*,*,#1656,.F.);
#2723=ORIENTED_EDGE('',*,*,#2703,.T.);
#2724=EDGE_LOOP('',(#2720,#2721,#2722,#2723));
#2725=FACE_BOUND('',#2724,.T.);
#2726=ADVANCED_FACE('F1924',(#2725),#2719,.F.);
#2727=CARTESIAN_POINT('',(5.57079228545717,-0.38608,-4.27461926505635));
#2728=DIRECTION('',(0.443713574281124,0.,-0.89616865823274));
#2729=DIRECTION('',(-0.89616865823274,0.,-0.443713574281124));
#2730=AXIS2_PLACEMENT_3D('',#2727,#2728,#2729);
#2731=PLANE('',#2730);
#2732=ORIENTED_EDGE('',*,*,#792,.T.);
#2733=DIRECTION('',(0.,1.,0.));
#2734=VECTOR('',#2733,1.);
#2735=CARTESIAN_POINT('',(4.703858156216,-0.38608,-4.70385815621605));
#2736=LINE('',#2735,#2734);
#2737=EDGE_CURVE('E1284',#1912,#783,#2736,.T.);
#2738=ORIENTED_EDGE('',*,*,#2737,.F.);
#2739=ORIENTED_EDGE('',*,*,#1913,.F.);
#2740=ORIENTED_EDGE('',*,*,#2686,.T.);
#2741=EDGE_LOOP('',(#2732,#2738,#2739,#2740));
#2742=FACE_BOUND('',#2741,.T.);
#2743=ADVANCED_FACE('F1920',(#2742),#2731,.F.);
#2744=CARTESIAN_POINT('',(4.703858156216,-0.38608,-4.70385815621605));
#2745=DIRECTION('',(0.896168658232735,0.,-0.443713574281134));
#2746=DIRECTION('',(-0.443713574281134,0.,-0.896168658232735));
#2747=AXIS2_PLACEMENT_3D('',#2744,#2745,#2746);
#2748=PLANE('',#2747);
#2749=ORIENTED_EDGE('',*,*,#784,.T.);
#2750=DIRECTION('',(0.,1.,0.));
#2751=VECTOR('',#2750,1.);
#2752=CARTESIAN_POINT('',(4.27461926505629,-0.38608,-5.57079228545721));
#2753=LINE('',#2752,#2751);
#2754=EDGE_CURVE('E1274',#1920,#775,#2753,.T.);
#2755=ORIENTED_EDGE('',*,*,#2754,.F.);
#2756=ORIENTED_EDGE('',*,*,#1921,.F.);
#2757=ORIENTED_EDGE('',*,*,#2737,.T.);
#2758=EDGE_LOOP('',(#2749,#2755,#2756,#2757));
#2759=FACE_BOUND('',#2758,.T.);
#2760=ADVANCED_FACE('F1916',(#2759),#2748,.F.);
#2761=CARTESIAN_POINT('',(2.77024536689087,-0.38608,-6.68796393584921));
#2762=DIRECTION('',(-0.75079092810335,0.,0.660539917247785));
#2763=DIRECTION('',(0.660539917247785,0.,0.75079092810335));
#2764=AXIS2_PLACEMENT_3D('',#2761,#2762,#2763);
#2765=PLANE('',#2764);
#2766=ORIENTED_EDGE('',*,*,#290,.T.);
#2767=DIRECTION('',(0.,1.,0.));
#2768=VECTOR('',#2767,1.);
#2769=CARTESIAN_POINT('',(3.42899999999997,-0.38608,-5.9392022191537));
#2770=LINE('',#2769,#2768);
#2771=EDGE_CURVE('E1258',#1631,#281,#2770,.T.);
#2772=ORIENTED_EDGE('',*,*,#2771,.F.);
#2773=ORIENTED_EDGE('',*,*,#1632,.F.);
#2774=DIRECTION('',(0.,1.,0.));
#2775=VECTOR('',#2774,1.);
#2776=CARTESIAN_POINT('',(2.77024536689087,-0.38608,-6.68796393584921));
#2777=LINE('',#2776,#2775);
#2778=EDGE_CURVE('E1261',#1623,#289,#2777,.T.);
#2779=ORIENTED_EDGE('',*,*,#2778,.T.);
#2780=EDGE_LOOP('',(#2766,#2772,#2773,#2779));
#2781=FACE_BOUND('',#2780,.T.);
#2782=ADVANCED_FACE('F1912',(#2781),#2765,.F.);
#2783=CARTESIAN_POINT('',(3.42899999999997,-0.38608,-5.9392022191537));
#2784=DIRECTION('',(-0.196648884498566,0.,0.980473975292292));
#2785=DIRECTION('',(0.980473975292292,0.,0.196648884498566));
#2786=AXIS2_PLACEMENT_3D('',#2783,#2784,#2785);
#2787=PLANE('',#2786);
#2788=ORIENTED_EDGE('',*,*,#282,.T.);
#2789=ORIENTED_EDGE('',*,*,#2710,.F.);
#2790=ORIENTED_EDGE('',*,*,#1640,.F.);
#2791=ORIENTED_EDGE('',*,*,#2771,.T.);
#2792=EDGE_LOOP('',(#2788,#2789,#2790,#2791));
#2793=FACE_BOUND('',#2792,.T.);
#2794=ADVANCED_FACE('F1908',(#2793),#2787,.F.);
#2795=CARTESIAN_POINT('',(4.27461926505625,-0.38608,-5.57079228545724));
#2796=DIRECTION('',(0.196648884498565,0.,-0.980473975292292));
#2797=DIRECTION('',(-0.980473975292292,0.,-0.196648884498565));
#2798=AXIS2_PLACEMENT_3D('',#2795,#2796,#2797);
#2799=PLANE('',#2798);
#2800=ORIENTED_EDGE('',*,*,#776,.T.);
#2801=DIRECTION('',(0.,1.,0.));
#2802=VECTOR('',#2801,1.);
#2803=CARTESIAN_POINT('',(3.32612999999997,-0.38608,-5.76102615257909));
#2804=LINE('',#2803,#2802);
#2805=EDGE_CURVE('E1255',#1928,#767,#2804,.T.);
#2806=ORIENTED_EDGE('',*,*,#2805,.F.);
#2807=ORIENTED_EDGE('',*,*,#1929,.F.);
#2808=ORIENTED_EDGE('',*,*,#2754,.T.);
#2809=EDGE_LOOP('',(#2800,#2806,#2807,#2808));
#2810=FACE_BOUND('',#2809,.T.);
#2811=ADVANCED_FACE('F1904',(#2810),#2799,.F.);
#2812=CARTESIAN_POINT('',(3.32612999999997,-0.38608,-5.76102615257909));
#2813=DIRECTION('',(0.75079092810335,0.,-0.660539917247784));
#2814=DIRECTION('',(-0.660539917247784,0.,-0.750790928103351));
#2815=AXIS2_PLACEMENT_3D('',#2812,#2813,#2814);
#2816=PLANE('',#2815);
#2817=ORIENTED_EDGE('',*,*,#768,.T.);
#2818=DIRECTION('',(0.,1.,0.));
#2819=VECTOR('',#2818,1.);
#2820=CARTESIAN_POINT('',(2.68713800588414,-0.38608,-6.48732501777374));
#2821=LINE('',#2820,#2819);
#2822=EDGE_CURVE('E1245',#1936,#759,#2821,.T.);
#2823=ORIENTED_EDGE('',*,*,#2822,.F.);
#2824=ORIENTED_EDGE('',*,*,#1937,.F.);
#2825=ORIENTED_EDGE('',*,*,#2805,.T.);
#2826=EDGE_LOOP('',(#2817,#2823,#2824,#2825));
#2827=FACE_BOUND('',#2826,.T.);
#2828=ADVANCED_FACE('F1900',(#2827),#2816,.F.);
#2829=CARTESIAN_POINT('',(0.94487910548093,-0.38608,-7.17706935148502));
#2830=DIRECTION('',(-0.554248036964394,0.,0.832351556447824));
#2831=DIRECTION('',(0.832351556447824,0.,0.554248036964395));
#2832=AXIS2_PLACEMENT_3D('',#2829,#2830,#2831);
#2833=PLANE('',#2832);
#2834=ORIENTED_EDGE('',*,*,#306,.T.);
#2835=DIRECTION('',(0.,1.,0.));
#2836=VECTOR('',#2835,1.);
#2837=CARTESIAN_POINT('',(1.77498101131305,-0.38608,-6.62431931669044));
#2838=LINE('',#2837,#2836);
#2839=EDGE_CURVE('E1229',#1615,#297,#2838,.T.);
#2840=ORIENTED_EDGE('',*,*,#2839,.F.);
#2841=ORIENTED_EDGE('',*,*,#1616,.F.);
#2842=DIRECTION('',(0.,1.,0.));
#2843=VECTOR('',#2842,1.);
#2844=CARTESIAN_POINT('',(0.94487910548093,-0.38608,-7.17706935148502));
#2845=LINE('',#2844,#2843);
#2846=EDGE_CURVE('E1232',#1607,#305,#2845,.T.);
#2847=ORIENTED_EDGE('',*,*,#2846,.T.);
#2848=EDGE_LOOP('',(#2834,#2840,#2841,#2847));
#2849=FACE_BOUND('',#2848,.T.);
#2850=ADVANCED_FACE('F1896',(#2849),#2833,.F.);
#2851=CARTESIAN_POINT('',(1.77498101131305,-0.38608,-6.62431931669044));
#2852=DIRECTION('',(0.063817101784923,0.,0.997961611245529));
#2853=DIRECTION('',(0.997961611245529,0.,-0.063817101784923));
#2854=AXIS2_PLACEMENT_3D('',#2851,#2852,#2853);
#2855=PLANE('',#2854);
#2856=ORIENTED_EDGE('',*,*,#298,.T.);
#2857=ORIENTED_EDGE('',*,*,#2778,.F.);
#2858=ORIENTED_EDGE('',*,*,#1624,.F.);
#2859=ORIENTED_EDGE('',*,*,#2839,.T.);
#2860=EDGE_LOOP('',(#2856,#2857,#2858,#2859));
#2861=FACE_BOUND('',#2860,.T.);
#2862=ADVANCED_FACE('F1892',(#2861),#2855,.F.);
#2863=CARTESIAN_POINT('',(2.6871380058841,-0.38608,-6.48732501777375));
#2864=DIRECTION('',(-0.0638171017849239,0.,-0.997961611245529));
#2865=DIRECTION('',(-0.997961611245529,0.,0.0638171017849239));
#2866=AXIS2_PLACEMENT_3D('',#2863,#2864,#2865);
#2867=PLANE('',#2866);
#2868=ORIENTED_EDGE('',*,*,#760,.T.);
#2869=DIRECTION('',(0.,1.,0.));
#2870=VECTOR('',#2869,1.);
#2871=CARTESIAN_POINT('',(1.72173158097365,-0.38608,-6.42558973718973));
#2872=LINE('',#2871,#2870);
#2873=EDGE_CURVE('E1226',#1944,#751,#2872,.T.);
#2874=ORIENTED_EDGE('',*,*,#2873,.F.);
#2875=ORIENTED_EDGE('',*,*,#1945,.F.);
#2876=ORIENTED_EDGE('',*,*,#2822,.T.);
#2877=EDGE_LOOP('',(#2868,#2874,#2875,#2876));
#2878=FACE_BOUND('',#2877,.T.);
#2879=ADVANCED_FACE('F1888',(#2878),#2867,.F.);
#2880=CARTESIAN_POINT('',(1.72173158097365,-0.38608,-6.42558973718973));
#2881=DIRECTION('',(0.554248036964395,0.,-0.832351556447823));
#2882=DIRECTION('',(-0.832351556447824,0.,-0.554248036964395));
#2883=AXIS2_PLACEMENT_3D('',#2880,#2881,#2882);
#2884=PLANE('',#2883);
#2885=ORIENTED_EDGE('',*,*,#752,.T.);
#2886=DIRECTION('',(0.,1.,0.));
#2887=VECTOR('',#2886,1.);
#2888=CARTESIAN_POINT('',(0.916532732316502,-0.38608,-6.96175727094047));
#2889=LINE('',#2888,#2887);
#2890=EDGE_CURVE('E1216',#1952,#743,#2889,.T.);
#2891=ORIENTED_EDGE('',*,*,#2890,.F.);
#2892=ORIENTED_EDGE('',*,*,#1953,.F.);
#2893=ORIENTED_EDGE('',*,*,#2873,.T.);
#2894=EDGE_LOOP('',(#2885,#2891,#2892,#2893));
#2895=FACE_BOUND('',#2894,.T.);
#2896=ADVANCED_FACE('F1884',(#2895),#2884,.F.);
#2897=CARTESIAN_POINT('',(-0.944879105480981,-0.38608,-7.17706935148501));
#2898=DIRECTION('',(-0.319934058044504,0.,0.947439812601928));
#2899=DIRECTION('',(0.947439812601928,0.,0.319934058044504));
#2900=AXIS2_PLACEMENT_3D('',#2897,#2898,#2899);
#2901=PLANE('',#2900);
#2902=ORIENTED_EDGE('',*,*,#322,.T.);
#2903=DIRECTION('',(0.,1.,0.));
#2904=VECTOR('',#2903,1.);
#2905=CARTESIAN_POINT('',(0.,-0.38608,-6.858));
#2906=LINE('',#2905,#2904);
#2907=EDGE_CURVE('E1200',#1599,#313,#2906,.T.);
#2908=ORIENTED_EDGE('',*,*,#2907,.F.);
#2909=ORIENTED_EDGE('',*,*,#1600,.F.);
#2910=DIRECTION('',(0.,1.,0.));
#2911=VECTOR('',#2910,1.);
#2912=CARTESIAN_POINT('',(-0.944879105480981,-0.38608,-7.17706935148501));
#2913=LINE('',#2912,#2911);
#2914=EDGE_CURVE('E1203',#1591,#321,#2913,.T.);
#2915=ORIENTED_EDGE('',*,*,#2914,.T.);
#2916=EDGE_LOOP('',(#2902,#2908,#2909,#2915));
#2917=FACE_BOUND('',#2916,.T.);
#2918=ADVANCED_FACE('F1880',(#2917),#2901,.F.);
#2919=CARTESIAN_POINT('',(0.,-0.38608,-6.858));
#2920=DIRECTION('',(0.319934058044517,0.,0.947439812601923));
#2921=DIRECTION('',(0.947439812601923,0.,-0.319934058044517));
#2922=AXIS2_PLACEMENT_3D('',#2919,#2920,#2921);
#2923=PLANE('',#2922);
#2924=ORIENTED_EDGE('',*,*,#314,.T.);
#2925=ORIENTED_EDGE('',*,*,#2846,.F.);
#2926=ORIENTED_EDGE('',*,*,#1608,.F.);
#2927=ORIENTED_EDGE('',*,*,#2907,.T.);
#2928=EDGE_LOOP('',(#2924,#2925,#2926,#2927));
#2929=FACE_BOUND('',#2928,.T.);
#2930=ADVANCED_FACE('F1876',(#2929),#2923,.F.);
#2931=CARTESIAN_POINT('',(0.916532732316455,-0.38608,-6.96175727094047));
#2932=DIRECTION('',(-0.319934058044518,0.,-0.947439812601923));
#2933=DIRECTION('',(-0.947439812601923,0.,0.319934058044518));
#2934=AXIS2_PLACEMENT_3D('',#2931,#2932,#2933);
#2935=PLANE('',#2934);
#2936=ORIENTED_EDGE('',*,*,#744,.T.);
#2937=DIRECTION('',(0.,1.,0.));
#2938=VECTOR('',#2937,1.);
#2939=CARTESIAN_POINT('',(0.,-0.38608,-6.65226));
#2940=LINE('',#2939,#2938);
#2941=EDGE_CURVE('E1197',#1960,#735,#2940,.T.);
#2942=ORIENTED_EDGE('',*,*,#2941,.F.);
#2943=ORIENTED_EDGE('',*,*,#1961,.F.);
#2944=ORIENTED_EDGE('',*,*,#2890,.T.);
#2945=EDGE_LOOP('',(#2936,#2942,#2943,#2944));
#2946=FACE_BOUND('',#2945,.T.);
#2947=ADVANCED_FACE('F1872',(#2946),#2935,.F.);
#2948=CARTESIAN_POINT('',(0.,-0.38608,-6.65226));
#2949=DIRECTION('',(0.319934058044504,0.,-0.947439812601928));
#2950=DIRECTION('',(-0.947439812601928,0.,-0.319934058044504));
#2951=AXIS2_PLACEMENT_3D('',#2948,#2949,#2950);
#2952=PLANE('',#2951);
#2953=ORIENTED_EDGE('',*,*,#736,.T.);
#2954=DIRECTION('',(0.,1.,0.));
#2955=VECTOR('',#2954,1.);
#2956=CARTESIAN_POINT('',(-0.916532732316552,-0.38608,-6.96175727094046));
#2957=LINE('',#2956,#2955);
#2958=EDGE_CURVE('E1187',#1968,#727,#2957,.T.);
#2959=ORIENTED_EDGE('',*,*,#2958,.F.);
#2960=ORIENTED_EDGE('',*,*,#1969,.F.);
#2961=ORIENTED_EDGE('',*,*,#2941,.T.);
#2962=EDGE_LOOP('',(#2953,#2959,#2960,#2961));
#2963=FACE_BOUND('',#2962,.T.);
#2964=ADVANCED_FACE('F1868',(#2963),#2952,.F.);
#2965=CARTESIAN_POINT('',(-2.77024536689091,-0.38608,-6.68796393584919));
#2966=DIRECTION('',(-0.063817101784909,0.,0.99796161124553));
#2967=DIRECTION('',(0.99796161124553,0.,0.063817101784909));
#2968=AXIS2_PLACEMENT_3D('',#2965,#2966,#2967);
#2969=PLANE('',#2968);
#2970=ORIENTED_EDGE('',*,*,#338,.T.);
#2971=DIRECTION('',(0.,1.,0.));
#2972=VECTOR('',#2971,1.);
#2973=CARTESIAN_POINT('',(-1.77498101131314,-0.38608,-6.62431931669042));
#2974=LINE('',#2973,#2972);
#2975=EDGE_CURVE('E1171',#1583,#329,#2974,.T.);
#2976=ORIENTED_EDGE('',*,*,#2975,.F.);
#2977=ORIENTED_EDGE('',*,*,#1584,.F.);
#2978=DIRECTION('',(0.,1.,0.));
#2979=VECTOR('',#2978,1.);
#2980=CARTESIAN_POINT('',(-2.77024536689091,-0.38608,-6.68796393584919));
#2981=LINE('',#2980,#2979);
#2982=EDGE_CURVE('E1174',#1575,#337,#2981,.T.);
#2983=ORIENTED_EDGE('',*,*,#2982,.T.);
#2984=EDGE_LOOP('',(#2970,#2976,#2977,#2983));
#2985=FACE_BOUND('',#2984,.T.);
#2986=ADVANCED_FACE('F1864',(#2985),#2969,.F.);
#2987=CARTESIAN_POINT('',(-1.77498101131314,-0.38608,-6.62431931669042));
#2988=DIRECTION('',(0.554248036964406,0.,0.832351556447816));
#2989=DIRECTION('',(0.832351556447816,0.,-0.554248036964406));
#2990=AXIS2_PLACEMENT_3D('',#2987,#2988,#2989);
#2991=PLANE('',#2990);
#2992=ORIENTED_EDGE('',*,*,#330,.T.);
#2993=ORIENTED_EDGE('',*,*,#2914,.F.);
#2994=ORIENTED_EDGE('',*,*,#1592,.F.);
#2995=ORIENTED_EDGE('',*,*,#2975,.T.);
#2996=EDGE_LOOP('',(#2992,#2993,#2994,#2995));
#2997=FACE_BOUND('',#2996,.T.);
#2998=ADVANCED_FACE('F1860',(#2997),#2991,.F.);
#2999=CARTESIAN_POINT('',(-0.916532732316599,-0.38608,-6.96175727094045));
#3000=DIRECTION('',(-0.554248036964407,0.,-0.832351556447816));
#3001=DIRECTION('',(-0.832351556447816,0.,0.554248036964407));
#3002=AXIS2_PLACEMENT_3D('',#2999,#3000,#3001);
#3003=PLANE('',#3002);
#3004=ORIENTED_EDGE('',*,*,#728,.T.);
#3005=DIRECTION('',(0.,1.,0.));
#3006=VECTOR('',#3005,1.);
#3007=CARTESIAN_POINT('',(-1.72173158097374,-0.38608,-6.4255897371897));
#3008=LINE('',#3007,#3006);
#3009=EDGE_CURVE('E1168',#1976,#719,#3008,.T.);
#3010=ORIENTED_EDGE('',*,*,#3009,.F.);
#3011=ORIENTED_EDGE('',*,*,#1977,.F.);
#3012=ORIENTED_EDGE('',*,*,#2958,.T.);
#3013=EDGE_LOOP('',(#3004,#3010,#3011,#3012));
#3014=FACE_BOUND('',#3013,.T.);
#3015=ADVANCED_FACE('F1856',(#3014),#3003,.F.);
#3016=CARTESIAN_POINT('',(-1.72173158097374,-0.38608,-6.4255897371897));
#3017=DIRECTION('',(0.0638171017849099,0.,-0.99796161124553));
#3018=DIRECTION('',(-0.99796161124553,0.,-0.0638171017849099));
#3019=AXIS2_PLACEMENT_3D('',#3016,#3017,#3018);
#3020=PLANE('',#3019);
#3021=ORIENTED_EDGE('',*,*,#720,.T.);
#3022=DIRECTION('',(0.,1.,0.));
#3023=VECTOR('',#3022,1.);
#3024=CARTESIAN_POINT('',(-2.68713800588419,-0.38608,-6.48732501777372));
#3025=LINE('',#3024,#3023);
#3026=EDGE_CURVE('E1158',#1984,#711,#3025,.T.);
#3027=ORIENTED_EDGE('',*,*,#3026,.F.);
#3028=ORIENTED_EDGE('',*,*,#1985,.F.);
#3029=ORIENTED_EDGE('',*,*,#3009,.T.);
#3030=EDGE_LOOP('',(#3021,#3027,#3028,#3029));
#3031=FACE_BOUND('',#3030,.T.);
#3032=ADVANCED_FACE('F1852',(#3031),#3020,.F.);
#3033=CARTESIAN_POINT('',(-4.40682398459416,-0.38608,-5.74308483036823));
#3034=DIRECTION('',(0.19664888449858,0.,0.980473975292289));
#3035=DIRECTION('',(0.980473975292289,0.,-0.19664888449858));
#3036=AXIS2_PLACEMENT_3D('',#3033,#3034,#3035);
#3037=PLANE('',#3036);
#3038=ORIENTED_EDGE('',*,*,#354,.T.);
#3039=DIRECTION('',(0.,1.,0.));
#3040=VECTOR('',#3039,1.);
#3041=CARTESIAN_POINT('',(-3.42900000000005,-0.38608,-5.93920221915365));
#3042=LINE('',#3041,#3040);
#3043=EDGE_CURVE('E1142',#1567,#345,#3042,.T.);
#3044=ORIENTED_EDGE('',*,*,#3043,.F.);
#3045=ORIENTED_EDGE('',*,*,#1568,.F.);
#3046=DIRECTION('',(0.,1.,0.));
#3047=VECTOR('',#3046,1.);
#3048=CARTESIAN_POINT('',(-4.40682398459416,-0.38608,-5.74308483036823));
#3049=LINE('',#3048,#3047);
#3050=EDGE_CURVE('E1145',#1559,#353,#3049,.T.);
#3051=ORIENTED_EDGE('',*,*,#3050,.T.);
#3052=EDGE_LOOP('',(#3038,#3044,#3045,#3051));
#3053=FACE_BOUND('',#3052,.T.);
#3054=ADVANCED_FACE('F1848',(#3053),#3037,.F.);
#3055=CARTESIAN_POINT('',(-3.42900000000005,-0.38608,-5.93920221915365));
#3056=DIRECTION('',(0.750790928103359,0.,0.660539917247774));
#3057=DIRECTION('',(0.660539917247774,0.,-0.750790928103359));
#3058=AXIS2_PLACEMENT_3D('',#3055,#3056,#3057);
#3059=PLANE('',#3058);
#3060=ORIENTED_EDGE('',*,*,#346,.T.);
#3061=ORIENTED_EDGE('',*,*,#2982,.F.);
#3062=ORIENTED_EDGE('',*,*,#1576,.F.);
#3063=ORIENTED_EDGE('',*,*,#3043,.T.);
#3064=EDGE_LOOP('',(#3060,#3061,#3062,#3063));
#3065=FACE_BOUND('',#3064,.T.);
#3066=ADVANCED_FACE('F1844',(#3065),#3059,.F.);
#3067=CARTESIAN_POINT('',(-2.68713800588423,-0.38608,-6.4873250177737));
#3068=DIRECTION('',(-0.75079092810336,0.,-0.660539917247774));
#3069=DIRECTION('',(-0.660539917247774,0.,0.75079092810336));
#3070=AXIS2_PLACEMENT_3D('',#3067,#3068,#3069);
#3071=PLANE('',#3070);
#3072=ORIENTED_EDGE('',*,*,#712,.T.);
#3073=DIRECTION('',(0.,1.,0.));
#3074=VECTOR('',#3073,1.);
#3075=CARTESIAN_POINT('',(-3.32613000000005,-0.38608,-5.76102615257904));
#3076=LINE('',#3075,#3074);
#3077=EDGE_CURVE('E1139',#1992,#703,#3076,.T.);
#3078=ORIENTED_EDGE('',*,*,#3077,.F.);
#3079=ORIENTED_EDGE('',*,*,#1993,.F.);
#3080=ORIENTED_EDGE('',*,*,#3026,.T.);
#3081=EDGE_LOOP('',(#3072,#3078,#3079,#3080));
#3082=FACE_BOUND('',#3081,.T.);
#3083=ADVANCED_FACE('F1840',(#3082),#3071,.F.);
#3084=CARTESIAN_POINT('',(-3.32613000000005,-0.38608,-5.76102615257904));
#3085=DIRECTION('',(-0.196648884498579,0.,-0.980473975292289));
#3086=DIRECTION('',(-0.980473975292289,0.,0.196648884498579));
#3087=AXIS2_PLACEMENT_3D('',#3084,#3085,#3086);
#3088=PLANE('',#3087);
#3089=ORIENTED_EDGE('',*,*,#704,.T.);
#3090=DIRECTION('',(0.,1.,0.));
#3091=VECTOR('',#3090,1.);
#3092=CARTESIAN_POINT('',(-4.27461926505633,-0.38608,-5.57079228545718));
#3093=LINE('',#3092,#3091);
#3094=EDGE_CURVE('E1129',#2000,#695,#3093,.T.);
#3095=ORIENTED_EDGE('',*,*,#3094,.F.);
#3096=ORIENTED_EDGE('',*,*,#2001,.F.);
#3097=ORIENTED_EDGE('',*,*,#3077,.T.);
#3098=EDGE_LOOP('',(#3089,#3095,#3096,#3097));
#3099=FACE_BOUND('',#3098,.T.);
#3100=ADVANCED_FACE('F1836',(#3099),#3088,.F.);
#3101=CARTESIAN_POINT('',(-5.74308483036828,-0.38608,-4.4068239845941));
#3102=DIRECTION('',(0.443713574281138,0.,0.896168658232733));
#3103=DIRECTION('',(0.896168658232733,0.,-0.443713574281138));
#3104=AXIS2_PLACEMENT_3D('',#3101,#3102,#3103);
#3105=PLANE('',#3104);
#3106=ORIENTED_EDGE('',*,*,#370,.T.);
#3107=DIRECTION('',(0.,1.,0.));
#3108=VECTOR('',#3107,1.);
#3109=CARTESIAN_POINT('',(-4.84933830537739,-0.38608,-4.8493383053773));
#3110=LINE('',#3109,#3108);
#3111=EDGE_CURVE('E1113',#1551,#361,#3110,.T.);
#3112=ORIENTED_EDGE('',*,*,#3111,.F.);
#3113=ORIENTED_EDGE('',*,*,#1552,.F.);
#3114=DIRECTION('',(0.,1.,0.));
#3115=VECTOR('',#3114,1.);
#3116=CARTESIAN_POINT('',(-5.74308483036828,-0.38608,-4.4068239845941));
#3117=LINE('',#3116,#3115);
#3118=EDGE_CURVE('E1116',#1543,#369,#3117,.T.);
#3119=ORIENTED_EDGE('',*,*,#3118,.T.);
#3120=EDGE_LOOP('',(#3106,#3112,#3113,#3119));
#3121=FACE_BOUND('',#3120,.T.);
#3122=ADVANCED_FACE('F1832',(#3121),#3105,.F.);
#3123=CARTESIAN_POINT('',(-4.84933830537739,-0.38608,-4.8493383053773));
#3124=DIRECTION('',(0.896168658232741,0.,0.443713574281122));
#3125=DIRECTION('',(0.443713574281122,0.,-0.896168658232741));
#3126=AXIS2_PLACEMENT_3D('',#3123,#3124,#3125);
#3127=PLANE('',#3126);
#3128=ORIENTED_EDGE('',*,*,#362,.T.);
#3129=ORIENTED_EDGE('',*,*,#3050,.F.);
#3130=ORIENTED_EDGE('',*,*,#1560,.F.);
#3131=ORIENTED_EDGE('',*,*,#3111,.T.);
#3132=EDGE_LOOP('',(#3128,#3129,#3130,#3131));
#3133=FACE_BOUND('',#3132,.T.);
#3134=ADVANCED_FACE('F1828',(#3133),#3127,.F.);
#3135=CARTESIAN_POINT('',(-4.27461926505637,-0.38608,-5.57079228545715));
#3136=DIRECTION('',(-0.896168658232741,0.,-0.443713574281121));
#3137=DIRECTION('',(-0.443713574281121,0.,0.896168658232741));
#3138=AXIS2_PLACEMENT_3D('',#3135,#3136,#3137);
#3139=PLANE('',#3138);
#3140=ORIENTED_EDGE('',*,*,#696,.T.);
#3141=DIRECTION('',(0.,1.,0.));
#3142=VECTOR('',#3141,1.);
#3143=CARTESIAN_POINT('',(-4.70385815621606,-0.38608,-4.70385815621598));
#3144=LINE('',#3143,#3142);
#3145=EDGE_CURVE('E1110',#2008,#687,#3144,.T.);
#3146=ORIENTED_EDGE('',*,*,#3145,.F.);
#3147=ORIENTED_EDGE('',*,*,#2009,.F.);
#3148=ORIENTED_EDGE('',*,*,#3094,.T.);
#3149=EDGE_LOOP('',(#3140,#3146,#3147,#3148));
#3150=FACE_BOUND('',#3149,.T.);
#3151=ADVANCED_FACE('F1824',(#3150),#3139,.F.);
#3152=CARTESIAN_POINT('',(-4.70385815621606,-0.38608,-4.70385815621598));
#3153=DIRECTION('',(-0.443713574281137,0.,-0.896168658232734));
#3154=DIRECTION('',(-0.896168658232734,0.,0.443713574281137));
#3155=AXIS2_PLACEMENT_3D('',#3152,#3153,#3154);
#3156=PLANE('',#3155);
#3157=ORIENTED_EDGE('',*,*,#688,.T.);
#3158=DIRECTION('',(0.,1.,0.));
#3159=VECTOR('',#3158,1.);
#3160=CARTESIAN_POINT('',(-5.57079228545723,-0.38608,-4.27461926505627));
#3161=LINE('',#3160,#3159);
#3162=EDGE_CURVE('E1100',#2016,#679,#3161,.T.);
#3163=ORIENTED_EDGE('',*,*,#3162,.F.);
#3164=ORIENTED_EDGE('',*,*,#2017,.F.);
#3165=ORIENTED_EDGE('',*,*,#3145,.T.);
#3166=EDGE_LOOP('',(#3157,#3163,#3164,#3165));
#3167=FACE_BOUND('',#3166,.T.);
#3168=ADVANCED_FACE('F1820',(#3167),#3156,.F.);
#3169=CARTESIAN_POINT('',(-6.68796393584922,-0.38608,-2.77024536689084));
#3170=DIRECTION('',(0.660539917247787,0.,0.750790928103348));
#3171=DIRECTION('',(0.750790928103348,0.,-0.660539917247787));
#3172=AXIS2_PLACEMENT_3D('',#3169,#3170,#3171);
#3173=PLANE('',#3172);
#3174=ORIENTED_EDGE('',*,*,#386,.T.);
#3175=DIRECTION('',(0.,1.,0.));
#3176=VECTOR('',#3175,1.);
#3177=CARTESIAN_POINT('',(-5.93920221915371,-0.38608,-3.42899999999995));
#3178=LINE('',#3177,#3176);
#3179=EDGE_CURVE('E1084',#1535,#377,#3178,.T.);
#3180=ORIENTED_EDGE('',*,*,#3179,.F.);
#3181=ORIENTED_EDGE('',*,*,#1536,.F.);
#3182=DIRECTION('',(0.,1.,0.));
#3183=VECTOR('',#3182,1.);
#3184=CARTESIAN_POINT('',(-6.68796393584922,-0.38608,-2.77024536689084));
#3185=LINE('',#3184,#3183);
#3186=EDGE_CURVE('E1087',#1527,#385,#3185,.T.);
#3187=ORIENTED_EDGE('',*,*,#3186,.T.);
#3188=EDGE_LOOP('',(#3174,#3180,#3181,#3187));
#3189=FACE_BOUND('',#3188,.T.);
#3190=ADVANCED_FACE('F1816',(#3189),#3173,.F.);
#3191=CARTESIAN_POINT('',(-5.93920221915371,-0.38608,-3.42899999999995));
#3192=DIRECTION('',(0.980473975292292,0.,0.196648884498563));
#3193=DIRECTION('',(0.196648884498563,0.,-0.980473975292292));
#3194=AXIS2_PLACEMENT_3D('',#3191,#3192,#3193);
#3195=PLANE('',#3194);
#3196=ORIENTED_EDGE('',*,*,#378,.T.);
#3197=ORIENTED_EDGE('',*,*,#3118,.F.);
#3198=ORIENTED_EDGE('',*,*,#1544,.F.);
#3199=ORIENTED_EDGE('',*,*,#3179,.T.);
#3200=EDGE_LOOP('',(#3196,#3197,#3198,#3199));
#3201=FACE_BOUND('',#3200,.T.);
#3202=ADVANCED_FACE('F1812',(#3201),#3195,.F.);
#3203=CARTESIAN_POINT('',(-5.57079228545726,-0.38608,-4.27461926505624));
#3204=DIRECTION('',(-0.980473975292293,0.,-0.196648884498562));
#3205=DIRECTION('',(-0.196648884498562,0.,0.980473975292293));
#3206=AXIS2_PLACEMENT_3D('',#3203,#3204,#3205);
#3207=PLANE('',#3206);
#3208=ORIENTED_EDGE('',*,*,#680,.T.);
#3209=DIRECTION('',(0.,1.,0.));
#3210=VECTOR('',#3209,1.);
#3211=CARTESIAN_POINT('',(-5.7610261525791,-0.38608,-3.32612999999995));
#3212=LINE('',#3211,#3210);
#3213=EDGE_CURVE('E1081',#2024,#671,#3212,.T.);
#3214=ORIENTED_EDGE('',*,*,#3213,.F.);
#3215=ORIENTED_EDGE('',*,*,#2025,.F.);
#3216=ORIENTED_EDGE('',*,*,#3162,.T.);
#3217=EDGE_LOOP('',(#3208,#3214,#3215,#3216));
#3218=FACE_BOUND('',#3217,.T.);
#3219=ADVANCED_FACE('F1808',(#3218),#3207,.F.);
#3220=CARTESIAN_POINT('',(-5.7610261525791,-0.38608,-3.32612999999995));
#3221=DIRECTION('',(-0.660539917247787,0.,-0.750790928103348));
#3222=DIRECTION('',(-0.750790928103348,0.,0.660539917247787));
#3223=AXIS2_PLACEMENT_3D('',#3220,#3221,#3222);
#3224=PLANE('',#3223);
#3225=ORIENTED_EDGE('',*,*,#672,.T.);
#3226=DIRECTION('',(0.,1.,0.));
#3227=VECTOR('',#3226,1.);
#3228=CARTESIAN_POINT('',(-6.48732501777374,-0.38608,-2.68713800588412));
#3229=LINE('',#3228,#3227);
#3230=EDGE_CURVE('E1071',#2032,#663,#3229,.T.);
#3231=ORIENTED_EDGE('',*,*,#3230,.F.);
#3232=ORIENTED_EDGE('',*,*,#2033,.F.);
#3233=ORIENTED_EDGE('',*,*,#3213,.T.);
#3234=EDGE_LOOP('',(#3225,#3231,#3232,#3233));
#3235=FACE_BOUND('',#3234,.T.);
#3236=ADVANCED_FACE('F1804',(#3235),#3224,.F.);
#3237=CARTESIAN_POINT('',(-7.17706935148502,-0.38608,-0.944879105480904));
#3238=DIRECTION('',(0.832351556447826,0.,0.554248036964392));
#3239=DIRECTION('',(0.554248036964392,0.,-0.832351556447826));
#3240=AXIS2_PLACEMENT_3D('',#3237,#3238,#3239);
#3241=PLANE('',#3240);
#3242=ORIENTED_EDGE('',*,*,#402,.T.);
#3243=DIRECTION('',(0.,1.,0.));
#3244=VECTOR('',#3243,1.);
#3245=CARTESIAN_POINT('',(-6.62431931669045,-0.38608,-1.77498101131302));
#3246=LINE('',#3245,#3244);
#3247=EDGE_CURVE('E1055',#1519,#393,#3246,.T.);
#3248=ORIENTED_EDGE('',*,*,#3247,.F.);
#3249=ORIENTED_EDGE('',*,*,#1520,.F.);
#3250=DIRECTION('',(0.,1.,0.));
#3251=VECTOR('',#3250,1.);
#3252=CARTESIAN_POINT('',(-7.17706935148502,-0.38608,-0.944879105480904));
#3253=LINE('',#3252,#3251);
#3254=EDGE_CURVE('E1058',#1511,#401,#3253,.T.);
#3255=ORIENTED_EDGE('',*,*,#3254,.T.);
#3256=EDGE_LOOP('',(#3242,#3248,#3249,#3255));
#3257=FACE_BOUND('',#3256,.T.);
#3258=ADVANCED_FACE('F1800',(#3257),#3241,.F.);
#3259=CARTESIAN_POINT('',(-6.62431931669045,-0.38608,-1.77498101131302));
#3260=DIRECTION('',(0.997961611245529,0.,-0.0638171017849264));
#3261=DIRECTION('',(-0.0638171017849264,0.,-0.997961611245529));
#3262=AXIS2_PLACEMENT_3D('',#3259,#3260,#3261);
#3263=PLANE('',#3262);
#3264=ORIENTED_EDGE('',*,*,#394,.T.);
#3265=ORIENTED_EDGE('',*,*,#3186,.F.);
#3266=ORIENTED_EDGE('',*,*,#1528,.F.);
#3267=ORIENTED_EDGE('',*,*,#3247,.T.);
#3268=EDGE_LOOP('',(#3264,#3265,#3266,#3267));
#3269=FACE_BOUND('',#3268,.T.);
#3270=ADVANCED_FACE('F1796',(#3269),#3263,.F.);
#3271=CARTESIAN_POINT('',(-6.48732501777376,-0.38608,-2.68713800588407));
#3272=DIRECTION('',(-0.997961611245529,0.,0.0638171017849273));
#3273=DIRECTION('',(0.0638171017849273,0.,0.997961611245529));
#3274=AXIS2_PLACEMENT_3D('',#3271,#3272,#3273);
#3275=PLANE('',#3274);
#3276=ORIENTED_EDGE('',*,*,#664,.T.);
#3277=DIRECTION('',(0.,1.,0.));
#3278=VECTOR('',#3277,1.);
#3279=CARTESIAN_POINT('',(-6.42558973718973,-0.38608,-1.72173158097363));
#3280=LINE('',#3279,#3278);
#3281=EDGE_CURVE('E1052',#2040,#655,#3280,.T.);
#3282=ORIENTED_EDGE('',*,*,#3281,.F.);
#3283=ORIENTED_EDGE('',*,*,#2041,.F.);
#3284=ORIENTED_EDGE('',*,*,#3230,.T.);
#3285=EDGE_LOOP('',(#3276,#3282,#3283,#3284));
#3286=FACE_BOUND('',#3285,.T.);
#3287=ADVANCED_FACE('F1792',(#3286),#3275,.F.);
#3288=CARTESIAN_POINT('',(-6.42558973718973,-0.38608,-1.72173158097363));
#3289=DIRECTION('',(-0.832351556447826,0.,-0.554248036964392));
#3290=DIRECTION('',(-0.554248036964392,0.,0.832351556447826));
#3291=AXIS2_PLACEMENT_3D('',#3288,#3289,#3290);
#3292=PLANE('',#3291);
#3293=ORIENTED_EDGE('',*,*,#656,.T.);
#3294=DIRECTION('',(0.,1.,0.));
#3295=VECTOR('',#3294,1.);
#3296=CARTESIAN_POINT('',(-6.96175727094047,-0.38608,-0.916532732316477));
#3297=LINE('',#3296,#3295);
#3298=EDGE_CURVE('E1042',#2048,#647,#3297,.T.);
#3299=ORIENTED_EDGE('',*,*,#3298,.F.);
#3300=ORIENTED_EDGE('',*,*,#2049,.F.);
#3301=ORIENTED_EDGE('',*,*,#3281,.T.);
#3302=EDGE_LOOP('',(#3293,#3299,#3300,#3301));
#3303=FACE_BOUND('',#3302,.T.);
#3304=ADVANCED_FACE('F1788',(#3303),#3292,.F.);
#3305=CARTESIAN_POINT('',(-7.17706935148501,-0.38608,0.944879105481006));
#3306=DIRECTION('',(0.947439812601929,0.,0.3199340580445));
#3307=DIRECTION('',(0.3199340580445,0.,-0.947439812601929));
#3308=AXIS2_PLACEMENT_3D('',#3305,#3306,#3307);
#3309=PLANE('',#3308);
#3310=ORIENTED_EDGE('',*,*,#418,.T.);
#3311=DIRECTION('',(0.,1.,0.));
#3312=VECTOR('',#3311,1.);
#3313=CARTESIAN_POINT('',(-6.858,-0.38608,0.));
#3314=LINE('',#3313,#3312);
#3315=EDGE_CURVE('E1026',#1503,#409,#3314,.T.);
#3316=ORIENTED_EDGE('',*,*,#3315,.F.);
#3317=ORIENTED_EDGE('',*,*,#1504,.F.);
#3318=DIRECTION('',(0.,1.,0.));
#3319=VECTOR('',#3318,1.);
#3320=CARTESIAN_POINT('',(-7.17706935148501,-0.38608,0.944879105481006));
#3321=LINE('',#3320,#3319);
#3322=EDGE_CURVE('E1029',#1495,#417,#3321,.T.);
#3323=ORIENTED_EDGE('',*,*,#3322,.T.);
#3324=EDGE_LOOP('',(#3310,#3316,#3317,#3323));
#3325=FACE_BOUND('',#3324,.T.);
#3326=ADVANCED_FACE('F1784',(#3325),#3309,.F.);
#3327=CARTESIAN_POINT('',(-6.858,-0.38608,0.));
#3328=DIRECTION('',(0.947439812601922,0.,-0.31993405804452));
#3329=DIRECTION('',(-0.31993405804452,0.,-0.947439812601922));
#3330=AXIS2_PLACEMENT_3D('',#3327,#3328,#3329);
#3331=PLANE('',#3330);
#3332=ORIENTED_EDGE('',*,*,#410,.T.);
#3333=ORIENTED_EDGE('',*,*,#3254,.F.);
#3334=ORIENTED_EDGE('',*,*,#1512,.F.);
#3335=ORIENTED_EDGE('',*,*,#3315,.T.);
#3336=EDGE_LOOP('',(#3332,#3333,#3334,#3335));
#3337=FACE_BOUND('',#3336,.T.);
#3338=ADVANCED_FACE('F1780',(#3337),#3331,.F.);
#3339=CARTESIAN_POINT('',(-6.96175727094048,-0.38608,-0.91653273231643));
#3340=DIRECTION('',(-0.947439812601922,0.,0.319934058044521));
#3341=DIRECTION('',(0.319934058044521,0.,0.947439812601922));
#3342=AXIS2_PLACEMENT_3D('',#3339,#3340,#3341);
#3343=PLANE('',#3342);
#3344=ORIENTED_EDGE('',*,*,#648,.T.);
#3345=DIRECTION('',(0.,1.,0.));
#3346=VECTOR('',#3345,1.);
#3347=CARTESIAN_POINT('',(-6.65226,-0.38608,0.));
#3348=LINE('',#3347,#3346);
#3349=EDGE_CURVE('E1023',#2056,#639,#3348,.T.);
#3350=ORIENTED_EDGE('',*,*,#3349,.F.);
#3351=ORIENTED_EDGE('',*,*,#2057,.F.);
#3352=ORIENTED_EDGE('',*,*,#3298,.T.);
#3353=EDGE_LOOP('',(#3344,#3350,#3351,#3352));
#3354=FACE_BOUND('',#3353,.T.);
#3355=ADVANCED_FACE('F1776',(#3354),#3343,.F.);
#3356=CARTESIAN_POINT('',(-6.65226,-0.38608,0.));
#3357=DIRECTION('',(-0.947439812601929,0.,-0.319934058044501));
#3358=DIRECTION('',(-0.319934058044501,0.,0.947439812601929));
#3359=AXIS2_PLACEMENT_3D('',#3356,#3357,#3358);
#3360=PLANE('',#3359);
#3361=ORIENTED_EDGE('',*,*,#640,.T.);
#3362=DIRECTION('',(0.,1.,0.));
#3363=VECTOR('',#3362,1.);
#3364=CARTESIAN_POINT('',(-6.96175727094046,-0.38608,0.916532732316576));
#3365=LINE('',#3364,#3363);
#3366=EDGE_CURVE('E1013',#2064,#631,#3365,.T.);
#3367=ORIENTED_EDGE('',*,*,#3366,.F.);
#3368=ORIENTED_EDGE('',*,*,#2065,.F.);
#3369=ORIENTED_EDGE('',*,*,#3349,.T.);
#3370=EDGE_LOOP('',(#3361,#3367,#3368,#3369));
#3371=FACE_BOUND('',#3370,.T.);
#3372=ADVANCED_FACE('F1772',(#3371),#3360,.F.);
#3373=CARTESIAN_POINT('',(-6.68796393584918,-0.38608,2.77024536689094));
#3374=DIRECTION('',(0.99796161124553,0.,0.0638171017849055));
#3375=DIRECTION('',(0.0638171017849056,0.,-0.997961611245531));
#3376=AXIS2_PLACEMENT_3D('',#3373,#3374,#3375);
#3377=PLANE('',#3376);
#3378=ORIENTED_EDGE('',*,*,#434,.T.);
#3379=DIRECTION('',(0.,1.,0.));
#3380=VECTOR('',#3379,1.);
#3381=CARTESIAN_POINT('',(-6.62431931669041,-0.38608,1.77498101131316));
#3382=LINE('',#3381,#3380);
#3383=EDGE_CURVE('E997',#1487,#425,#3382,.T.);
#3384=ORIENTED_EDGE('',*,*,#3383,.F.);
#3385=ORIENTED_EDGE('',*,*,#1488,.F.);
#3386=DIRECTION('',(0.,1.,0.));
#3387=VECTOR('',#3386,1.);
#3388=CARTESIAN_POINT('',(-6.68796393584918,-0.38608,2.77024536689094));
#3389=LINE('',#3388,#3387);
#3390=EDGE_CURVE('E1000',#1479,#433,#3389,.T.);
#3391=ORIENTED_EDGE('',*,*,#3390,.T.);
#3392=EDGE_LOOP('',(#3378,#3384,#3385,#3391));
#3393=FACE_BOUND('',#3392,.T.);
#3394=ADVANCED_FACE('F1768',(#3393),#3377,.F.);
#3395=CARTESIAN_POINT('',(-6.62431931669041,-0.38608,1.77498101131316));
#3396=DIRECTION('',(0.832351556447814,0.,-0.554248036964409));
#3397=DIRECTION('',(-0.554248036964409,0.,-0.832351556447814));
#3398=AXIS2_PLACEMENT_3D('',#3395,#3396,#3397);
#3399=PLANE('',#3398);
#3400=ORIENTED_EDGE('',*,*,#426,.T.);
#3401=ORIENTED_EDGE('',*,*,#3322,.F.);
#3402=ORIENTED_EDGE('',*,*,#1496,.F.);
#3403=ORIENTED_EDGE('',*,*,#3383,.T.);
#3404=EDGE_LOOP('',(#3400,#3401,#3402,#3403));
#3405=FACE_BOUND('',#3404,.T.);
#3406=ADVANCED_FACE('F1764',(#3405),#3399,.F.);
#3407=CARTESIAN_POINT('',(-6.96175727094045,-0.38608,0.916532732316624));
#3408=DIRECTION('',(-0.832351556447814,0.,0.55424803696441));
#3409=DIRECTION('',(0.55424803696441,0.,0.832351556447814));
#3410=AXIS2_PLACEMENT_3D('',#3407,#3408,#3409);
#3411=PLANE('',#3410);
#3412=ORIENTED_EDGE('',*,*,#632,.T.);
#3413=DIRECTION('',(0.,1.,0.));
#3414=VECTOR('',#3413,1.);
#3415=CARTESIAN_POINT('',(-6.4255897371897,-0.38608,1.72173158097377));
#3416=LINE('',#3415,#3414);
#3417=EDGE_CURVE('E994',#2072,#623,#3416,.T.);
#3418=ORIENTED_EDGE('',*,*,#3417,.F.);
#3419=ORIENTED_EDGE('',*,*,#2073,.F.);
#3420=ORIENTED_EDGE('',*,*,#3366,.T.);
#3421=EDGE_LOOP('',(#3412,#3418,#3419,#3420));
#3422=FACE_BOUND('',#3421,.T.);
#3423=ADVANCED_FACE('F1760',(#3422),#3411,.F.);
#3424=CARTESIAN_POINT('',(-6.4255897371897,-0.38608,1.72173158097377));
#3425=DIRECTION('',(-0.99796161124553,0.,-0.0638171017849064));
#3426=DIRECTION('',(-0.0638171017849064,0.,0.99796161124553));
#3427=AXIS2_PLACEMENT_3D('',#3424,#3425,#3426);
#3428=PLANE('',#3427);
#3429=ORIENTED_EDGE('',*,*,#624,.T.);
#3430=DIRECTION('',(0.,1.,0.));
#3431=VECTOR('',#3430,1.);
#3432=CARTESIAN_POINT('',(-6.48732501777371,-0.38608,2.68713800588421));
#3433=LINE('',#3432,#3431);
#3434=EDGE_CURVE('E984',#2080,#615,#3433,.T.);
#3435=ORIENTED_EDGE('',*,*,#3434,.F.);
#3436=ORIENTED_EDGE('',*,*,#2081,.F.);
#3437=ORIENTED_EDGE('',*,*,#3417,.T.);
#3438=EDGE_LOOP('',(#3429,#3435,#3436,#3437));
#3439=FACE_BOUND('',#3438,.T.);
#3440=ADVANCED_FACE('F1756',(#3439),#3428,.F.);
#3441=CARTESIAN_POINT('',(-5.74308483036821,-0.38608,4.40682398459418));
#3442=DIRECTION('',(0.980473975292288,0.,-0.196648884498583));
#3443=DIRECTION('',(-0.196648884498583,0.,-0.980473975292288));
#3444=AXIS2_PLACEMENT_3D('',#3441,#3442,#3443);
#3445=PLANE('',#3444);
#3446=ORIENTED_EDGE('',*,*,#450,.T.);
#3447=DIRECTION('',(0.,1.,0.));
#3448=VECTOR('',#3447,1.);
#3449=CARTESIAN_POINT('',(-5.93920221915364,-0.38608,3.42900000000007));
#3450=LINE('',#3449,#3448);
#3451=EDGE_CURVE('E968',#1471,#441,#3450,.T.);
#3452=ORIENTED_EDGE('',*,*,#3451,.F.);
#3453=ORIENTED_EDGE('',*,*,#1472,.F.);
#3454=DIRECTION('',(0.,1.,0.));
#3455=VECTOR('',#3454,1.);
#3456=CARTESIAN_POINT('',(-5.74308483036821,-0.38608,4.40682398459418));
#3457=LINE('',#3456,#3455);
#3458=EDGE_CURVE('E971',#1463,#449,#3457,.T.);
#3459=ORIENTED_EDGE('',*,*,#3458,.T.);
#3460=EDGE_LOOP('',(#3446,#3452,#3453,#3459));
#3461=FACE_BOUND('',#3460,.T.);
#3462=ADVANCED_FACE('F1752',(#3461),#3445,.F.);
#3463=CARTESIAN_POINT('',(-5.93920221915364,-0.38608,3.42900000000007));
#3464=DIRECTION('',(0.660539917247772,0.,-0.750790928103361));
#3465=DIRECTION('',(-0.750790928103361,0.,-0.660539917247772));
#3466=AXIS2_PLACEMENT_3D('',#3463,#3464,#3465);
#3467=PLANE('',#3466);
#3468=ORIENTED_EDGE('',*,*,#442,.T.);
#3469=ORIENTED_EDGE('',*,*,#3390,.F.);
#3470=ORIENTED_EDGE('',*,*,#1480,.F.);
#3471=ORIENTED_EDGE('',*,*,#3451,.T.);
#3472=EDGE_LOOP('',(#3468,#3469,#3470,#3471));
#3473=FACE_BOUND('',#3472,.T.);
#3474=ADVANCED_FACE('F1748',(#3473),#3467,.F.);
#3475=CARTESIAN_POINT('',(-6.48732501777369,-0.38608,2.68713800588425));
#3476=DIRECTION('',(-0.660539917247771,0.,0.750790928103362));
#3477=DIRECTION('',(0.750790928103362,0.,0.660539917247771));
#3478=AXIS2_PLACEMENT_3D('',#3475,#3476,#3477);
#3479=PLANE('',#3478);
#3480=ORIENTED_EDGE('',*,*,#616,.T.);
#3481=DIRECTION('',(0.,1.,0.));
#3482=VECTOR('',#3481,1.);
#3483=CARTESIAN_POINT('',(-5.76102615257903,-0.38608,3.32613000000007));
#3484=LINE('',#3483,#3482);
#3485=EDGE_CURVE('E965',#2088,#607,#3484,.T.);
#3486=ORIENTED_EDGE('',*,*,#3485,.F.);
#3487=ORIENTED_EDGE('',*,*,#2089,.F.);
#3488=ORIENTED_EDGE('',*,*,#3434,.T.);
#3489=EDGE_LOOP('',(#3480,#3486,#3487,#3488));
#3490=FACE_BOUND('',#3489,.T.);
#3491=ADVANCED_FACE('F1744',(#3490),#3479,.F.);
#3492=CARTESIAN_POINT('',(-5.76102615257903,-0.38608,3.32613000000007));
#3493=DIRECTION('',(-0.980473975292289,0.,0.196648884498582));
#3494=DIRECTION('',(0.196648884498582,0.,0.980473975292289));
#3495=AXIS2_PLACEMENT_3D('',#3492,#3493,#3494);
#3496=PLANE('',#3495);
#3497=ORIENTED_EDGE('',*,*,#608,.T.);
#3498=DIRECTION('',(0.,1.,0.));
#3499=VECTOR('',#3498,1.);
#3500=CARTESIAN_POINT('',(-5.57079228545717,-0.38608,4.27461926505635));
#3501=LINE('',#3500,#3499);
#3502=EDGE_CURVE('E955',#2096,#599,#3501,.T.);
#3503=ORIENTED_EDGE('',*,*,#3502,.F.);
#3504=ORIENTED_EDGE('',*,*,#2097,.F.);
#3505=ORIENTED_EDGE('',*,*,#3485,.T.);
#3506=EDGE_LOOP('',(#3497,#3503,#3504,#3505));
#3507=FACE_BOUND('',#3506,.T.);
#3508=ADVANCED_FACE('F1740',(#3507),#3496,.F.);
#3509=CARTESIAN_POINT('',(-4.40682398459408,-0.38608,5.74308483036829));
#3510=DIRECTION('',(0.896168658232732,0.,-0.443713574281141));
#3511=DIRECTION('',(-0.443713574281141,0.,-0.896168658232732));
#3512=AXIS2_PLACEMENT_3D('',#3509,#3510,#3511);
#3513=PLANE('',#3512);
#3514=ORIENTED_EDGE('',*,*,#466,.T.);
#3515=DIRECTION('',(0.,1.,0.));
#3516=VECTOR('',#3515,1.);
#3517=CARTESIAN_POINT('',(-4.84933830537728,-0.38608,4.8493383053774));
#3518=LINE('',#3517,#3516);
#3519=EDGE_CURVE('E939',#1455,#457,#3518,.T.);
#3520=ORIENTED_EDGE('',*,*,#3519,.F.);
#3521=ORIENTED_EDGE('',*,*,#1456,.F.);
#3522=DIRECTION('',(0.,1.,0.));
#3523=VECTOR('',#3522,1.);
#3524=CARTESIAN_POINT('',(-4.40682398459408,-0.38608,5.74308483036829));
#3525=LINE('',#3524,#3523);
#3526=EDGE_CURVE('E942',#1447,#465,#3525,.T.);
#3527=ORIENTED_EDGE('',*,*,#3526,.T.);
#3528=EDGE_LOOP('',(#3514,#3520,#3521,#3527));
#3529=FACE_BOUND('',#3528,.T.);
#3530=ADVANCED_FACE('F1736',(#3529),#3513,.F.);
#3531=CARTESIAN_POINT('',(-4.84933830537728,-0.38608,4.8493383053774));
#3532=DIRECTION('',(0.443713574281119,0.,-0.896168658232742));
#3533=DIRECTION('',(-0.896168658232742,0.,-0.443713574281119));
#3534=AXIS2_PLACEMENT_3D('',#3531,#3532,#3533);
#3535=PLANE('',#3534);
#3536=ORIENTED_EDGE('',*,*,#458,.T.);
#3537=ORIENTED_EDGE('',*,*,#3458,.F.);
#3538=ORIENTED_EDGE('',*,*,#1464,.F.);
#3539=ORIENTED_EDGE('',*,*,#3519,.T.);
#3540=EDGE_LOOP('',(#3536,#3537,#3538,#3539));
#3541=FACE_BOUND('',#3540,.T.);
#3542=ADVANCED_FACE('F1732',(#3541),#3535,.F.);
#3543=CARTESIAN_POINT('',(-5.57079228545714,-0.38608,4.27461926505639));
#3544=DIRECTION('',(-0.443713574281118,0.,0.896168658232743));
#3545=DIRECTION('',(0.896168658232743,0.,0.443713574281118));
#3546=AXIS2_PLACEMENT_3D('',#3543,#3544,#3545);
#3547=PLANE('',#3546);
#3548=ORIENTED_EDGE('',*,*,#600,.T.);
#3549=DIRECTION('',(0.,1.,0.));
#3550=VECTOR('',#3549,1.);
#3551=CARTESIAN_POINT('',(-4.70385815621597,-0.38608,4.70385815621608));
#3552=LINE('',#3551,#3550);
#3553=EDGE_CURVE('E936',#2104,#591,#3552,.T.);
#3554=ORIENTED_EDGE('',*,*,#3553,.F.);
#3555=ORIENTED_EDGE('',*,*,#2105,.F.);
#3556=ORIENTED_EDGE('',*,*,#3502,.T.);
#3557=EDGE_LOOP('',(#3548,#3554,#3555,#3556));
#3558=FACE_BOUND('',#3557,.T.);
#3559=ADVANCED_FACE('F1728',(#3558),#3547,.F.);
#3560=CARTESIAN_POINT('',(-4.70385815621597,-0.38608,4.70385815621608));
#3561=DIRECTION('',(-0.896168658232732,0.,0.44371357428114));
#3562=DIRECTION('',(0.44371357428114,0.,0.896168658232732));
#3563=AXIS2_PLACEMENT_3D('',#3560,#3561,#3562);
#3564=PLANE('',#3563);
#3565=ORIENTED_EDGE('',*,*,#592,.T.);
#3566=DIRECTION('',(0.,1.,0.));
#3567=VECTOR('',#3566,1.);
#3568=CARTESIAN_POINT('',(-4.27461926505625,-0.38608,5.57079228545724));
#3569=LINE('',#3568,#3567);
#3570=EDGE_CURVE('E926',#2112,#583,#3569,.T.);
#3571=ORIENTED_EDGE('',*,*,#3570,.F.);
#3572=ORIENTED_EDGE('',*,*,#2113,.F.);
#3573=ORIENTED_EDGE('',*,*,#3553,.T.);
#3574=EDGE_LOOP('',(#3565,#3571,#3572,#3573));
#3575=FACE_BOUND('',#3574,.T.);
#3576=ADVANCED_FACE('F1724',(#3575),#3564,.F.);
#3577=CARTESIAN_POINT('',(-2.77024536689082,-0.38608,6.68796393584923));
#3578=DIRECTION('',(0.750790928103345,0.,-0.66053991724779));
#3579=DIRECTION('',(-0.66053991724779,0.,-0.750790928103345));
#3580=AXIS2_PLACEMENT_3D('',#3577,#3578,#3579);
#3581=PLANE('',#3580);
#3582=ORIENTED_EDGE('',*,*,#482,.T.);
#3583=DIRECTION('',(0.,1.,0.));
#3584=VECTOR('',#3583,1.);
#3585=CARTESIAN_POINT('',(-3.42899999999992,-0.38608,5.93920221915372));
#3586=LINE('',#3585,#3584);
#3587=EDGE_CURVE('E910',#1439,#473,#3586,.T.);
#3588=ORIENTED_EDGE('',*,*,#3587,.F.);
#3589=ORIENTED_EDGE('',*,*,#1440,.F.);
#3590=DIRECTION('',(0.,1.,0.));
#3591=VECTOR('',#3590,1.);
#3592=CARTESIAN_POINT('',(-2.77024536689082,-0.38608,6.68796393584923));
#3593=LINE('',#3592,#3591);
#3594=EDGE_CURVE('E913',#1431,#481,#3593,.T.);
#3595=ORIENTED_EDGE('',*,*,#3594,.T.);
#3596=EDGE_LOOP('',(#3582,#3588,#3589,#3595));
#3597=FACE_BOUND('',#3596,.T.);
#3598=ADVANCED_FACE('F1720',(#3597),#3581,.F.);
#3599=CARTESIAN_POINT('',(-3.42899999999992,-0.38608,5.93920221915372));
#3600=DIRECTION('',(0.196648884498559,0.,-0.980473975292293));
#3601=DIRECTION('',(-0.980473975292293,0.,-0.196648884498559));
#3602=AXIS2_PLACEMENT_3D('',#3599,#3600,#3601);
#3603=PLANE('',#3602);
#3604=ORIENTED_EDGE('',*,*,#474,.T.);
#3605=ORIENTED_EDGE('',*,*,#3526,.F.);
#3606=ORIENTED_EDGE('',*,*,#1448,.F.);
#3607=ORIENTED_EDGE('',*,*,#3587,.T.);
#3608=EDGE_LOOP('',(#3604,#3605,#3606,#3607));
#3609=FACE_BOUND('',#3608,.T.);
#3610=ADVANCED_FACE('F1716',(#3609),#3603,.F.);
#3611=CARTESIAN_POINT('',(-4.27461926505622,-0.38608,5.57079228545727));
#3612=DIRECTION('',(-0.196648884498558,0.,0.980473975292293));
#3613=DIRECTION('',(0.980473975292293,0.,0.196648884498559));
#3614=AXIS2_PLACEMENT_3D('',#3611,#3612,#3613);
#3615=PLANE('',#3614);
#3616=ORIENTED_EDGE('',*,*,#584,.T.);
#3617=DIRECTION('',(0.,1.,0.));
#3618=VECTOR('',#3617,1.);
#3619=CARTESIAN_POINT('',(-3.32612999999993,-0.38608,5.76102615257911));
#3620=LINE('',#3619,#3618);
#3621=EDGE_CURVE('E907',#2120,#575,#3620,.T.);
#3622=ORIENTED_EDGE('',*,*,#3621,.F.);
#3623=ORIENTED_EDGE('',*,*,#2121,.F.);
#3624=ORIENTED_EDGE('',*,*,#3570,.T.);
#3625=EDGE_LOOP('',(#3616,#3622,#3623,#3624));
#3626=FACE_BOUND('',#3625,.T.);
#3627=ADVANCED_FACE('F1712',(#3626),#3615,.F.);
#3628=CARTESIAN_POINT('',(-3.32612999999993,-0.38608,5.76102615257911));
#3629=DIRECTION('',(-0.750790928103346,0.,0.660539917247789));
#3630=DIRECTION('',(0.660539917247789,0.,0.750790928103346));
#3631=AXIS2_PLACEMENT_3D('',#3628,#3629,#3630);
#3632=PLANE('',#3631);
#3633=ORIENTED_EDGE('',*,*,#576,.T.);
#3634=DIRECTION('',(0.,1.,0.));
#3635=VECTOR('',#3634,1.);
#3636=CARTESIAN_POINT('',(-2.6871380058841,-0.38608,6.48732501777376));
#3637=LINE('',#3636,#3635);
#3638=EDGE_CURVE('E897',#2128,#567,#3637,.T.);
#3639=ORIENTED_EDGE('',*,*,#3638,.F.);
#3640=ORIENTED_EDGE('',*,*,#2129,.F.);
#3641=ORIENTED_EDGE('',*,*,#3621,.T.);
#3642=EDGE_LOOP('',(#3633,#3639,#3640,#3641));
#3643=FACE_BOUND('',#3642,.T.);
#3644=ADVANCED_FACE('F1708',(#3643),#3632,.F.);
#3645=CARTESIAN_POINT('',(-0.94487910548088,-0.38608,7.17706935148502));
#3646=DIRECTION('',(0.554248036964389,0.,-0.832351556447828));
#3647=DIRECTION('',(-0.832351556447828,0.,-0.554248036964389));
#3648=AXIS2_PLACEMENT_3D('',#3645,#3646,#3647);
#3649=PLANE('',#3648);
#3650=ORIENTED_EDGE('',*,*,#498,.T.);
#3651=DIRECTION('',(0.,1.,0.));
#3652=VECTOR('',#3651,1.);
#3653=CARTESIAN_POINT('',(-1.774981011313,-0.38608,6.62431931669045));
#3654=LINE('',#3653,#3652);
#3655=EDGE_CURVE('E883',#1423,#489,#3654,.T.);
#3656=ORIENTED_EDGE('',*,*,#3655,.F.);
#3657=ORIENTED_EDGE('',*,*,#1424,.F.);
#3658=ORIENTED_EDGE('',*,*,#1336,.T.);
#3659=EDGE_LOOP('',(#3650,#3656,#3657,#3658));
#3660=FACE_BOUND('',#3659,.T.);
#3661=ADVANCED_FACE('F1704',(#3660),#3649,.F.);
#3662=CARTESIAN_POINT('',(-1.774981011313,-0.38608,6.62431931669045));
#3663=DIRECTION('',(-0.0638171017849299,0.,-0.997961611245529));
#3664=DIRECTION('',(-0.997961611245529,0.,0.0638171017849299));
#3665=AXIS2_PLACEMENT_3D('',#3662,#3663,#3664);
#3666=PLANE('',#3665);
#3667=ORIENTED_EDGE('',*,*,#490,.T.);
#3668=ORIENTED_EDGE('',*,*,#3594,.F.);
#3669=ORIENTED_EDGE('',*,*,#1432,.F.);
#3670=ORIENTED_EDGE('',*,*,#3655,.T.);
#3671=EDGE_LOOP('',(#3667,#3668,#3669,#3670));
#3672=FACE_BOUND('',#3671,.T.);
#3673=ADVANCED_FACE('F1700',(#3672),#3666,.F.);
#3674=CARTESIAN_POINT('',(-2.68713800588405,-0.38608,6.48732501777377));
#3675=DIRECTION('',(0.0638171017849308,0.,0.997961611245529));
#3676=DIRECTION('',(0.997961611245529,0.,-0.0638171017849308));
#3677=AXIS2_PLACEMENT_3D('',#3674,#3675,#3676);
#3678=PLANE('',#3677);
#3679=ORIENTED_EDGE('',*,*,#568,.T.);
#3680=DIRECTION('',(0.,1.,0.));
#3681=VECTOR('',#3680,1.);
#3682=CARTESIAN_POINT('',(-1.72173158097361,-0.38608,6.42558973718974));
#3683=LINE('',#3682,#3681);
#3684=EDGE_CURVE('E873',#2136,#559,#3683,.T.);
#3685=ORIENTED_EDGE('',*,*,#3684,.F.);
#3686=ORIENTED_EDGE('',*,*,#2137,.F.);
#3687=ORIENTED_EDGE('',*,*,#3638,.T.);
#3688=EDGE_LOOP('',(#3679,#3685,#3686,#3687));
#3689=FACE_BOUND('',#3688,.T.);
#3690=ADVANCED_FACE('F1696',(#3689),#3678,.F.);
#3691=CARTESIAN_POINT('',(-1.72173158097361,-0.38608,6.42558973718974));
#3692=DIRECTION('',(-0.554248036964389,0.,0.832351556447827));
#3693=DIRECTION('',(0.832351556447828,0.,0.55424803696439));
#3694=AXIS2_PLACEMENT_3D('',#3691,#3692,#3693);
#3695=PLANE('',#3694);
#3696=ORIENTED_EDGE('',*,*,#560,.T.);
#3697=ORIENTED_EDGE('',*,*,#1374,.F.);
#3698=ORIENTED_EDGE('',*,*,#2143,.F.);
#3699=ORIENTED_EDGE('',*,*,#3684,.T.);
#3700=EDGE_LOOP('',(#3696,#3697,#3698,#3699));
#3701=FACE_BOUND('',#3700,.T.);
#3702=ADVANCED_FACE('F1693',(#3701),#3695,.F.);
#3703=CARTESIAN_POINT('',(-3.556,0.,-3.556));
#3704=DIRECTION('',(0.,-1.,0.));
#3705=DIRECTION('',(0.,0.,-1.));
#3706=AXIS2_PLACEMENT_3D('',#3703,#3704,#3705);
#3707=CYLINDRICAL_SURFACE('',#3706,0.635);
#3708=ORIENTED_EDGE('',*,*,#1124,.T.);
#3709=DIRECTION('',(0.,-1.,0.));
#3710=VECTOR('',#3709,1.);
#3711=CARTESIAN_POINT('',(-3.556,0.,-4.191));
#3712=LINE('',#3711,#3710);
#3713=CARTESIAN_POINT('',(-3.556,0.,-4.191));
#3714=VERTEX_POINT('',#3713);
#3715=EDGE_CURVE('E824',#3714,#1123,#3712,.T.);
#3716=ORIENTED_EDGE('',*,*,#3715,.F.);
#3717=CARTESIAN_POINT('',(-3.556,0.,-3.556));
#3718=DIRECTION('',(0.,-1.,0.));
#3719=DIRECTION('',(0.,0.,-1.));
#3720=AXIS2_PLACEMENT_3D('',#3717,#3718,#3719);
#3721=CIRCLE('',#3720,0.635);
#3722=CARTESIAN_POINT('',(-4.191,0.,-3.556));
#3723=VERTEX_POINT('',#3722);
#3724=EDGE_CURVE('E799',#3723,#3714,#3721,.T.);
#3725=ORIENTED_EDGE('',*,*,#3724,.F.);
#3726=DIRECTION('',(0.,-1.,0.));
#3727=VECTOR('',#3726,1.);
#3728=CARTESIAN_POINT('',(-4.191,0.,-3.556));
#3729=LINE('',#3728,#3727);
#3730=EDGE_CURVE('E846',#3723,#1121,#3729,.T.);
#3731=ORIENTED_EDGE('',*,*,#3730,.T.);
#3732=EDGE_LOOP('',(#3708,#3716,#3725,#3731));
#3733=FACE_BOUND('',#3732,.T.);
#3734=ADVANCED_FACE('F1661',(#3733),#3707,.F.);
#3735=CARTESIAN_POINT('',(-4.191,0.,3.556));
#3736=DIRECTION('',(-1.,0.,0.));
#3737=DIRECTION('',(0.,0.,1.));
#3738=AXIS2_PLACEMENT_3D('',#3735,#3736,#3737);
#3739=PLANE('',#3738);
#3740=ORIENTED_EDGE('',*,*,#1132,.T.);
#3741=ORIENTED_EDGE('',*,*,#3730,.F.);
#3742=DIRECTION('',(0.,0.,-1.));
#3743=VECTOR('',#3742,1.);
#3744=CARTESIAN_POINT('',(-4.191,0.,3.556));
#3745=LINE('',#3744,#3743);
#3746=CARTESIAN_POINT('',(-4.191,0.,3.556));
#3747=VERTEX_POINT('',#3746);
#3748=EDGE_CURVE('E821',#3747,#3723,#3745,.T.);
#3749=ORIENTED_EDGE('',*,*,#3748,.F.);
#3750=DIRECTION('',(0.,-1.,0.));
#3751=VECTOR('',#3750,1.);
#3752=CARTESIAN_POINT('',(-4.191,0.,3.556));
#3753=LINE('',#3752,#3751);
#3754=EDGE_CURVE('E849',#3747,#1131,#3753,.T.);
#3755=ORIENTED_EDGE('',*,*,#3754,.T.);
#3756=EDGE_LOOP('',(#3740,#3741,#3749,#3755));
#3757=FACE_BOUND('',#3756,.T.);
#3758=ADVANCED_FACE('F1665',(#3757),#3739,.F.);
#3759=CARTESIAN_POINT('',(-3.556,0.,3.556));
#3760=DIRECTION('',(0.,-1.,0.));
#3761=DIRECTION('',(0.,0.,-1.));
#3762=AXIS2_PLACEMENT_3D('',#3759,#3760,#3761);
#3763=CYLINDRICAL_SURFACE('',#3762,0.635);
#3764=ORIENTED_EDGE('',*,*,#1141,.T.);
#3765=ORIENTED_EDGE('',*,*,#3754,.F.);
#3766=CARTESIAN_POINT('',(-3.556,0.,3.556));
#3767=DIRECTION('',(0.,-1.,0.));
#3768=DIRECTION('',(0.,0.,1.));
#3769=AXIS2_PLACEMENT_3D('',#3766,#3767,#3768);
#3770=CIRCLE('',#3769,0.635);
#3771=CARTESIAN_POINT('',(-3.556,0.,4.191));
#3772=VERTEX_POINT('',#3771);
#3773=EDGE_CURVE('E818',#3772,#3747,#3770,.T.);
#3774=ORIENTED_EDGE('',*,*,#3773,.F.);
#3775=DIRECTION('',(0.,-1.,0.));
#3776=VECTOR('',#3775,1.);
#3777=CARTESIAN_POINT('',(-3.556,0.,4.191));
#3778=LINE('',#3777,#3776);
#3779=EDGE_CURVE('E851',#3772,#1140,#3778,.T.);
#3780=ORIENTED_EDGE('',*,*,#3779,.T.);
#3781=EDGE_LOOP('',(#3764,#3765,#3774,#3780));
#3782=FACE_BOUND('',#3781,.T.);
#3783=ADVANCED_FACE('F1667',(#3782),#3763,.F.);
#3784=CARTESIAN_POINT('',(3.556,0.,4.191));
#3785=DIRECTION('',(0.,0.,1.));
#3786=DIRECTION('',(1.,0.,0.));
#3787=AXIS2_PLACEMENT_3D('',#3784,#3785,#3786);
#3788=PLANE('',#3787);
#3789=ORIENTED_EDGE('',*,*,#1149,.T.);
#3790=ORIENTED_EDGE('',*,*,#3779,.F.);
#3791=DIRECTION('',(-1.,0.,0.));
#3792=VECTOR('',#3791,1.);
#3793=CARTESIAN_POINT('',(3.556,0.,4.191));
#3794=LINE('',#3793,#3792);
#3795=CARTESIAN_POINT('',(3.556,0.,4.191));
#3796=VERTEX_POINT('',#3795);
#3797=EDGE_CURVE('E815',#3796,#3772,#3794,.T.);
#3798=ORIENTED_EDGE('',*,*,#3797,.F.);
#3799=DIRECTION('',(0.,-1.,0.));
#3800=VECTOR('',#3799,1.);
#3801=CARTESIAN_POINT('',(3.556,0.,4.191));
#3802=LINE('',#3801,#3800);
#3803=EDGE_CURVE('E853',#3796,#1148,#3802,.T.);
#3804=ORIENTED_EDGE('',*,*,#3803,.T.);
#3805=EDGE_LOOP('',(#3789,#3790,#3798,#3804));
#3806=FACE_BOUND('',#3805,.T.);
#3807=ADVANCED_FACE('F1671',(#3806),#3788,.F.);
#3808=CARTESIAN_POINT('',(3.556,0.,3.556));
#3809=DIRECTION('',(0.,-1.,0.));
#3810=DIRECTION('',(0.,0.,-1.));
#3811=AXIS2_PLACEMENT_3D('',#3808,#3809,#3810);
#3812=CYLINDRICAL_SURFACE('',#3811,0.635000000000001);
#3813=ORIENTED_EDGE('',*,*,#1158,.T.);
#3814=ORIENTED_EDGE('',*,*,#3803,.F.);
#3815=CARTESIAN_POINT('',(3.556,0.,3.556));
#3816=DIRECTION('',(0.,-1.,0.));
#3817=DIRECTION('',(0.,0.,-1.));
#3818=AXIS2_PLACEMENT_3D('',#3815,#3816,#3817);
#3819=CIRCLE('',#3818,0.635000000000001);
#3820=CARTESIAN_POINT('',(4.191,0.,3.556));
#3821=VERTEX_POINT('',#3820);
#3822=EDGE_CURVE('E812',#3821,#3796,#3819,.T.);
#3823=ORIENTED_EDGE('',*,*,#3822,.F.);
#3824=DIRECTION('',(0.,-1.,0.));
#3825=VECTOR('',#3824,1.);
#3826=CARTESIAN_POINT('',(4.191,0.,3.556));
#3827=LINE('',#3826,#3825);
#3828=EDGE_CURVE('E855',#3821,#1157,#3827,.T.);
#3829=ORIENTED_EDGE('',*,*,#3828,.T.);
#3830=EDGE_LOOP('',(#3813,#3814,#3823,#3829));
#3831=FACE_BOUND('',#3830,.T.);
#3832=ADVANCED_FACE('F1675',(#3831),#3812,.F.);
#3833=CARTESIAN_POINT('',(4.191,0.,-3.556));
#3834=DIRECTION('',(1.,0.,0.));
#3835=DIRECTION('',(0.,0.,-1.));
#3836=AXIS2_PLACEMENT_3D('',#3833,#3834,#3835);
#3837=PLANE('',#3836);
#3838=ORIENTED_EDGE('',*,*,#1166,.T.);
#3839=ORIENTED_EDGE('',*,*,#3828,.F.);
#3840=DIRECTION('',(0.,0.,1.));
#3841=VECTOR('',#3840,1.);
#3842=CARTESIAN_POINT('',(4.191,0.,-3.556));
#3843=LINE('',#3842,#3841);
#3844=CARTESIAN_POINT('',(4.191,0.,-3.556));
#3845=VERTEX_POINT('',#3844);
#3846=EDGE_CURVE('E809',#3845,#3821,#3843,.T.);
#3847=ORIENTED_EDGE('',*,*,#3846,.F.);
#3848=DIRECTION('',(0.,-1.,0.));
#3849=VECTOR('',#3848,1.);
#3850=CARTESIAN_POINT('',(4.191,0.,-3.556));
#3851=LINE('',#3850,#3849);
#3852=EDGE_CURVE('E857',#3845,#1165,#3851,.T.);
#3853=ORIENTED_EDGE('',*,*,#3852,.T.);
#3854=EDGE_LOOP('',(#3838,#3839,#3847,#3853));
#3855=FACE_BOUND('',#3854,.T.);
#3856=ADVANCED_FACE('F1678',(#3855),#3837,.F.);
#3857=CARTESIAN_POINT('',(3.556,0.,-3.556));
#3858=DIRECTION('',(0.,-1.,0.));
#3859=DIRECTION('',(0.,0.,-1.));
#3860=AXIS2_PLACEMENT_3D('',#3857,#3858,#3859);
#3861=CYLINDRICAL_SURFACE('',#3860,0.635);
#3862=ORIENTED_EDGE('',*,*,#1175,.T.);
#3863=ORIENTED_EDGE('',*,*,#3852,.F.);
#3864=CARTESIAN_POINT('',(3.556,0.,-3.556));
#3865=DIRECTION('',(0.,-1.,0.));
#3866=DIRECTION('',(0.,0.,-1.));
#3867=AXIS2_PLACEMENT_3D('',#3864,#3865,#3866);
#3868=CIRCLE('',#3867,0.635);
#3869=CARTESIAN_POINT('',(3.556,0.,-4.191));
#3870=VERTEX_POINT('',#3869);
#3871=EDGE_CURVE('E806',#3870,#3845,#3868,.T.);
#3872=ORIENTED_EDGE('',*,*,#3871,.F.);
#3873=DIRECTION('',(0.,-1.,0.));
#3874=VECTOR('',#3873,1.);
#3875=CARTESIAN_POINT('',(3.556,0.,-4.191));
#3876=LINE('',#3875,#3874);
#3877=EDGE_CURVE('E859',#3870,#1174,#3876,.T.);
#3878=ORIENTED_EDGE('',*,*,#3877,.T.);
#3879=EDGE_LOOP('',(#3862,#3863,#3872,#3878));
#3880=FACE_BOUND('',#3879,.T.);
#3881=ADVANCED_FACE('F1680',(#3880),#3861,.F.);
#3882=CARTESIAN_POINT('',(-3.556,0.,-4.191));
#3883=DIRECTION('',(0.,0.,-1.));
#3884=DIRECTION('',(-1.,0.,0.));
#3885=AXIS2_PLACEMENT_3D('',#3882,#3883,#3884);
#3886=PLANE('',#3885);
#3887=ORIENTED_EDGE('',*,*,#1181,.T.);
#3888=ORIENTED_EDGE('',*,*,#3877,.F.);
#3889=DIRECTION('',(1.,0.,0.));
#3890=VECTOR('',#3889,1.);
#3891=CARTESIAN_POINT('',(-3.556,0.,-4.191));
#3892=LINE('',#3891,#3890);
#3893=EDGE_CURVE('E802',#3714,#3870,#3892,.T.);
#3894=ORIENTED_EDGE('',*,*,#3893,.F.);
#3895=ORIENTED_EDGE('',*,*,#3715,.T.);
#3896=EDGE_LOOP('',(#3887,#3888,#3894,#3895));
#3897=FACE_BOUND('',#3896,.T.);
#3898=ADVANCED_FACE('F1657',(#3897),#3886,.F.);
#3899=CARTESIAN_POINT('',(-3.556,0.,-3.556));
#3900=DIRECTION('',(0.,-1.,0.));
#3901=DIRECTION('',(0.,0.,-1.));
#3902=AXIS2_PLACEMENT_3D('',#3899,#3900,#3901);
#3903=PLANE('',#3902);
#3904=DIRECTION('',(-1.,0.,0.));
#3905=VECTOR('',#3904,1.);
#3906=CARTESIAN_POINT('',(3.556,0.,3.81));
#3907=LINE('',#3906,#3905);
#3908=CARTESIAN_POINT('',(3.556,0.,3.81));
#3909=VERTEX_POINT('',#3908);
#3910=CARTESIAN_POINT('',(-3.556,0.,3.81));
#3911=VERTEX_POINT('',#3910);
#3912=EDGE_CURVE('E737',#3909,#3911,#3907,.T.);
#3913=ORIENTED_EDGE('',*,*,#3912,.F.);
#3914=CARTESIAN_POINT('',(3.556,0.,3.556));
#3915=DIRECTION('',(0.,-1.,0.));
#3916=DIRECTION('',(0.,0.,-1.));
#3917=AXIS2_PLACEMENT_3D('',#3914,#3915,#3916);
#3918=CIRCLE('',#3917,0.254);
#3919=CARTESIAN_POINT('',(3.81,0.,3.556));
#3920=VERTEX_POINT('',#3919);
#3921=EDGE_CURVE('E768',#3920,#3909,#3918,.T.);
#3922=ORIENTED_EDGE('',*,*,#3921,.F.);
#3923=DIRECTION('',(0.,0.,1.));
#3924=VECTOR('',#3923,1.);
#3925=CARTESIAN_POINT('',(3.81,0.,-3.556));
#3926=LINE('',#3925,#3924);
#3927=CARTESIAN_POINT('',(3.81,0.,-3.556));
#3928=VERTEX_POINT('',#3927);
#3929=EDGE_CURVE('E765',#3928,#3920,#3926,.T.);
#3930=ORIENTED_EDGE('',*,*,#3929,.F.);
#3931=CARTESIAN_POINT('',(3.556,0.,-3.556));
#3932=DIRECTION('',(0.,-1.,0.));
#3933=DIRECTION('',(0.,0.,-1.));
#3934=AXIS2_PLACEMENT_3D('',#3931,#3932,#3933);
#3935=CIRCLE('',#3934,0.254);
#3936=CARTESIAN_POINT('',(3.556,0.,-3.81));
#3937=VERTEX_POINT('',#3936);
#3938=EDGE_CURVE('E762',#3937,#3928,#3935,.T.);
#3939=ORIENTED_EDGE('',*,*,#3938,.F.);
#3940=DIRECTION('',(1.,0.,0.));
#3941=VECTOR('',#3940,1.);
#3942=CARTESIAN_POINT('',(-3.556,0.,-3.81));
#3943=LINE('',#3942,#3941);
#3944=CARTESIAN_POINT('',(-3.556,0.,-3.81));
#3945=VERTEX_POINT('',#3944);
#3946=EDGE_CURVE('E759',#3945,#3937,#3943,.T.);
#3947=ORIENTED_EDGE('',*,*,#3946,.F.);
#3948=CARTESIAN_POINT('',(-3.556,0.,-3.556));
#3949=DIRECTION('',(0.,-1.,0.));
#3950=DIRECTION('',(0.,0.,-1.));
#3951=AXIS2_PLACEMENT_3D('',#3948,#3949,#3950);
#3952=CIRCLE('',#3951,0.254);
#3953=CARTESIAN_POINT('',(-3.81,0.,-3.556));
#3954=VERTEX_POINT('',#3953);
#3955=EDGE_CURVE('E748',#3954,#3945,#3952,.T.);
#3956=ORIENTED_EDGE('',*,*,#3955,.F.);
#3957=DIRECTION('',(0.,0.,-1.));
#3958=VECTOR('',#3957,1.);
#3959=CARTESIAN_POINT('',(-3.81,0.,3.556));
#3960=LINE('',#3959,#3958);
#3961=CARTESIAN_POINT('',(-3.81,0.,3.556));
#3962=VERTEX_POINT('',#3961);
#3963=EDGE_CURVE('E729',#3962,#3954,#3960,.T.);
#3964=ORIENTED_EDGE('',*,*,#3963,.F.);
#3965=CARTESIAN_POINT('',(-3.556,0.,3.556));
#3966=DIRECTION('',(0.,-1.,0.));
#3967=DIRECTION('',(0.,0.,1.));
#3968=AXIS2_PLACEMENT_3D('',#3965,#3966,#3967);
#3969=CIRCLE('',#3968,0.254);
#3970=EDGE_CURVE('E744',#3911,#3962,#3969,.T.);
#3971=ORIENTED_EDGE('',*,*,#3970,.F.);
#3972=EDGE_LOOP('',(#3913,#3922,#3930,#3939,#3947,#3956,#3964,#3971));
#3973=FACE_BOUND('',#3972,.T.);
#3974=ORIENTED_EDGE('',*,*,#3724,.T.);
#3975=ORIENTED_EDGE('',*,*,#3893,.T.);
#3976=ORIENTED_EDGE('',*,*,#3871,.T.);
#3977=ORIENTED_EDGE('',*,*,#3846,.T.);
#3978=ORIENTED_EDGE('',*,*,#3822,.T.);
#3979=ORIENTED_EDGE('',*,*,#3797,.T.);
#3980=ORIENTED_EDGE('',*,*,#3773,.T.);
#3981=ORIENTED_EDGE('',*,*,#3748,.T.);
#3982=EDGE_LOOP('',(#3974,#3975,#3976,#3977,#3978,#3979,#3980,#3981));
#3983=FACE_BOUND('',#3982,.T.);
#3984=ADVANCED_FACE('F742',(#3973,#3983),#3903,.T.);
#3985=CARTESIAN_POINT('',(-3.556,0.,3.556));
#3986=DIRECTION('',(0.,-1.,0.));
#3987=DIRECTION('',(0.,0.,-1.));
#3988=AXIS2_PLACEMENT_3D('',#3985,#3986,#3987);
#3989=CYLINDRICAL_SURFACE('',#3988,0.254);
#3990=ORIENTED_EDGE('',*,*,#52,.F.);
#3991=DIRECTION('',(0.,-1.,0.));
#3992=VECTOR('',#3991,1.);
#3993=CARTESIAN_POINT('',(-3.556,0.,3.81));
#3994=LINE('',#3993,#3992);
#3995=EDGE_CURVE('E751',#3911,#42,#3994,.T.);
#3996=ORIENTED_EDGE('',*,*,#3995,.F.);
#3997=ORIENTED_EDGE('',*,*,#3970,.T.);
#3998=DIRECTION('',(0.,-1.,0.));
#3999=VECTOR('',#3998,1.);
#4000=CARTESIAN_POINT('',(-3.81,0.,3.556));
#4001=LINE('',#4000,#3999);
#4002=EDGE_CURVE('E726',#3962,#51,#4001,.T.);
#4003=ORIENTED_EDGE('',*,*,#4002,.T.);
#4004=EDGE_LOOP('',(#3990,#3996,#3997,#4003));
#4005=FACE_BOUND('',#4004,.T.);
#4006=ADVANCED_FACE('F750',(#4005),#3989,.T.);
#4007=CARTESIAN_POINT('',(3.556,0.,3.81));
#4008=DIRECTION('',(0.,0.,1.));
#4009=DIRECTION('',(1.,0.,0.));
#4010=AXIS2_PLACEMENT_3D('',#4007,#4008,#4009);
#4011=PLANE('',#4010);
#4012=ORIENTED_EDGE('',*,*,#43,.F.);
#4013=DIRECTION('',(0.,-1.,0.));
#4014=VECTOR('',#4013,1.);
#4015=CARTESIAN_POINT('',(3.556,0.,3.81));
#4016=LINE('',#4015,#4014);
#4017=EDGE_CURVE('E788',#3909,#40,#4016,.T.);
#4018=ORIENTED_EDGE('',*,*,#4017,.F.);
#4019=ORIENTED_EDGE('',*,*,#3912,.T.);
#4020=ORIENTED_EDGE('',*,*,#3995,.T.);
#4021=EDGE_LOOP('',(#4012,#4018,#4019,#4020));
#4022=FACE_BOUND('',#4021,.T.);
#4023=ADVANCED_FACE('F2574',(#4022),#4011,.T.);
#4024=CARTESIAN_POINT('',(3.556,0.,3.556));
#4025=DIRECTION('',(0.,-1.,0.));
#4026=DIRECTION('',(0.,0.,-1.));
#4027=AXIS2_PLACEMENT_3D('',#4024,#4025,#4026);
#4028=CYLINDRICAL_SURFACE('',#4027,0.254);
#4029=ORIENTED_EDGE('',*,*,#101,.F.);
#4030=DIRECTION('',(0.,-1.,0.));
#4031=VECTOR('',#4030,1.);
#4032=CARTESIAN_POINT('',(3.81,0.,3.556));
#4033=LINE('',#4032,#4031);
#4034=EDGE_CURVE('E790',#3920,#93,#4033,.T.);
#4035=ORIENTED_EDGE('',*,*,#4034,.F.);
#4036=ORIENTED_EDGE('',*,*,#3921,.T.);
#4037=ORIENTED_EDGE('',*,*,#4017,.T.);
#4038=EDGE_LOOP('',(#4029,#4035,#4036,#4037));
#4039=FACE_BOUND('',#4038,.T.);
#4040=ADVANCED_FACE('F2583',(#4039),#4028,.T.);
#4041=CARTESIAN_POINT('',(3.81,0.,-3.556));
#4042=DIRECTION('',(1.,0.,0.));
#4043=DIRECTION('',(0.,0.,-1.));
#4044=AXIS2_PLACEMENT_3D('',#4041,#4042,#4043);
#4045=PLANE('',#4044);
#4046=ORIENTED_EDGE('',*,*,#94,.F.);
#4047=DIRECTION('',(0.,-1.,0.));
#4048=VECTOR('',#4047,1.);
#4049=CARTESIAN_POINT('',(3.81,0.,-3.556));
#4050=LINE('',#4049,#4048);
#4051=EDGE_CURVE('E792',#3928,#85,#4050,.T.);
#4052=ORIENTED_EDGE('',*,*,#4051,.F.);
#4053=ORIENTED_EDGE('',*,*,#3929,.T.);
#4054=ORIENTED_EDGE('',*,*,#4034,.T.);
#4055=EDGE_LOOP('',(#4046,#4052,#4053,#4054));
#4056=FACE_BOUND('',#4055,.T.);
#4057=ADVANCED_FACE('F2593',(#4056),#4045,.T.);
#4058=CARTESIAN_POINT('',(3.556,0.,-3.556));
#4059=DIRECTION('',(0.,-1.,0.));
#4060=DIRECTION('',(0.,0.,-1.));
#4061=AXIS2_PLACEMENT_3D('',#4058,#4059,#4060);
#4062=CYLINDRICAL_SURFACE('',#4061,0.254);
#4063=ORIENTED_EDGE('',*,*,#86,.F.);
#4064=DIRECTION('',(0.,-1.,0.));
#4065=VECTOR('',#4064,1.);
#4066=CARTESIAN_POINT('',(3.556,0.,-3.81));
#4067=LINE('',#4066,#4065);
#4068=EDGE_CURVE('E794',#3937,#76,#4067,.T.);
#4069=ORIENTED_EDGE('',*,*,#4068,.F.);
#4070=ORIENTED_EDGE('',*,*,#3938,.T.);
#4071=ORIENTED_EDGE('',*,*,#4051,.T.);
#4072=EDGE_LOOP('',(#4063,#4069,#4070,#4071));
#4073=FACE_BOUND('',#4072,.T.);
#4074=ADVANCED_FACE('F2603',(#4073),#4062,.T.);
#4075=CARTESIAN_POINT('',(-3.556,0.,-3.81));
#4076=DIRECTION('',(0.,0.,-1.));
#4077=DIRECTION('',(-1.,0.,0.));
#4078=AXIS2_PLACEMENT_3D('',#4075,#4076,#4077);
#4079=PLANE('',#4078);
#4080=ORIENTED_EDGE('',*,*,#77,.F.);
#4081=DIRECTION('',(0.,-1.,0.));
#4082=VECTOR('',#4081,1.);
#4083=CARTESIAN_POINT('',(-3.556,0.,-3.81));
#4084=LINE('',#4083,#4082);
#4085=EDGE_CURVE('E796',#3945,#68,#4084,.T.);
#4086=ORIENTED_EDGE('',*,*,#4085,.F.);
#4087=ORIENTED_EDGE('',*,*,#3946,.T.);
#4088=ORIENTED_EDGE('',*,*,#4068,.T.);
#4089=EDGE_LOOP('',(#4080,#4086,#4087,#4088));
#4090=FACE_BOUND('',#4089,.T.);
#4091=ADVANCED_FACE('F2613',(#4090),#4079,.T.);
#4092=CARTESIAN_POINT('',(-3.556,0.,-3.556));
#4093=DIRECTION('',(0.,-1.,0.));
#4094=DIRECTION('',(0.,0.,-1.));
#4095=AXIS2_PLACEMENT_3D('',#4092,#4093,#4094);
#4096=CYLINDRICAL_SURFACE('',#4095,0.254);
#4097=ORIENTED_EDGE('',*,*,#69,.F.);
#4098=DIRECTION('',(0.,-1.,0.));
#4099=VECTOR('',#4098,1.);
#4100=CARTESIAN_POINT('',(-3.81,0.,-3.556));
#4101=LINE('',#4100,#4099);
#4102=EDGE_CURVE('E736',#3954,#59,#4101,.T.);
#4103=ORIENTED_EDGE('',*,*,#4102,.F.);
#4104=ORIENTED_EDGE('',*,*,#3955,.T.);
#4105=ORIENTED_EDGE('',*,*,#4085,.T.);
#4106=EDGE_LOOP('',(#4097,#4103,#4104,#4105));
#4107=FACE_BOUND('',#4106,.T.);
#4108=ADVANCED_FACE('F2623',(#4107),#4096,.T.);
#4109=CARTESIAN_POINT('',(-3.81,0.,3.556));
#4110=DIRECTION('',(-1.,0.,0.));
#4111=DIRECTION('',(0.,0.,1.));
#4112=AXIS2_PLACEMENT_3D('',#4109,#4110,#4111);
#4113=PLANE('',#4112);
#4114=ORIENTED_EDGE('',*,*,#60,.F.);
#4115=ORIENTED_EDGE('',*,*,#4002,.F.);
#4116=ORIENTED_EDGE('',*,*,#3963,.T.);
#4117=ORIENTED_EDGE('',*,*,#4102,.T.);
#4118=EDGE_LOOP('',(#4114,#4115,#4116,#4117));
#4119=FACE_BOUND('',#4118,.T.);
#4120=ADVANCED_FACE('F728',(#4119),#4113,.T.);
#4121=CLOSED_SHELL('',(#105,#508,#906,#926,#946,#966,#986,#1006,#1026,#1046,#1066,#1086,#1114,
#1196,#1216,#1236,#1248,#1268,#1280,#1292,#1323,#1347,#1378,#1402,#2148,#2170,#2182,#2199,#2216,
#2238,#2250,#2267,#2284,#2306,#2318,#2335,#2352,#2374,#2386,#2403,#2420,#2442,#2454,#2471,#2488,
#2510,#2522,#2539,#2556,#2578,#2590,#2607,#2624,#2646,#2658,#2675,#2692,#2714,#2726,#2743,#2760,
#2782,#2794,#2811,#2828,#2850,#2862,#2879,#2896,#2918,#2930,#2947,#2964,#2986,#2998,#3015,#3032,
#3054,#3066,#3083,#3100,#3122,#3134,#3151,#3168,#3190,#3202,#3219,#3236,#3258,#3270,#3287,#3304,
#3326,#3338,#3355,#3372,#3394,#3406,#3423,#3440,#3462,#3474,#3491,#3508,#3530,#3542,#3559,#3576,
#3598,#3610,#3627,#3644,#3661,#3673,#3690,#3702,#3734,#3758,#3783,#3807,#3832,#3856,#3881,#3898,
#3984,#4006,#4023,#4040,#4057,#4074,#4091,#4108,#4120));
#4122=MANIFOLD_SOLID_BREP('B2',#4121);
#4123=ADVANCED_BREP_SHAPE_REPRESENTATION('',(#18,#4122),#14);
#4124=SHAPE_DEFINITION_REPRESENTATION(#9,#4123);
ENDSEC;
END-ISO-10303-21;
